VERSION 5.8 ;
BUSBITCHARS "[]" ;
DIVIDERCHAR "/" ;
UNITS
    DATABASE MICRONS 1000 ;
END UNITS

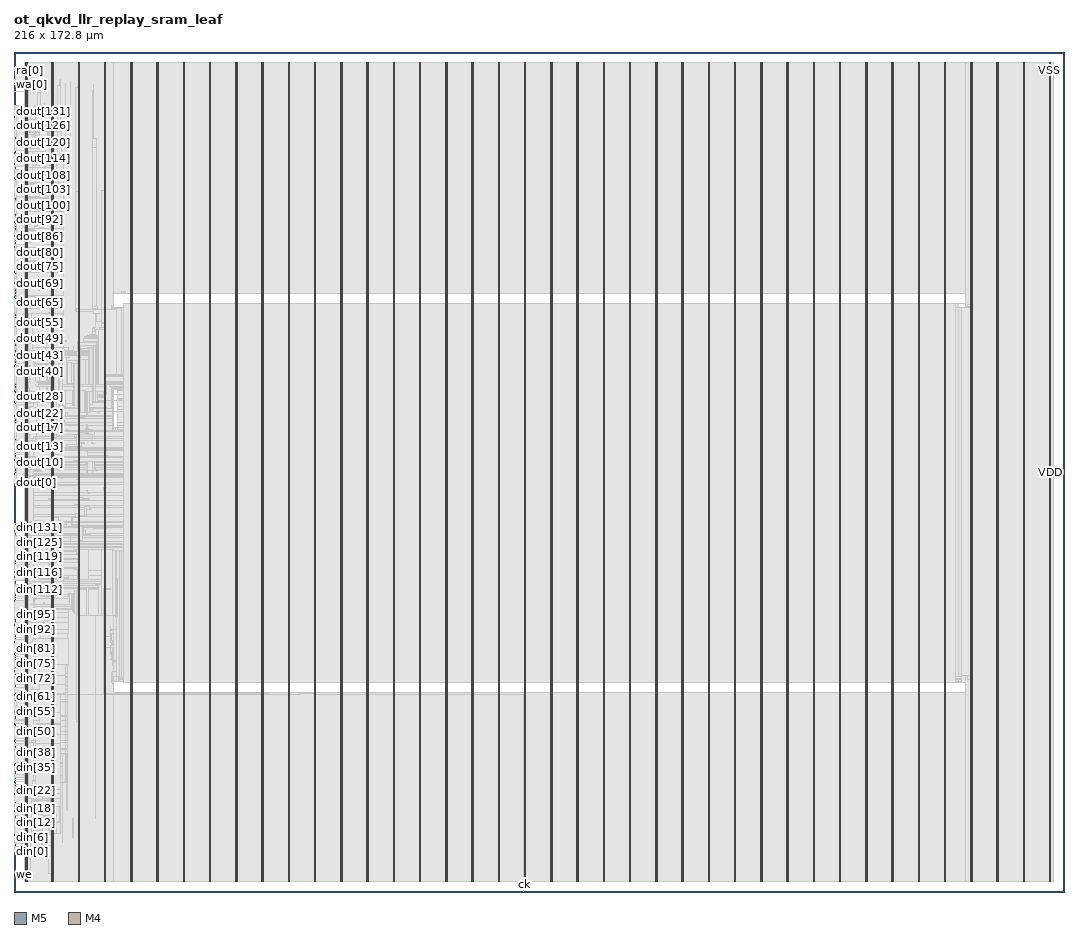
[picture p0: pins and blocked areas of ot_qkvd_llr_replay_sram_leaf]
MACRO ot_qkvd_llr_replay_sram_leaf
  FOREIGN ot_qkvd_llr_replay_sram_leaf 0 0 ;
  CLASS BLOCK ;
  SIZE 216 BY 172.8 ;
  PIN ck
    DIRECTION INPUT ;
    USE SIGNAL ;
    PORT
      LAYER M5 ;
        RECT  104.976 0 105 0.084 ;
    END
    PORT
      LAYER M5 ;
        RECT  104.976 0.016 105 0.085 ;
    END
  END ck
  PIN din[0]
    DIRECTION INPUT ;
    USE SIGNAL ;
    PORT
      LAYER M4 ;
        RECT  0 8.256 0.084 8.28 ;
    END
  END din[0]
  PIN din[100]
    DIRECTION INPUT ;
    USE SIGNAL ;
    PORT
      LAYER M4 ;
        RECT  0 57.888 0.084 57.912 ;
    END
  END din[100]
  PIN din[101]
    DIRECTION INPUT ;
    USE SIGNAL ;
    PORT
      LAYER M4 ;
        RECT  0 58.368 0.084 58.392 ;
    END
  END din[101]
  PIN din[102]
    DIRECTION INPUT ;
    USE SIGNAL ;
    PORT
      LAYER M4 ;
        RECT  0 58.848 0.084 58.872 ;
    END
  END din[102]
  PIN din[103]
    DIRECTION INPUT ;
    USE SIGNAL ;
    PORT
      LAYER M4 ;
        RECT  0 59.376 0.084 59.4 ;
    END
  END din[103]
  PIN din[104]
    DIRECTION INPUT ;
    USE SIGNAL ;
    PORT
      LAYER M4 ;
        RECT  0 59.856 0.084 59.88 ;
    END
  END din[104]
  PIN din[105]
    DIRECTION INPUT ;
    USE SIGNAL ;
    PORT
      LAYER M4 ;
        RECT  0 60.336 0.084 60.36 ;
    END
  END din[105]
  PIN din[106]
    DIRECTION INPUT ;
    USE SIGNAL ;
    PORT
      LAYER M4 ;
        RECT  0 60.864 0.084 60.888 ;
    END
  END din[106]
  PIN din[107]
    DIRECTION INPUT ;
    USE SIGNAL ;
    PORT
      LAYER M4 ;
        RECT  0 61.344 0.084 61.368 ;
    END
  END din[107]
  PIN din[108]
    DIRECTION INPUT ;
    USE SIGNAL ;
    PORT
      LAYER M4 ;
        RECT  0 61.824 0.084 61.848 ;
    END
  END din[108]
  PIN din[109]
    DIRECTION INPUT ;
    USE SIGNAL ;
    PORT
      LAYER M4 ;
        RECT  0 62.352 0.084 62.376 ;
    END
  END din[109]
  PIN din[10]
    DIRECTION INPUT ;
    USE SIGNAL ;
    PORT
      LAYER M4 ;
        RECT  0 13.2 0.084 13.224 ;
    END
  END din[10]
  PIN din[110]
    DIRECTION INPUT ;
    USE SIGNAL ;
    PORT
      LAYER M4 ;
        RECT  0 62.832 0.084 62.856 ;
    END
  END din[110]
  PIN din[111]
    DIRECTION INPUT ;
    USE SIGNAL ;
    PORT
      LAYER M4 ;
        RECT  0 63.312 0.084 63.336 ;
    END
  END din[111]
  PIN din[112]
    DIRECTION INPUT ;
    USE SIGNAL ;
    PORT
      LAYER M4 ;
        RECT  0 63.84 0.084 63.864 ;
    END
  END din[112]
  PIN din[113]
    DIRECTION INPUT ;
    USE SIGNAL ;
    PORT
      LAYER M4 ;
        RECT  0 64.32 0.084 64.344 ;
    END
  END din[113]
  PIN din[114]
    DIRECTION INPUT ;
    USE SIGNAL ;
    PORT
      LAYER M4 ;
        RECT  0 64.8 0.084 64.824 ;
    END
  END din[114]
  PIN din[115]
    DIRECTION INPUT ;
    USE SIGNAL ;
    PORT
      LAYER M4 ;
        RECT  0 65.328 0.084 65.352 ;
    END
  END din[115]
  PIN din[116]
    DIRECTION INPUT ;
    USE SIGNAL ;
    PORT
      LAYER M4 ;
        RECT  0 65.808 0.084 65.832 ;
    END
  END din[116]
  PIN din[117]
    DIRECTION INPUT ;
    USE SIGNAL ;
    PORT
      LAYER M4 ;
        RECT  0 66.288 0.084 66.312 ;
    END
  END din[117]
  PIN din[118]
    DIRECTION INPUT ;
    USE SIGNAL ;
    PORT
      LAYER M4 ;
        RECT  0 66.816 0.084 66.84 ;
    END
  END din[118]
  PIN din[119]
    DIRECTION INPUT ;
    USE SIGNAL ;
    PORT
      LAYER M4 ;
        RECT  0 67.296 0.084 67.32 ;
    END
  END din[119]
  PIN din[11]
    DIRECTION INPUT ;
    USE SIGNAL ;
    PORT
      LAYER M4 ;
        RECT  0 13.68 0.084 13.704 ;
    END
  END din[11]
  PIN din[120]
    DIRECTION INPUT ;
    USE SIGNAL ;
    PORT
      LAYER M4 ;
        RECT  0 67.776 0.084 67.8 ;
    END
  END din[120]
  PIN din[121]
    DIRECTION INPUT ;
    USE SIGNAL ;
    PORT
      LAYER M4 ;
        RECT  0 68.304 0.084 68.328 ;
    END
  END din[121]
  PIN din[122]
    DIRECTION INPUT ;
    USE SIGNAL ;
    PORT
      LAYER M4 ;
        RECT  0 68.784 0.084 68.808 ;
    END
  END din[122]
  PIN din[123]
    DIRECTION INPUT ;
    USE SIGNAL ;
    PORT
      LAYER M4 ;
        RECT  0 69.264 0.084 69.288 ;
    END
  END din[123]
  PIN din[124]
    DIRECTION INPUT ;
    USE SIGNAL ;
    PORT
      LAYER M4 ;
        RECT  0 69.792 0.084 69.816 ;
    END
  END din[124]
  PIN din[125]
    DIRECTION INPUT ;
    USE SIGNAL ;
    PORT
      LAYER M4 ;
        RECT  0 70.272 0.084 70.296 ;
    END
  END din[125]
  PIN din[126]
    DIRECTION INPUT ;
    USE SIGNAL ;
    PORT
      LAYER M4 ;
        RECT  0 70.8 0.084 70.824 ;
    END
  END din[126]
  PIN din[127]
    DIRECTION INPUT ;
    USE SIGNAL ;
    PORT
      LAYER M4 ;
        RECT  0 71.28 0.084 71.304 ;
    END
  END din[127]
  PIN din[128]
    DIRECTION INPUT ;
    USE SIGNAL ;
    PORT
      LAYER M4 ;
        RECT  0 71.76 0.084 71.784 ;
    END
  END din[128]
  PIN din[129]
    DIRECTION INPUT ;
    USE SIGNAL ;
    PORT
      LAYER M4 ;
        RECT  0 72.288 0.084 72.312 ;
    END
  END din[129]
  PIN din[12]
    DIRECTION INPUT ;
    USE SIGNAL ;
    PORT
      LAYER M4 ;
        RECT  0 14.208 0.084 14.232 ;
    END
  END din[12]
  PIN din[130]
    DIRECTION INPUT ;
    USE SIGNAL ;
    PORT
      LAYER M4 ;
        RECT  0 72.768 0.084 72.792 ;
    END
  END din[130]
  PIN din[131]
    DIRECTION INPUT ;
    USE SIGNAL ;
    PORT
      LAYER M4 ;
        RECT  0 73.248 0.084 73.272 ;
    END
  END din[131]
  PIN din[132]
    DIRECTION INPUT ;
    USE SIGNAL ;
    PORT
      LAYER M4 ;
        RECT  0 73.776 0.084 73.8 ;
    END
  END din[132]
  PIN din[133]
    DIRECTION INPUT ;
    USE SIGNAL ;
    PORT
      LAYER M4 ;
        RECT  0 74.256 0.084 74.28 ;
    END
  END din[133]
  PIN din[134]
    DIRECTION INPUT ;
    USE SIGNAL ;
    PORT
      LAYER M4 ;
        RECT  0 74.736 0.084 74.76 ;
    END
  END din[134]
  PIN din[135]
    DIRECTION INPUT ;
    USE SIGNAL ;
    PORT
      LAYER M4 ;
        RECT  0 75.264 0.084 75.288 ;
    END
  END din[135]
  PIN din[136]
    DIRECTION INPUT ;
    USE SIGNAL ;
    PORT
      LAYER M4 ;
        RECT  0 75.744 0.084 75.768 ;
    END
  END din[136]
  PIN din[13]
    DIRECTION INPUT ;
    USE SIGNAL ;
    PORT
      LAYER M4 ;
        RECT  0 14.688 0.084 14.712 ;
    END
  END din[13]
  PIN din[14]
    DIRECTION INPUT ;
    USE SIGNAL ;
    PORT
      LAYER M4 ;
        RECT  0 15.168 0.084 15.192 ;
    END
  END din[14]
  PIN din[15]
    DIRECTION INPUT ;
    USE SIGNAL ;
    PORT
      LAYER M4 ;
        RECT  0 15.696 0.084 15.72 ;
    END
  END din[15]
  PIN din[16]
    DIRECTION INPUT ;
    USE SIGNAL ;
    PORT
      LAYER M4 ;
        RECT  0 16.176 0.084 16.2 ;
    END
  END din[16]
  PIN din[17]
    DIRECTION INPUT ;
    USE SIGNAL ;
    PORT
      LAYER M4 ;
        RECT  0 16.656 0.084 16.68 ;
    END
  END din[17]
  PIN din[18]
    DIRECTION INPUT ;
    USE SIGNAL ;
    PORT
      LAYER M4 ;
        RECT  0 17.184 0.084 17.208 ;
    END
  END din[18]
  PIN din[19]
    DIRECTION INPUT ;
    USE SIGNAL ;
    PORT
      LAYER M4 ;
        RECT  0 17.664 0.084 17.688 ;
    END
  END din[19]
  PIN din[1]
    DIRECTION INPUT ;
    USE SIGNAL ;
    PORT
      LAYER M4 ;
        RECT  0 8.736 0.084 8.76 ;
    END
  END din[1]
  PIN din[20]
    DIRECTION INPUT ;
    USE SIGNAL ;
    PORT
      LAYER M4 ;
        RECT  0 18.144 0.084 18.168 ;
    END
  END din[20]
  PIN din[21]
    DIRECTION INPUT ;
    USE SIGNAL ;
    PORT
      LAYER M4 ;
        RECT  0 18.672 0.084 18.696 ;
    END
  END din[21]
  PIN din[22]
    DIRECTION INPUT ;
    USE SIGNAL ;
    PORT
      LAYER M4 ;
        RECT  0 19.152 0.084 19.176 ;
    END
  END din[22]
  PIN din[23]
    DIRECTION INPUT ;
    USE SIGNAL ;
    PORT
      LAYER M4 ;
        RECT  0 19.632 0.084 19.656 ;
    END
  END din[23]
  PIN din[24]
    DIRECTION INPUT ;
    USE SIGNAL ;
    PORT
      LAYER M4 ;
        RECT  0 20.16 0.084 20.184 ;
    END
  END din[24]
  PIN din[25]
    DIRECTION INPUT ;
    USE SIGNAL ;
    PORT
      LAYER M4 ;
        RECT  0 20.64 0.084 20.664 ;
    END
  END din[25]
  PIN din[26]
    DIRECTION INPUT ;
    USE SIGNAL ;
    PORT
      LAYER M4 ;
        RECT  0 21.12 0.084 21.144 ;
    END
  END din[26]
  PIN din[27]
    DIRECTION INPUT ;
    USE SIGNAL ;
    PORT
      LAYER M4 ;
        RECT  0 21.648 0.084 21.672 ;
    END
  END din[27]
  PIN din[28]
    DIRECTION INPUT ;
    USE SIGNAL ;
    PORT
      LAYER M4 ;
        RECT  0 22.128 0.084 22.152 ;
    END
  END din[28]
  PIN din[29]
    DIRECTION INPUT ;
    USE SIGNAL ;
    PORT
      LAYER M4 ;
        RECT  0 22.608 0.084 22.632 ;
    END
  END din[29]
  PIN din[2]
    DIRECTION INPUT ;
    USE SIGNAL ;
    PORT
      LAYER M4 ;
        RECT  0 9.216 0.084 9.24 ;
    END
  END din[2]
  PIN din[30]
    DIRECTION INPUT ;
    USE SIGNAL ;
    PORT
      LAYER M4 ;
        RECT  0 23.136 0.084 23.16 ;
    END
  END din[30]
  PIN din[31]
    DIRECTION INPUT ;
    USE SIGNAL ;
    PORT
      LAYER M4 ;
        RECT  0 23.616 0.084 23.64 ;
    END
  END din[31]
  PIN din[32]
    DIRECTION INPUT ;
    USE SIGNAL ;
    PORT
      LAYER M4 ;
        RECT  0 24.096 0.084 24.12 ;
    END
  END din[32]
  PIN din[33]
    DIRECTION INPUT ;
    USE SIGNAL ;
    PORT
      LAYER M4 ;
        RECT  0 24.624 0.084 24.648 ;
    END
  END din[33]
  PIN din[34]
    DIRECTION INPUT ;
    USE SIGNAL ;
    PORT
      LAYER M4 ;
        RECT  0 25.104 0.084 25.128 ;
    END
  END din[34]
  PIN din[35]
    DIRECTION INPUT ;
    USE SIGNAL ;
    PORT
      LAYER M4 ;
        RECT  0 25.632 0.084 25.656 ;
    END
  END din[35]
  PIN din[36]
    DIRECTION INPUT ;
    USE SIGNAL ;
    PORT
      LAYER M4 ;
        RECT  0 26.112 0.084 26.136 ;
    END
  END din[36]
  PIN din[37]
    DIRECTION INPUT ;
    USE SIGNAL ;
    PORT
      LAYER M4 ;
        RECT  0 26.592 0.084 26.616 ;
    END
  END din[37]
  PIN din[38]
    DIRECTION INPUT ;
    USE SIGNAL ;
    PORT
      LAYER M4 ;
        RECT  0 27.12 0.084 27.144 ;
    END
  END din[38]
  PIN din[39]
    DIRECTION INPUT ;
    USE SIGNAL ;
    PORT
      LAYER M4 ;
        RECT  0 27.6 0.084 27.624 ;
    END
  END din[39]
  PIN din[3]
    DIRECTION INPUT ;
    USE SIGNAL ;
    PORT
      LAYER M4 ;
        RECT  0 9.744 0.084 9.768 ;
    END
  END din[3]
  PIN din[40]
    DIRECTION INPUT ;
    USE SIGNAL ;
    PORT
      LAYER M4 ;
        RECT  0 28.08 0.084 28.104 ;
    END
  END din[40]
  PIN din[41]
    DIRECTION INPUT ;
    USE SIGNAL ;
    PORT
      LAYER M4 ;
        RECT  0 28.608 0.084 28.632 ;
    END
  END din[41]
  PIN din[42]
    DIRECTION INPUT ;
    USE SIGNAL ;
    PORT
      LAYER M4 ;
        RECT  0 29.088 0.084 29.112 ;
    END
  END din[42]
  PIN din[43]
    DIRECTION INPUT ;
    USE SIGNAL ;
    PORT
      LAYER M4 ;
        RECT  0 29.568 0.084 29.592 ;
    END
  END din[43]
  PIN din[44]
    DIRECTION INPUT ;
    USE SIGNAL ;
    PORT
      LAYER M4 ;
        RECT  0 30.096 0.084 30.12 ;
    END
  END din[44]
  PIN din[45]
    DIRECTION INPUT ;
    USE SIGNAL ;
    PORT
      LAYER M4 ;
        RECT  0 30.576 0.084 30.6 ;
    END
  END din[45]
  PIN din[46]
    DIRECTION INPUT ;
    USE SIGNAL ;
    PORT
      LAYER M4 ;
        RECT  0 31.056 0.084 31.08 ;
    END
  END din[46]
  PIN din[47]
    DIRECTION INPUT ;
    USE SIGNAL ;
    PORT
      LAYER M4 ;
        RECT  0 31.584 0.084 31.608 ;
    END
  END din[47]
  PIN din[48]
    DIRECTION INPUT ;
    USE SIGNAL ;
    PORT
      LAYER M4 ;
        RECT  0 32.064 0.084 32.088 ;
    END
  END din[48]
  PIN din[49]
    DIRECTION INPUT ;
    USE SIGNAL ;
    PORT
      LAYER M4 ;
        RECT  0 32.544 0.084 32.568 ;
    END
  END din[49]
  PIN din[4]
    DIRECTION INPUT ;
    USE SIGNAL ;
    PORT
      LAYER M4 ;
        RECT  0 10.224 0.084 10.248 ;
    END
  END din[4]
  PIN din[50]
    DIRECTION INPUT ;
    USE SIGNAL ;
    PORT
      LAYER M4 ;
        RECT  0 33.072 0.084 33.096 ;
    END
  END din[50]
  PIN din[51]
    DIRECTION INPUT ;
    USE SIGNAL ;
    PORT
      LAYER M4 ;
        RECT  0 33.552 0.084 33.576 ;
    END
  END din[51]
  PIN din[52]
    DIRECTION INPUT ;
    USE SIGNAL ;
    PORT
      LAYER M4 ;
        RECT  0 34.032 0.084 34.056 ;
    END
  END din[52]
  PIN din[53]
    DIRECTION INPUT ;
    USE SIGNAL ;
    PORT
      LAYER M4 ;
        RECT  0 34.56 0.084 34.584 ;
    END
  END din[53]
  PIN din[54]
    DIRECTION INPUT ;
    USE SIGNAL ;
    PORT
      LAYER M4 ;
        RECT  0 35.04 0.084 35.064 ;
    END
  END din[54]
  PIN din[55]
    DIRECTION INPUT ;
    USE SIGNAL ;
    PORT
      LAYER M4 ;
        RECT  0 35.52 0.084 35.544 ;
    END
  END din[55]
  PIN din[56]
    DIRECTION INPUT ;
    USE SIGNAL ;
    PORT
      LAYER M4 ;
        RECT  0 36.048 0.084 36.072 ;
    END
  END din[56]
  PIN din[57]
    DIRECTION INPUT ;
    USE SIGNAL ;
    PORT
      LAYER M4 ;
        RECT  0 36.528 0.084 36.552 ;
    END
  END din[57]
  PIN din[58]
    DIRECTION INPUT ;
    USE SIGNAL ;
    PORT
      LAYER M4 ;
        RECT  0 37.008 0.084 37.032 ;
    END
  END din[58]
  PIN din[59]
    DIRECTION INPUT ;
    USE SIGNAL ;
    PORT
      LAYER M4 ;
        RECT  0 37.536 0.084 37.56 ;
    END
  END din[59]
  PIN din[5]
    DIRECTION INPUT ;
    USE SIGNAL ;
    PORT
      LAYER M4 ;
        RECT  0 10.704 0.084 10.728 ;
    END
  END din[5]
  PIN din[60]
    DIRECTION INPUT ;
    USE SIGNAL ;
    PORT
      LAYER M4 ;
        RECT  0 38.016 0.084 38.04 ;
    END
  END din[60]
  PIN din[61]
    DIRECTION INPUT ;
    USE SIGNAL ;
    PORT
      LAYER M4 ;
        RECT  0 38.496 0.084 38.52 ;
    END
  END din[61]
  PIN din[62]
    DIRECTION INPUT ;
    USE SIGNAL ;
    PORT
      LAYER M4 ;
        RECT  0 39.024 0.084 39.048 ;
    END
  END din[62]
  PIN din[63]
    DIRECTION INPUT ;
    USE SIGNAL ;
    PORT
      LAYER M4 ;
        RECT  0 39.504 0.084 39.528 ;
    END
  END din[63]
  PIN din[64]
    DIRECTION INPUT ;
    USE SIGNAL ;
    PORT
      LAYER M4 ;
        RECT  0 39.984 0.084 40.008 ;
    END
  END din[64]
  PIN din[65]
    DIRECTION INPUT ;
    USE SIGNAL ;
    PORT
      LAYER M4 ;
        RECT  0 40.512 0.084 40.536 ;
    END
  END din[65]
  PIN din[66]
    DIRECTION INPUT ;
    USE SIGNAL ;
    PORT
      LAYER M4 ;
        RECT  0 40.992 0.084 41.016 ;
    END
  END din[66]
  PIN din[67]
    DIRECTION INPUT ;
    USE SIGNAL ;
    PORT
      LAYER M4 ;
        RECT  0 41.472 0.084 41.496 ;
    END
  END din[67]
  PIN din[68]
    DIRECTION INPUT ;
    USE SIGNAL ;
    PORT
      LAYER M4 ;
        RECT  0 42 0.084 42.024 ;
    END
  END din[68]
  PIN din[69]
    DIRECTION INPUT ;
    USE SIGNAL ;
    PORT
      LAYER M4 ;
        RECT  0 42.48 0.084 42.504 ;
    END
  END din[69]
  PIN din[6]
    DIRECTION INPUT ;
    USE SIGNAL ;
    PORT
      LAYER M4 ;
        RECT  0 11.232 0.084 11.256 ;
    END
  END din[6]
  PIN din[70]
    DIRECTION INPUT ;
    USE SIGNAL ;
    PORT
      LAYER M4 ;
        RECT  0 42.96 0.084 42.984 ;
    END
  END din[70]
  PIN din[71]
    DIRECTION INPUT ;
    USE SIGNAL ;
    PORT
      LAYER M4 ;
        RECT  0 43.488 0.084 43.512 ;
    END
  END din[71]
  PIN din[72]
    DIRECTION INPUT ;
    USE SIGNAL ;
    PORT
      LAYER M4 ;
        RECT  0 43.968 0.084 43.992 ;
    END
  END din[72]
  PIN din[73]
    DIRECTION INPUT ;
    USE SIGNAL ;
    PORT
      LAYER M4 ;
        RECT  0 44.448 0.084 44.472 ;
    END
  END din[73]
  PIN din[74]
    DIRECTION INPUT ;
    USE SIGNAL ;
    PORT
      LAYER M4 ;
        RECT  0 44.976 0.084 45 ;
    END
  END din[74]
  PIN din[75]
    DIRECTION INPUT ;
    USE SIGNAL ;
    PORT
      LAYER M4 ;
        RECT  0 45.456 0.084 45.48 ;
    END
  END din[75]
  PIN din[76]
    DIRECTION INPUT ;
    USE SIGNAL ;
    PORT
      LAYER M4 ;
        RECT  0 45.936 0.084 45.96 ;
    END
  END din[76]
  PIN din[77]
    DIRECTION INPUT ;
    USE SIGNAL ;
    PORT
      LAYER M4 ;
        RECT  0 46.464 0.084 46.488 ;
    END
  END din[77]
  PIN din[78]
    DIRECTION INPUT ;
    USE SIGNAL ;
    PORT
      LAYER M4 ;
        RECT  0 46.944 0.084 46.968 ;
    END
  END din[78]
  PIN din[79]
    DIRECTION INPUT ;
    USE SIGNAL ;
    PORT
      LAYER M4 ;
        RECT  0 47.472 0.084 47.496 ;
    END
  END din[79]
  PIN din[7]
    DIRECTION INPUT ;
    USE SIGNAL ;
    PORT
      LAYER M4 ;
        RECT  0 11.712 0.084 11.736 ;
    END
  END din[7]
  PIN din[80]
    DIRECTION INPUT ;
    USE SIGNAL ;
    PORT
      LAYER M4 ;
        RECT  0 47.952 0.084 47.976 ;
    END
  END din[80]
  PIN din[81]
    DIRECTION INPUT ;
    USE SIGNAL ;
    PORT
      LAYER M4 ;
        RECT  0 48.432 0.084 48.456 ;
    END
  END din[81]
  PIN din[82]
    DIRECTION INPUT ;
    USE SIGNAL ;
    PORT
      LAYER M4 ;
        RECT  0 48.96 0.084 48.984 ;
    END
  END din[82]
  PIN din[83]
    DIRECTION INPUT ;
    USE SIGNAL ;
    PORT
      LAYER M4 ;
        RECT  0 49.44 0.084 49.464 ;
    END
  END din[83]
  PIN din[84]
    DIRECTION INPUT ;
    USE SIGNAL ;
    PORT
      LAYER M4 ;
        RECT  0 49.92 0.084 49.944 ;
    END
  END din[84]
  PIN din[85]
    DIRECTION INPUT ;
    USE SIGNAL ;
    PORT
      LAYER M4 ;
        RECT  0 50.448 0.084 50.472 ;
    END
  END din[85]
  PIN din[86]
    DIRECTION INPUT ;
    USE SIGNAL ;
    PORT
      LAYER M4 ;
        RECT  0 50.928 0.084 50.952 ;
    END
  END din[86]
  PIN din[87]
    DIRECTION INPUT ;
    USE SIGNAL ;
    PORT
      LAYER M4 ;
        RECT  0 51.408 0.084 51.432 ;
    END
  END din[87]
  PIN din[88]
    DIRECTION INPUT ;
    USE SIGNAL ;
    PORT
      LAYER M4 ;
        RECT  0 51.936 0.084 51.96 ;
    END
  END din[88]
  PIN din[89]
    DIRECTION INPUT ;
    USE SIGNAL ;
    PORT
      LAYER M4 ;
        RECT  0 52.416 0.084 52.44 ;
    END
  END din[89]
  PIN din[8]
    DIRECTION INPUT ;
    USE SIGNAL ;
    PORT
      LAYER M4 ;
        RECT  0 12.192 0.084 12.216 ;
    END
  END din[8]
  PIN din[90]
    DIRECTION INPUT ;
    USE SIGNAL ;
    PORT
      LAYER M4 ;
        RECT  0 52.896 0.084 52.92 ;
    END
  END din[90]
  PIN din[91]
    DIRECTION INPUT ;
    USE SIGNAL ;
    PORT
      LAYER M4 ;
        RECT  0 53.424 0.084 53.448 ;
    END
  END din[91]
  PIN din[92]
    DIRECTION INPUT ;
    USE SIGNAL ;
    PORT
      LAYER M4 ;
        RECT  0 53.904 0.084 53.928 ;
    END
  END din[92]
  PIN din[93]
    DIRECTION INPUT ;
    USE SIGNAL ;
    PORT
      LAYER M4 ;
        RECT  0 54.384 0.084 54.408 ;
    END
  END din[93]
  PIN din[94]
    DIRECTION INPUT ;
    USE SIGNAL ;
    PORT
      LAYER M4 ;
        RECT  0 54.912 0.084 54.936 ;
    END
  END din[94]
  PIN din[95]
    DIRECTION INPUT ;
    USE SIGNAL ;
    PORT
      LAYER M4 ;
        RECT  0 55.392 0.084 55.416 ;
    END
  END din[95]
  PIN din[96]
    DIRECTION INPUT ;
    USE SIGNAL ;
    PORT
      LAYER M4 ;
        RECT  0 55.872 0.084 55.896 ;
    END
  END din[96]
  PIN din[97]
    DIRECTION INPUT ;
    USE SIGNAL ;
    PORT
      LAYER M4 ;
        RECT  0 56.4 0.084 56.424 ;
    END
  END din[97]
  PIN din[98]
    DIRECTION INPUT ;
    USE SIGNAL ;
    PORT
      LAYER M4 ;
        RECT  0 56.88 0.084 56.904 ;
    END
  END din[98]
  PIN din[99]
    DIRECTION INPUT ;
    USE SIGNAL ;
    PORT
      LAYER M4 ;
        RECT  0 57.36 0.084 57.384 ;
    END
  END din[99]
  PIN din[9]
    DIRECTION INPUT ;
    USE SIGNAL ;
    PORT
      LAYER M4 ;
        RECT  0 12.72 0.084 12.744 ;
    END
  END din[9]
  PIN dout[0]
    DIRECTION OUTPUT ;
    USE SIGNAL ;
    PORT
      LAYER M4 ;
        RECT  0 84.288 0.084 84.312 ;
    END
  END dout[0]
  PIN dout[100]
    DIRECTION OUTPUT ;
    USE SIGNAL ;
    PORT
      LAYER M4 ;
        RECT  0 141.216 0.084 141.24 ;
    END
  END dout[100]
  PIN dout[101]
    DIRECTION OUTPUT ;
    USE SIGNAL ;
    PORT
      LAYER M4 ;
        RECT  0 141.792 0.084 141.816 ;
    END
  END dout[101]
  PIN dout[102]
    DIRECTION OUTPUT ;
    USE SIGNAL ;
    PORT
      LAYER M4 ;
        RECT  0 142.368 0.084 142.392 ;
    END
  END dout[102]
  PIN dout[103]
    DIRECTION OUTPUT ;
    USE SIGNAL ;
    PORT
      LAYER M4 ;
        RECT  0 142.896 0.084 142.92 ;
    END
  END dout[103]
  PIN dout[104]
    DIRECTION OUTPUT ;
    USE SIGNAL ;
    PORT
      LAYER M4 ;
        RECT  0 143.472 0.084 143.496 ;
    END
  END dout[104]
  PIN dout[105]
    DIRECTION OUTPUT ;
    USE SIGNAL ;
    PORT
      LAYER M4 ;
        RECT  0 144.048 0.084 144.072 ;
    END
  END dout[105]
  PIN dout[106]
    DIRECTION OUTPUT ;
    USE SIGNAL ;
    PORT
      LAYER M4 ;
        RECT  0 144.624 0.084 144.648 ;
    END
  END dout[106]
  PIN dout[107]
    DIRECTION OUTPUT ;
    USE SIGNAL ;
    PORT
      LAYER M4 ;
        RECT  0 145.2 0.084 145.224 ;
    END
  END dout[107]
  PIN dout[108]
    DIRECTION OUTPUT ;
    USE SIGNAL ;
    PORT
      LAYER M4 ;
        RECT  0 145.776 0.084 145.8 ;
    END
  END dout[108]
  PIN dout[109]
    DIRECTION OUTPUT ;
    USE SIGNAL ;
    PORT
      LAYER M4 ;
        RECT  0 146.352 0.084 146.376 ;
    END
  END dout[109]
  PIN dout[10]
    DIRECTION OUTPUT ;
    USE SIGNAL ;
    PORT
      LAYER M4 ;
        RECT  0 89.952 0.084 89.976 ;
    END
  END dout[10]
  PIN dout[110]
    DIRECTION OUTPUT ;
    USE SIGNAL ;
    PORT
      LAYER M4 ;
        RECT  0 146.88 0.084 146.904 ;
    END
  END dout[110]
  PIN dout[111]
    DIRECTION OUTPUT ;
    USE SIGNAL ;
    PORT
      LAYER M4 ;
        RECT  0 147.456 0.084 147.48 ;
    END
  END dout[111]
  PIN dout[112]
    DIRECTION OUTPUT ;
    USE SIGNAL ;
    PORT
      LAYER M4 ;
        RECT  0 148.032 0.084 148.056 ;
    END
  END dout[112]
  PIN dout[113]
    DIRECTION OUTPUT ;
    USE SIGNAL ;
    PORT
      LAYER M4 ;
        RECT  0 148.608 0.084 148.632 ;
    END
  END dout[113]
  PIN dout[114]
    DIRECTION OUTPUT ;
    USE SIGNAL ;
    PORT
      LAYER M4 ;
        RECT  0 149.184 0.084 149.208 ;
    END
  END dout[114]
  PIN dout[115]
    DIRECTION OUTPUT ;
    USE SIGNAL ;
    PORT
      LAYER M4 ;
        RECT  0 149.76 0.084 149.784 ;
    END
  END dout[115]
  PIN dout[116]
    DIRECTION OUTPUT ;
    USE SIGNAL ;
    PORT
      LAYER M4 ;
        RECT  0 150.336 0.084 150.36 ;
    END
  END dout[116]
  PIN dout[117]
    DIRECTION OUTPUT ;
    USE SIGNAL ;
    PORT
      LAYER M4 ;
        RECT  0 150.864 0.084 150.888 ;
    END
  END dout[117]
  PIN dout[118]
    DIRECTION OUTPUT ;
    USE SIGNAL ;
    PORT
      LAYER M4 ;
        RECT  0 151.44 0.084 151.464 ;
    END
  END dout[118]
  PIN dout[119]
    DIRECTION OUTPUT ;
    USE SIGNAL ;
    PORT
      LAYER M4 ;
        RECT  0 152.016 0.084 152.04 ;
    END
  END dout[119]
  PIN dout[11]
    DIRECTION OUTPUT ;
    USE SIGNAL ;
    PORT
      LAYER M4 ;
        RECT  0 90.528 0.084 90.552 ;
    END
  END dout[11]
  PIN dout[120]
    DIRECTION OUTPUT ;
    USE SIGNAL ;
    PORT
      LAYER M4 ;
        RECT  0 152.592 0.084 152.616 ;
    END
  END dout[120]
  PIN dout[121]
    DIRECTION OUTPUT ;
    USE SIGNAL ;
    PORT
      LAYER M4 ;
        RECT  0 153.168 0.084 153.192 ;
    END
  END dout[121]
  PIN dout[122]
    DIRECTION OUTPUT ;
    USE SIGNAL ;
    PORT
      LAYER M4 ;
        RECT  0 153.744 0.084 153.768 ;
    END
  END dout[122]
  PIN dout[123]
    DIRECTION OUTPUT ;
    USE SIGNAL ;
    PORT
      LAYER M4 ;
        RECT  0 154.32 0.084 154.344 ;
    END
  END dout[123]
  PIN dout[124]
    DIRECTION OUTPUT ;
    USE SIGNAL ;
    PORT
      LAYER M4 ;
        RECT  0 154.848 0.084 154.872 ;
    END
  END dout[124]
  PIN dout[125]
    DIRECTION OUTPUT ;
    USE SIGNAL ;
    PORT
      LAYER M4 ;
        RECT  0 155.424 0.084 155.448 ;
    END
  END dout[125]
  PIN dout[126]
    DIRECTION OUTPUT ;
    USE SIGNAL ;
    PORT
      LAYER M4 ;
        RECT  0 156 0.084 156.024 ;
    END
  END dout[126]
  PIN dout[127]
    DIRECTION OUTPUT ;
    USE SIGNAL ;
    PORT
      LAYER M4 ;
        RECT  0 156.576 0.084 156.6 ;
    END
  END dout[127]
  PIN dout[128]
    DIRECTION OUTPUT ;
    USE SIGNAL ;
    PORT
      LAYER M4 ;
        RECT  0 157.152 0.084 157.176 ;
    END
  END dout[128]
  PIN dout[129]
    DIRECTION OUTPUT ;
    USE SIGNAL ;
    PORT
      LAYER M4 ;
        RECT  0 157.728 0.084 157.752 ;
    END
  END dout[129]
  PIN dout[12]
    DIRECTION OUTPUT ;
    USE SIGNAL ;
    PORT
      LAYER M4 ;
        RECT  0 91.104 0.084 91.128 ;
    END
  END dout[12]
  PIN dout[130]
    DIRECTION OUTPUT ;
    USE SIGNAL ;
    PORT
      LAYER M4 ;
        RECT  0 158.304 0.084 158.328 ;
    END
  END dout[130]
  PIN dout[131]
    DIRECTION OUTPUT ;
    USE SIGNAL ;
    PORT
      LAYER M4 ;
        RECT  0 158.88 0.084 158.904 ;
    END
  END dout[131]
  PIN dout[132]
    DIRECTION OUTPUT ;
    USE SIGNAL ;
    PORT
      LAYER M4 ;
        RECT  0 159.408 0.084 159.432 ;
    END
  END dout[132]
  PIN dout[133]
    DIRECTION OUTPUT ;
    USE SIGNAL ;
    PORT
      LAYER M4 ;
        RECT  0 159.984 0.084 160.008 ;
    END
  END dout[133]
  PIN dout[134]
    DIRECTION OUTPUT ;
    USE SIGNAL ;
    PORT
      LAYER M4 ;
        RECT  0 160.56 0.084 160.584 ;
    END
  END dout[134]
  PIN dout[135]
    DIRECTION OUTPUT ;
    USE SIGNAL ;
    PORT
      LAYER M4 ;
        RECT  0 161.136 0.084 161.16 ;
    END
  END dout[135]
  PIN dout[136]
    DIRECTION OUTPUT ;
    USE SIGNAL ;
    PORT
      LAYER M4 ;
        RECT  0 161.712 0.084 161.736 ;
    END
  END dout[136]
  PIN dout[13]
    DIRECTION OUTPUT ;
    USE SIGNAL ;
    PORT
      LAYER M4 ;
        RECT  0 91.68 0.084 91.704 ;
    END
  END dout[13]
  PIN dout[14]
    DIRECTION OUTPUT ;
    USE SIGNAL ;
    PORT
      LAYER M4 ;
        RECT  0 92.256 0.084 92.28 ;
    END
  END dout[14]
  PIN dout[15]
    DIRECTION OUTPUT ;
    USE SIGNAL ;
    PORT
      LAYER M4 ;
        RECT  0 92.832 0.084 92.856 ;
    END
  END dout[15]
  PIN dout[16]
    DIRECTION OUTPUT ;
    USE SIGNAL ;
    PORT
      LAYER M4 ;
        RECT  0 93.36 0.084 93.384 ;
    END
  END dout[16]
  PIN dout[17]
    DIRECTION OUTPUT ;
    USE SIGNAL ;
    PORT
      LAYER M4 ;
        RECT  0 93.936 0.084 93.96 ;
    END
  END dout[17]
  PIN dout[18]
    DIRECTION OUTPUT ;
    USE SIGNAL ;
    PORT
      LAYER M4 ;
        RECT  0 94.512 0.084 94.536 ;
    END
  END dout[18]
  PIN dout[19]
    DIRECTION OUTPUT ;
    USE SIGNAL ;
    PORT
      LAYER M4 ;
        RECT  0 95.088 0.084 95.112 ;
    END
  END dout[19]
  PIN dout[1]
    DIRECTION OUTPUT ;
    USE SIGNAL ;
    PORT
      LAYER M4 ;
        RECT  0 84.864 0.084 84.888 ;
    END
  END dout[1]
  PIN dout[20]
    DIRECTION OUTPUT ;
    USE SIGNAL ;
    PORT
      LAYER M4 ;
        RECT  0 95.664 0.084 95.688 ;
    END
  END dout[20]
  PIN dout[21]
    DIRECTION OUTPUT ;
    USE SIGNAL ;
    PORT
      LAYER M4 ;
        RECT  0 96.24 0.084 96.264 ;
    END
  END dout[21]
  PIN dout[22]
    DIRECTION OUTPUT ;
    USE SIGNAL ;
    PORT
      LAYER M4 ;
        RECT  0 96.816 0.084 96.84 ;
    END
  END dout[22]
  PIN dout[23]
    DIRECTION OUTPUT ;
    USE SIGNAL ;
    PORT
      LAYER M4 ;
        RECT  0 97.392 0.084 97.416 ;
    END
  END dout[23]
  PIN dout[24]
    DIRECTION OUTPUT ;
    USE SIGNAL ;
    PORT
      LAYER M4 ;
        RECT  0 97.92 0.084 97.944 ;
    END
  END dout[24]
  PIN dout[25]
    DIRECTION OUTPUT ;
    USE SIGNAL ;
    PORT
      LAYER M4 ;
        RECT  0 98.496 0.084 98.52 ;
    END
  END dout[25]
  PIN dout[26]
    DIRECTION OUTPUT ;
    USE SIGNAL ;
    PORT
      LAYER M4 ;
        RECT  0 99.072 0.084 99.096 ;
    END
  END dout[26]
  PIN dout[27]
    DIRECTION OUTPUT ;
    USE SIGNAL ;
    PORT
      LAYER M4 ;
        RECT  0 99.648 0.084 99.672 ;
    END
  END dout[27]
  PIN dout[28]
    DIRECTION OUTPUT ;
    USE SIGNAL ;
    PORT
      LAYER M4 ;
        RECT  0 100.224 0.084 100.248 ;
    END
  END dout[28]
  PIN dout[29]
    DIRECTION OUTPUT ;
    USE SIGNAL ;
    PORT
      LAYER M4 ;
        RECT  0 100.8 0.084 100.824 ;
    END
  END dout[29]
  PIN dout[2]
    DIRECTION OUTPUT ;
    USE SIGNAL ;
    PORT
      LAYER M4 ;
        RECT  0 85.392 0.084 85.416 ;
    END
  END dout[2]
  PIN dout[30]
    DIRECTION OUTPUT ;
    USE SIGNAL ;
    PORT
      LAYER M4 ;
        RECT  0 101.376 0.084 101.4 ;
    END
  END dout[30]
  PIN dout[31]
    DIRECTION OUTPUT ;
    USE SIGNAL ;
    PORT
      LAYER M4 ;
        RECT  0 101.904 0.084 101.928 ;
    END
  END dout[31]
  PIN dout[32]
    DIRECTION OUTPUT ;
    USE SIGNAL ;
    PORT
      LAYER M4 ;
        RECT  0 102.48 0.084 102.504 ;
    END
  END dout[32]
  PIN dout[33]
    DIRECTION OUTPUT ;
    USE SIGNAL ;
    PORT
      LAYER M4 ;
        RECT  0 103.056 0.084 103.08 ;
    END
  END dout[33]
  PIN dout[34]
    DIRECTION OUTPUT ;
    USE SIGNAL ;
    PORT
      LAYER M4 ;
        RECT  0 103.632 0.084 103.656 ;
    END
  END dout[34]
  PIN dout[35]
    DIRECTION OUTPUT ;
    USE SIGNAL ;
    PORT
      LAYER M4 ;
        RECT  0 104.208 0.084 104.232 ;
    END
  END dout[35]
  PIN dout[36]
    DIRECTION OUTPUT ;
    USE SIGNAL ;
    PORT
      LAYER M4 ;
        RECT  0 104.784 0.084 104.808 ;
    END
  END dout[36]
  PIN dout[37]
    DIRECTION OUTPUT ;
    USE SIGNAL ;
    PORT
      LAYER M4 ;
        RECT  0 105.36 0.084 105.384 ;
    END
  END dout[37]
  PIN dout[38]
    DIRECTION OUTPUT ;
    USE SIGNAL ;
    PORT
      LAYER M4 ;
        RECT  0 105.888 0.084 105.912 ;
    END
  END dout[38]
  PIN dout[39]
    DIRECTION OUTPUT ;
    USE SIGNAL ;
    PORT
      LAYER M4 ;
        RECT  0 106.464 0.084 106.488 ;
    END
  END dout[39]
  PIN dout[3]
    DIRECTION OUTPUT ;
    USE SIGNAL ;
    PORT
      LAYER M4 ;
        RECT  0 85.968 0.084 85.992 ;
    END
  END dout[3]
  PIN dout[40]
    DIRECTION OUTPUT ;
    USE SIGNAL ;
    PORT
      LAYER M4 ;
        RECT  0 107.04 0.084 107.064 ;
    END
  END dout[40]
  PIN dout[41]
    DIRECTION OUTPUT ;
    USE SIGNAL ;
    PORT
      LAYER M4 ;
        RECT  0 107.616 0.084 107.64 ;
    END
  END dout[41]
  PIN dout[42]
    DIRECTION OUTPUT ;
    USE SIGNAL ;
    PORT
      LAYER M4 ;
        RECT  0 108.192 0.084 108.216 ;
    END
  END dout[42]
  PIN dout[43]
    DIRECTION OUTPUT ;
    USE SIGNAL ;
    PORT
      LAYER M4 ;
        RECT  0 108.768 0.084 108.792 ;
    END
  END dout[43]
  PIN dout[44]
    DIRECTION OUTPUT ;
    USE SIGNAL ;
    PORT
      LAYER M4 ;
        RECT  0 109.344 0.084 109.368 ;
    END
  END dout[44]
  PIN dout[45]
    DIRECTION OUTPUT ;
    USE SIGNAL ;
    PORT
      LAYER M4 ;
        RECT  0 109.872 0.084 109.896 ;
    END
  END dout[45]
  PIN dout[46]
    DIRECTION OUTPUT ;
    USE SIGNAL ;
    PORT
      LAYER M4 ;
        RECT  0 110.448 0.084 110.472 ;
    END
  END dout[46]
  PIN dout[47]
    DIRECTION OUTPUT ;
    USE SIGNAL ;
    PORT
      LAYER M4 ;
        RECT  0 111.024 0.084 111.048 ;
    END
  END dout[47]
  PIN dout[48]
    DIRECTION OUTPUT ;
    USE SIGNAL ;
    PORT
      LAYER M4 ;
        RECT  0 111.6 0.084 111.624 ;
    END
  END dout[48]
  PIN dout[49]
    DIRECTION OUTPUT ;
    USE SIGNAL ;
    PORT
      LAYER M4 ;
        RECT  0 112.176 0.084 112.2 ;
    END
  END dout[49]
  PIN dout[4]
    DIRECTION OUTPUT ;
    USE SIGNAL ;
    PORT
      LAYER M4 ;
        RECT  0 86.544 0.084 86.568 ;
    END
  END dout[4]
  PIN dout[50]
    DIRECTION OUTPUT ;
    USE SIGNAL ;
    PORT
      LAYER M4 ;
        RECT  0 112.752 0.084 112.776 ;
    END
  END dout[50]
  PIN dout[51]
    DIRECTION OUTPUT ;
    USE SIGNAL ;
    PORT
      LAYER M4 ;
        RECT  0 113.328 0.084 113.352 ;
    END
  END dout[51]
  PIN dout[52]
    DIRECTION OUTPUT ;
    USE SIGNAL ;
    PORT
      LAYER M4 ;
        RECT  0 113.856 0.084 113.88 ;
    END
  END dout[52]
  PIN dout[53]
    DIRECTION OUTPUT ;
    USE SIGNAL ;
    PORT
      LAYER M4 ;
        RECT  0 114.432 0.084 114.456 ;
    END
  END dout[53]
  PIN dout[54]
    DIRECTION OUTPUT ;
    USE SIGNAL ;
    PORT
      LAYER M4 ;
        RECT  0 115.008 0.084 115.032 ;
    END
  END dout[54]
  PIN dout[55]
    DIRECTION OUTPUT ;
    USE SIGNAL ;
    PORT
      LAYER M4 ;
        RECT  0 115.584 0.084 115.608 ;
    END
  END dout[55]
  PIN dout[56]
    DIRECTION OUTPUT ;
    USE SIGNAL ;
    PORT
      LAYER M4 ;
        RECT  0 116.16 0.084 116.184 ;
    END
  END dout[56]
  PIN dout[57]
    DIRECTION OUTPUT ;
    USE SIGNAL ;
    PORT
      LAYER M4 ;
        RECT  0 116.736 0.084 116.76 ;
    END
  END dout[57]
  PIN dout[58]
    DIRECTION OUTPUT ;
    USE SIGNAL ;
    PORT
      LAYER M4 ;
        RECT  0 117.312 0.084 117.336 ;
    END
  END dout[58]
  PIN dout[59]
    DIRECTION OUTPUT ;
    USE SIGNAL ;
    PORT
      LAYER M4 ;
        RECT  0 117.888 0.084 117.912 ;
    END
  END dout[59]
  PIN dout[5]
    DIRECTION OUTPUT ;
    USE SIGNAL ;
    PORT
      LAYER M4 ;
        RECT  0 87.12 0.084 87.144 ;
    END
  END dout[5]
  PIN dout[60]
    DIRECTION OUTPUT ;
    USE SIGNAL ;
    PORT
      LAYER M4 ;
        RECT  0 118.416 0.084 118.44 ;
    END
  END dout[60]
  PIN dout[61]
    DIRECTION OUTPUT ;
    USE SIGNAL ;
    PORT
      LAYER M4 ;
        RECT  0 118.992 0.084 119.016 ;
    END
  END dout[61]
  PIN dout[62]
    DIRECTION OUTPUT ;
    USE SIGNAL ;
    PORT
      LAYER M4 ;
        RECT  0 119.568 0.084 119.592 ;
    END
  END dout[62]
  PIN dout[63]
    DIRECTION OUTPUT ;
    USE SIGNAL ;
    PORT
      LAYER M4 ;
        RECT  0 120.144 0.084 120.168 ;
    END
  END dout[63]
  PIN dout[64]
    DIRECTION OUTPUT ;
    USE SIGNAL ;
    PORT
      LAYER M4 ;
        RECT  0 120.72 0.084 120.744 ;
    END
  END dout[64]
  PIN dout[65]
    DIRECTION OUTPUT ;
    USE SIGNAL ;
    PORT
      LAYER M4 ;
        RECT  0 121.296 0.084 121.32 ;
    END
  END dout[65]
  PIN dout[66]
    DIRECTION OUTPUT ;
    USE SIGNAL ;
    PORT
      LAYER M4 ;
        RECT  0 121.872 0.084 121.896 ;
    END
  END dout[66]
  PIN dout[67]
    DIRECTION OUTPUT ;
    USE SIGNAL ;
    PORT
      LAYER M4 ;
        RECT  0 122.4 0.084 122.424 ;
    END
  END dout[67]
  PIN dout[68]
    DIRECTION OUTPUT ;
    USE SIGNAL ;
    PORT
      LAYER M4 ;
        RECT  0 122.976 0.084 123 ;
    END
  END dout[68]
  PIN dout[69]
    DIRECTION OUTPUT ;
    USE SIGNAL ;
    PORT
      LAYER M4 ;
        RECT  0 123.552 0.084 123.576 ;
    END
  END dout[69]
  PIN dout[6]
    DIRECTION OUTPUT ;
    USE SIGNAL ;
    PORT
      LAYER M4 ;
        RECT  0 87.696 0.084 87.72 ;
    END
  END dout[6]
  PIN dout[70]
    DIRECTION OUTPUT ;
    USE SIGNAL ;
    PORT
      LAYER M4 ;
        RECT  0 124.128 0.084 124.152 ;
    END
  END dout[70]
  PIN dout[71]
    DIRECTION OUTPUT ;
    USE SIGNAL ;
    PORT
      LAYER M4 ;
        RECT  0 124.704 0.084 124.728 ;
    END
  END dout[71]
  PIN dout[72]
    DIRECTION OUTPUT ;
    USE SIGNAL ;
    PORT
      LAYER M4 ;
        RECT  0 125.28 0.084 125.304 ;
    END
  END dout[72]
  PIN dout[73]
    DIRECTION OUTPUT ;
    USE SIGNAL ;
    PORT
      LAYER M4 ;
        RECT  0 125.856 0.084 125.88 ;
    END
  END dout[73]
  PIN dout[74]
    DIRECTION OUTPUT ;
    USE SIGNAL ;
    PORT
      LAYER M4 ;
        RECT  0 126.384 0.084 126.408 ;
    END
  END dout[74]
  PIN dout[75]
    DIRECTION OUTPUT ;
    USE SIGNAL ;
    PORT
      LAYER M4 ;
        RECT  0 126.96 0.084 126.984 ;
    END
  END dout[75]
  PIN dout[76]
    DIRECTION OUTPUT ;
    USE SIGNAL ;
    PORT
      LAYER M4 ;
        RECT  0 127.536 0.084 127.56 ;
    END
  END dout[76]
  PIN dout[77]
    DIRECTION OUTPUT ;
    USE SIGNAL ;
    PORT
      LAYER M4 ;
        RECT  0 128.112 0.084 128.136 ;
    END
  END dout[77]
  PIN dout[78]
    DIRECTION OUTPUT ;
    USE SIGNAL ;
    PORT
      LAYER M4 ;
        RECT  0 128.688 0.084 128.712 ;
    END
  END dout[78]
  PIN dout[79]
    DIRECTION OUTPUT ;
    USE SIGNAL ;
    PORT
      LAYER M4 ;
        RECT  0 129.264 0.084 129.288 ;
    END
  END dout[79]
  PIN dout[7]
    DIRECTION OUTPUT ;
    USE SIGNAL ;
    PORT
      LAYER M4 ;
        RECT  0 88.272 0.084 88.296 ;
    END
  END dout[7]
  PIN dout[80]
    DIRECTION OUTPUT ;
    USE SIGNAL ;
    PORT
      LAYER M4 ;
        RECT  0 129.84 0.084 129.864 ;
    END
  END dout[80]
  PIN dout[81]
    DIRECTION OUTPUT ;
    USE SIGNAL ;
    PORT
      LAYER M4 ;
        RECT  0 130.368 0.084 130.392 ;
    END
  END dout[81]
  PIN dout[82]
    DIRECTION OUTPUT ;
    USE SIGNAL ;
    PORT
      LAYER M4 ;
        RECT  0 130.944 0.084 130.968 ;
    END
  END dout[82]
  PIN dout[83]
    DIRECTION OUTPUT ;
    USE SIGNAL ;
    PORT
      LAYER M4 ;
        RECT  0 131.52 0.084 131.544 ;
    END
  END dout[83]
  PIN dout[84]
    DIRECTION OUTPUT ;
    USE SIGNAL ;
    PORT
      LAYER M4 ;
        RECT  0 132.096 0.084 132.12 ;
    END
  END dout[84]
  PIN dout[85]
    DIRECTION OUTPUT ;
    USE SIGNAL ;
    PORT
      LAYER M4 ;
        RECT  0 132.672 0.084 132.696 ;
    END
  END dout[85]
  PIN dout[86]
    DIRECTION OUTPUT ;
    USE SIGNAL ;
    PORT
      LAYER M4 ;
        RECT  0 133.248 0.084 133.272 ;
    END
  END dout[86]
  PIN dout[87]
    DIRECTION OUTPUT ;
    USE SIGNAL ;
    PORT
      LAYER M4 ;
        RECT  0 133.824 0.084 133.848 ;
    END
  END dout[87]
  PIN dout[88]
    DIRECTION OUTPUT ;
    USE SIGNAL ;
    PORT
      LAYER M4 ;
        RECT  0 134.352 0.084 134.376 ;
    END
  END dout[88]
  PIN dout[89]
    DIRECTION OUTPUT ;
    USE SIGNAL ;
    PORT
      LAYER M4 ;
        RECT  0 134.928 0.084 134.952 ;
    END
  END dout[89]
  PIN dout[8]
    DIRECTION OUTPUT ;
    USE SIGNAL ;
    PORT
      LAYER M4 ;
        RECT  0 88.848 0.084 88.872 ;
    END
  END dout[8]
  PIN dout[90]
    DIRECTION OUTPUT ;
    USE SIGNAL ;
    PORT
      LAYER M4 ;
        RECT  0 135.504 0.084 135.528 ;
    END
  END dout[90]
  PIN dout[91]
    DIRECTION OUTPUT ;
    USE SIGNAL ;
    PORT
      LAYER M4 ;
        RECT  0 136.08 0.084 136.104 ;
    END
  END dout[91]
  PIN dout[92]
    DIRECTION OUTPUT ;
    USE SIGNAL ;
    PORT
      LAYER M4 ;
        RECT  0 136.656 0.084 136.68 ;
    END
  END dout[92]
  PIN dout[93]
    DIRECTION OUTPUT ;
    USE SIGNAL ;
    PORT
      LAYER M4 ;
        RECT  0 137.232 0.084 137.256 ;
    END
  END dout[93]
  PIN dout[94]
    DIRECTION OUTPUT ;
    USE SIGNAL ;
    PORT
      LAYER M4 ;
        RECT  0 137.808 0.084 137.832 ;
    END
  END dout[94]
  PIN dout[95]
    DIRECTION OUTPUT ;
    USE SIGNAL ;
    PORT
      LAYER M4 ;
        RECT  0 138.384 0.084 138.408 ;
    END
  END dout[95]
  PIN dout[96]
    DIRECTION OUTPUT ;
    USE SIGNAL ;
    PORT
      LAYER M4 ;
        RECT  0 138.912 0.084 138.936 ;
    END
  END dout[96]
  PIN dout[97]
    DIRECTION OUTPUT ;
    USE SIGNAL ;
    PORT
      LAYER M4 ;
        RECT  0 139.488 0.084 139.512 ;
    END
  END dout[97]
  PIN dout[98]
    DIRECTION OUTPUT ;
    USE SIGNAL ;
    PORT
      LAYER M4 ;
        RECT  0 140.064 0.084 140.088 ;
    END
  END dout[98]
  PIN dout[99]
    DIRECTION OUTPUT ;
    USE SIGNAL ;
    PORT
      LAYER M4 ;
        RECT  0 140.64 0.084 140.664 ;
    END
  END dout[99]
  PIN dout[9]
    DIRECTION OUTPUT ;
    USE SIGNAL ;
    PORT
      LAYER M4 ;
        RECT  0 89.376 0.084 89.4 ;
    END
  END dout[9]
  PIN ra[0]
    DIRECTION INPUT ;
    USE SIGNAL ;
    PORT
      LAYER M4 ;
        RECT  0 169.056 0.084 169.08 ;
    END
  END ra[0]
  PIN ra[1]
    DIRECTION INPUT ;
    USE SIGNAL ;
    PORT
      LAYER M4 ;
        RECT  0 169.248 0.084 169.272 ;
    END
  END ra[1]
  PIN ra[2]
    DIRECTION INPUT ;
    USE SIGNAL ;
    PORT
      LAYER M4 ;
        RECT  0 169.392 0.084 169.416 ;
    END
  END ra[2]
  PIN ra[3]
    DIRECTION INPUT ;
    USE SIGNAL ;
    PORT
      LAYER M4 ;
        RECT  0 169.584 0.084 169.608 ;
    END
  END ra[3]
  PIN ra[4]
    DIRECTION INPUT ;
    USE SIGNAL ;
    PORT
      LAYER M4 ;
        RECT  0 169.728 0.084 169.752 ;
    END
  END ra[4]
  PIN ra[5]
    DIRECTION INPUT ;
    USE SIGNAL ;
    PORT
      LAYER M4 ;
        RECT  0 169.92 0.084 169.944 ;
    END
  END ra[5]
  PIN wa[0]
    DIRECTION INPUT ;
    USE SIGNAL ;
    PORT
      LAYER M4 ;
        RECT  0 166.08 0.084 166.104 ;
    END
  END wa[0]
  PIN wa[1]
    DIRECTION INPUT ;
    USE SIGNAL ;
    PORT
      LAYER M4 ;
        RECT  0 166.224 0.084 166.248 ;
    END
  END wa[1]
  PIN wa[2]
    DIRECTION INPUT ;
    USE SIGNAL ;
    PORT
      LAYER M4 ;
        RECT  0 166.416 0.084 166.44 ;
    END
  END wa[2]
  PIN wa[3]
    DIRECTION INPUT ;
    USE SIGNAL ;
    PORT
      LAYER M4 ;
        RECT  0 166.56 0.084 166.584 ;
    END
  END wa[3]
  PIN wa[4]
    DIRECTION INPUT ;
    USE SIGNAL ;
    PORT
      LAYER M4 ;
        RECT  0 166.752 0.084 166.776 ;
    END
  END wa[4]
  PIN wa[5]
    DIRECTION INPUT ;
    USE SIGNAL ;
    PORT
      LAYER M4 ;
        RECT  0 166.896 0.084 166.92 ;
    END
  END wa[5]
  PIN we
    DIRECTION INPUT ;
    USE SIGNAL ;
    PORT
      LAYER M4 ;
        RECT  0 3.504 0.084 3.528 ;
    END
    PORT
      LAYER M4 ;
        RECT  0.06 3.504 2.408 3.528 ;
    END
  END we
  PIN VDD
    DIRECTION INOUT ;
    USE POWER ;
    PORT
      LAYER M5 ;
        RECT  213.192 2.151 213.312 170.649 ;
        RECT  207.792 2.151 207.912 170.649 ;
        RECT  202.392 2.151 202.512 170.649 ;
        RECT  196.992 2.151 197.112 170.649 ;
        RECT  191.592 2.151 191.712 170.649 ;
        RECT  186.192 2.151 186.312 170.649 ;
        RECT  180.792 2.151 180.912 170.649 ;
        RECT  175.392 2.151 175.512 170.649 ;
        RECT  169.992 2.151 170.112 170.649 ;
        RECT  164.592 2.151 164.712 170.649 ;
        RECT  159.192 2.151 159.312 170.649 ;
        RECT  153.792 2.151 153.912 170.649 ;
        RECT  148.392 2.151 148.512 170.649 ;
        RECT  142.992 2.151 143.112 170.649 ;
        RECT  137.592 2.151 137.712 170.649 ;
        RECT  132.192 2.151 132.312 170.649 ;
        RECT  126.792 2.151 126.912 170.649 ;
        RECT  121.392 2.151 121.512 170.649 ;
        RECT  115.992 2.151 116.112 170.649 ;
        RECT  110.592 2.151 110.712 170.649 ;
        RECT  105.192 2.151 105.312 170.649 ;
        RECT  99.792 2.151 99.912 170.649 ;
        RECT  94.392 2.151 94.512 170.649 ;
        RECT  88.992 2.151 89.112 170.649 ;
        RECT  83.592 2.151 83.712 170.649 ;
        RECT  78.192 2.151 78.312 170.649 ;
        RECT  72.792 2.151 72.912 170.649 ;
        RECT  67.392 2.151 67.512 170.649 ;
        RECT  61.992 2.151 62.112 170.649 ;
        RECT  56.592 2.151 56.712 170.649 ;
        RECT  51.192 2.151 51.312 170.649 ;
        RECT  45.792 2.151 45.912 170.649 ;
        RECT  40.392 2.151 40.512 170.649 ;
        RECT  34.992 2.151 35.112 170.649 ;
        RECT  29.592 2.151 29.712 170.649 ;
        RECT  24.192 2.151 24.312 170.649 ;
        RECT  18.792 2.151 18.912 170.649 ;
        RECT  13.392 2.151 13.512 170.649 ;
        RECT  7.992 2.151 8.112 170.649 ;
        RECT  2.592 2.151 2.712 170.649 ;
    END
  END VDD
  PIN VSS
    DIRECTION INOUT ;
    USE GROUND ;
    PORT
      LAYER M5 ;
        RECT  213 2.137 213.12 170.663 ;
        RECT  207.6 2.137 207.72 170.663 ;
        RECT  202.2 2.137 202.32 170.663 ;
        RECT  196.8 2.137 196.92 170.663 ;
        RECT  191.4 2.137 191.52 170.663 ;
        RECT  186 2.137 186.12 170.663 ;
        RECT  180.6 2.137 180.72 170.663 ;
        RECT  175.2 2.137 175.32 170.663 ;
        RECT  169.8 2.137 169.92 170.663 ;
        RECT  164.4 2.137 164.52 170.663 ;
        RECT  159 2.137 159.12 170.663 ;
        RECT  153.6 2.137 153.72 170.663 ;
        RECT  148.2 2.137 148.32 170.663 ;
        RECT  142.8 2.137 142.92 170.663 ;
        RECT  137.4 2.137 137.52 170.663 ;
        RECT  132 2.137 132.12 170.663 ;
        RECT  126.6 2.137 126.72 170.663 ;
        RECT  121.2 2.137 121.32 170.663 ;
        RECT  115.8 2.137 115.92 170.663 ;
        RECT  110.4 2.137 110.52 170.663 ;
        RECT  105 2.137 105.12 170.663 ;
        RECT  99.6 2.137 99.72 170.663 ;
        RECT  94.2 2.137 94.32 170.663 ;
        RECT  88.8 2.137 88.92 170.663 ;
        RECT  83.4 2.137 83.52 170.663 ;
        RECT  78 2.137 78.12 170.663 ;
        RECT  72.6 2.137 72.72 170.663 ;
        RECT  67.2 2.137 67.32 170.663 ;
        RECT  61.8 2.137 61.92 170.663 ;
        RECT  56.4 2.137 56.52 170.663 ;
        RECT  51 2.137 51.12 170.663 ;
        RECT  45.6 2.137 45.72 170.663 ;
        RECT  40.2 2.137 40.32 170.663 ;
        RECT  34.8 2.137 34.92 170.663 ;
        RECT  29.4 2.137 29.52 170.663 ;
        RECT  24 2.137 24.12 170.663 ;
        RECT  18.6 2.137 18.72 170.663 ;
        RECT  13.2 2.137 13.32 170.663 ;
        RECT  7.8 2.137 7.92 170.663 ;
        RECT  2.4 2.137 2.52 170.663 ;
    END
  END VSS
  # OT_OBS_CLOSED layer=M5 d_um=1.536 added=64
  OBS
    LAYER RVTN ;
     RECT  2.16 2.16 213.84 2.295 ;
     RECT  2.16 2.565 213.84 2.835 ;
     RECT  2.16 3.105 213.84 3.375 ;
     RECT  2.16 3.645 213.84 3.915 ;
     RECT  2.16 4.185 213.84 4.455 ;
     RECT  2.16 4.725 213.84 4.995 ;
     RECT  2.16 5.265 213.84 5.535 ;
     RECT  2.16 5.805 213.84 6.075 ;
     RECT  2.16 6.345 213.84 6.615 ;
     RECT  2.16 6.885 213.84 7.155 ;
     RECT  2.16 7.425 213.84 7.695 ;
     RECT  2.16 7.965 213.84 8.235 ;
     RECT  2.16 8.505 213.84 8.775 ;
     RECT  2.16 9.045 213.84 9.315 ;
     RECT  2.16 9.585 213.84 9.855 ;
     RECT  2.16 10.125 213.84 10.395 ;
     RECT  2.16 10.665 213.84 10.935 ;
     RECT  2.16 11.205 213.84 11.475 ;
     RECT  2.16 11.745 213.84 12.015 ;
     RECT  2.16 12.285 213.84 12.555 ;
     RECT  2.16 12.825 213.84 13.095 ;
     RECT  2.16 13.365 213.84 13.635 ;
     RECT  2.16 13.905 213.84 14.175 ;
     RECT  2.16 14.445 213.84 14.715 ;
     RECT  2.16 14.985 213.84 15.255 ;
     RECT  2.16 15.525 213.84 15.795 ;
     RECT  2.16 16.065 213.84 16.335 ;
     RECT  2.16 16.605 213.84 16.875 ;
     RECT  2.16 17.145 213.84 17.415 ;
     RECT  2.16 17.685 213.84 17.955 ;
     RECT  2.16 18.225 213.84 18.495 ;
     RECT  2.16 18.765 213.84 19.035 ;
     RECT  2.16 19.305 213.84 19.575 ;
     RECT  2.16 19.845 213.84 20.115 ;
     RECT  2.16 20.385 213.84 20.655 ;
     RECT  2.16 20.925 213.84 21.195 ;
     RECT  2.16 21.465 213.84 21.735 ;
     RECT  2.16 22.005 213.84 22.275 ;
     RECT  2.16 22.545 213.84 22.815 ;
     RECT  2.16 23.085 213.84 23.355 ;
     RECT  2.16 23.625 213.84 23.895 ;
     RECT  2.16 24.165 213.84 24.435 ;
     RECT  2.16 24.705 213.84 24.975 ;
     RECT  2.16 25.245 213.84 25.515 ;
     RECT  2.16 25.785 213.84 26.055 ;
     RECT  2.16 26.325 213.84 26.595 ;
     RECT  2.16 26.865 213.84 27.135 ;
     RECT  2.16 27.405 213.84 27.675 ;
     RECT  2.16 27.945 213.84 28.215 ;
     RECT  2.16 28.485 213.84 28.755 ;
     RECT  2.16 29.025 213.84 29.295 ;
     RECT  2.16 29.565 213.84 29.835 ;
     RECT  2.16 30.105 213.84 30.375 ;
     RECT  2.16 30.645 213.84 30.915 ;
     RECT  2.16 31.185 213.84 31.455 ;
     RECT  2.16 31.725 213.84 31.995 ;
     RECT  2.16 32.265 213.84 32.535 ;
     RECT  2.16 32.805 213.84 33.075 ;
     RECT  2.16 33.345 213.84 33.615 ;
     RECT  2.16 33.885 213.84 34.155 ;
     RECT  2.16 34.425 213.84 34.695 ;
     RECT  2.16 34.965 213.84 35.235 ;
     RECT  2.16 35.505 213.84 35.775 ;
     RECT  2.16 36.045 213.84 36.315 ;
     RECT  2.16 36.585 213.84 36.855 ;
     RECT  2.16 37.125 213.84 37.395 ;
     RECT  2.16 37.665 213.84 37.935 ;
     RECT  2.16 38.205 213.84 38.475 ;
     RECT  2.16 38.745 213.84 39.015 ;
     RECT  2.16 39.285 213.84 39.555 ;
     RECT  2.16 39.825 213.84 40.095 ;
     RECT  2.16 40.365 213.84 40.635 ;
     RECT  2.16 40.905 213.84 41.04 ;
     RECT  2.16 41.04 20.412 41.175 ;
     RECT  195.804 41.04 213.84 41.175 ;
     RECT  2.16 41.445 20.412 41.715 ;
     RECT  195.804 41.445 213.84 41.715 ;
     RECT  2.16 41.985 20.412 42.255 ;
     RECT  195.804 41.985 213.84 42.255 ;
     RECT  2.16 42.525 20.412 42.795 ;
     RECT  195.804 42.525 213.84 42.795 ;
     RECT  2.16 43.065 20.412 43.335 ;
     RECT  195.804 43.065 213.84 43.335 ;
     RECT  2.16 43.605 20.412 43.875 ;
     RECT  195.804 43.605 213.84 43.875 ;
     RECT  2.16 44.145 20.412 44.415 ;
     RECT  195.804 44.145 213.84 44.415 ;
     RECT  2.16 44.685 20.412 44.955 ;
     RECT  195.804 44.685 213.84 44.955 ;
     RECT  2.16 45.225 20.412 45.495 ;
     RECT  195.804 45.225 213.84 45.495 ;
     RECT  2.16 45.765 20.412 46.035 ;
     RECT  195.804 45.765 213.84 46.035 ;
     RECT  2.16 46.305 20.412 46.575 ;
     RECT  195.804 46.305 213.84 46.575 ;
     RECT  2.16 46.845 20.412 47.115 ;
     RECT  195.804 46.845 213.84 47.115 ;
     RECT  2.16 47.385 20.412 47.655 ;
     RECT  195.804 47.385 213.84 47.655 ;
     RECT  2.16 47.925 20.412 48.195 ;
     RECT  195.804 47.925 213.84 48.195 ;
     RECT  2.16 48.465 20.412 48.735 ;
     RECT  195.804 48.465 213.84 48.735 ;
     RECT  2.16 49.005 20.412 49.275 ;
     RECT  195.804 49.005 213.84 49.275 ;
     RECT  2.16 49.545 20.412 49.815 ;
     RECT  195.804 49.545 213.84 49.815 ;
     RECT  2.16 50.085 20.412 50.355 ;
     RECT  195.804 50.085 213.84 50.355 ;
     RECT  2.16 50.625 20.412 50.895 ;
     RECT  195.804 50.625 213.84 50.895 ;
     RECT  2.16 51.165 20.412 51.435 ;
     RECT  195.804 51.165 213.84 51.435 ;
     RECT  2.16 51.705 20.412 51.975 ;
     RECT  195.804 51.705 213.84 51.975 ;
     RECT  2.16 52.245 20.412 52.515 ;
     RECT  195.804 52.245 213.84 52.515 ;
     RECT  2.16 52.785 20.412 53.055 ;
     RECT  195.804 52.785 213.84 53.055 ;
     RECT  2.16 53.325 20.412 53.595 ;
     RECT  195.804 53.325 213.84 53.595 ;
     RECT  2.16 53.865 20.412 54.135 ;
     RECT  195.804 53.865 213.84 54.135 ;
     RECT  2.16 54.405 20.412 54.675 ;
     RECT  195.804 54.405 213.84 54.675 ;
     RECT  2.16 54.945 20.412 55.215 ;
     RECT  195.804 54.945 213.84 55.215 ;
     RECT  2.16 55.485 20.412 55.755 ;
     RECT  195.804 55.485 213.84 55.755 ;
     RECT  2.16 56.025 20.412 56.295 ;
     RECT  195.804 56.025 213.84 56.295 ;
     RECT  2.16 56.565 20.412 56.835 ;
     RECT  195.804 56.565 213.84 56.835 ;
     RECT  2.16 57.105 20.412 57.375 ;
     RECT  195.804 57.105 213.84 57.375 ;
     RECT  2.16 57.645 20.412 57.915 ;
     RECT  195.804 57.645 213.84 57.915 ;
     RECT  2.16 58.185 20.412 58.455 ;
     RECT  195.804 58.185 213.84 58.455 ;
     RECT  2.16 58.725 20.412 58.995 ;
     RECT  195.804 58.725 213.84 58.995 ;
     RECT  2.16 59.265 20.412 59.535 ;
     RECT  195.804 59.265 213.84 59.535 ;
     RECT  2.16 59.805 20.412 60.075 ;
     RECT  195.804 59.805 213.84 60.075 ;
     RECT  2.16 60.345 20.412 60.615 ;
     RECT  195.804 60.345 213.84 60.615 ;
     RECT  2.16 60.885 20.412 61.155 ;
     RECT  195.804 60.885 213.84 61.155 ;
     RECT  2.16 61.425 20.412 61.695 ;
     RECT  195.804 61.425 213.84 61.695 ;
     RECT  2.16 61.965 20.412 62.235 ;
     RECT  195.804 61.965 213.84 62.235 ;
     RECT  2.16 62.505 20.412 62.775 ;
     RECT  195.804 62.505 213.84 62.775 ;
     RECT  2.16 63.045 20.412 63.315 ;
     RECT  195.804 63.045 213.84 63.315 ;
     RECT  2.16 63.585 20.412 63.855 ;
     RECT  195.804 63.585 213.84 63.855 ;
     RECT  2.16 64.125 20.412 64.395 ;
     RECT  195.804 64.125 213.84 64.395 ;
     RECT  2.16 64.665 20.412 64.935 ;
     RECT  195.804 64.665 213.84 64.935 ;
     RECT  2.16 65.205 20.412 65.475 ;
     RECT  195.804 65.205 213.84 65.475 ;
     RECT  2.16 65.745 20.412 66.015 ;
     RECT  195.804 65.745 213.84 66.015 ;
     RECT  2.16 66.285 20.412 66.555 ;
     RECT  195.804 66.285 213.84 66.555 ;
     RECT  2.16 66.825 20.412 67.095 ;
     RECT  195.804 66.825 213.84 67.095 ;
     RECT  2.16 67.365 20.412 67.635 ;
     RECT  195.804 67.365 213.84 67.635 ;
     RECT  2.16 67.905 20.412 68.175 ;
     RECT  195.804 67.905 213.84 68.175 ;
     RECT  2.16 68.445 20.412 68.715 ;
     RECT  195.804 68.445 213.84 68.715 ;
     RECT  2.16 68.985 20.412 69.255 ;
     RECT  195.804 68.985 213.84 69.255 ;
     RECT  2.16 69.525 20.412 69.795 ;
     RECT  195.804 69.525 213.84 69.795 ;
     RECT  2.16 70.065 20.412 70.335 ;
     RECT  195.804 70.065 213.84 70.335 ;
     RECT  2.16 70.605 20.412 70.875 ;
     RECT  195.804 70.605 213.84 70.875 ;
     RECT  2.16 71.145 20.412 71.415 ;
     RECT  195.804 71.145 213.84 71.415 ;
     RECT  2.16 71.685 20.412 71.955 ;
     RECT  195.804 71.685 213.84 71.955 ;
     RECT  2.16 72.225 20.412 72.495 ;
     RECT  195.804 72.225 213.84 72.495 ;
     RECT  2.16 72.765 20.412 73.035 ;
     RECT  195.804 72.765 213.84 73.035 ;
     RECT  2.16 73.305 20.412 73.575 ;
     RECT  195.804 73.305 213.84 73.575 ;
     RECT  2.16 73.845 20.412 74.115 ;
     RECT  195.804 73.845 213.84 74.115 ;
     RECT  2.16 74.385 20.412 74.655 ;
     RECT  195.804 74.385 213.84 74.655 ;
     RECT  2.16 74.925 20.412 75.195 ;
     RECT  195.804 74.925 213.84 75.195 ;
     RECT  2.16 75.465 20.412 75.735 ;
     RECT  195.804 75.465 213.84 75.735 ;
     RECT  2.16 76.005 20.412 76.275 ;
     RECT  195.804 76.005 213.84 76.275 ;
     RECT  2.16 76.545 20.412 76.815 ;
     RECT  195.804 76.545 213.84 76.815 ;
     RECT  2.16 77.085 20.412 77.355 ;
     RECT  195.804 77.085 213.84 77.355 ;
     RECT  2.16 77.625 20.412 77.895 ;
     RECT  195.804 77.625 213.84 77.895 ;
     RECT  2.16 78.165 20.412 78.435 ;
     RECT  195.804 78.165 213.84 78.435 ;
     RECT  2.16 78.705 20.412 78.975 ;
     RECT  195.804 78.705 213.84 78.975 ;
     RECT  2.16 79.245 20.412 79.515 ;
     RECT  195.804 79.245 213.84 79.515 ;
     RECT  2.16 79.785 20.412 80.055 ;
     RECT  195.804 79.785 213.84 80.055 ;
     RECT  2.16 80.325 20.412 80.595 ;
     RECT  195.804 80.325 213.84 80.595 ;
     RECT  2.16 80.865 20.412 81.135 ;
     RECT  195.804 80.865 213.84 81.135 ;
     RECT  2.16 81.405 20.412 81.675 ;
     RECT  195.804 81.405 213.84 81.675 ;
     RECT  2.16 81.945 20.412 82.215 ;
     RECT  195.804 81.945 213.84 82.215 ;
     RECT  2.16 82.485 20.412 82.755 ;
     RECT  195.804 82.485 213.84 82.755 ;
     RECT  2.16 83.025 20.412 83.295 ;
     RECT  195.804 83.025 213.84 83.295 ;
     RECT  2.16 83.565 20.412 83.835 ;
     RECT  195.804 83.565 213.84 83.835 ;
     RECT  2.16 84.105 20.412 84.375 ;
     RECT  195.804 84.105 213.84 84.375 ;
     RECT  2.16 84.645 20.412 84.915 ;
     RECT  195.804 84.645 213.84 84.915 ;
     RECT  2.16 85.185 20.412 85.455 ;
     RECT  195.804 85.185 213.84 85.455 ;
     RECT  2.16 85.725 20.412 85.995 ;
     RECT  195.804 85.725 213.84 85.995 ;
     RECT  2.16 86.265 20.412 86.535 ;
     RECT  195.804 86.265 213.84 86.535 ;
     RECT  2.16 86.805 20.412 87.075 ;
     RECT  195.804 86.805 213.84 87.075 ;
     RECT  2.16 87.345 20.412 87.615 ;
     RECT  195.804 87.345 213.84 87.615 ;
     RECT  2.16 87.885 20.412 88.155 ;
     RECT  195.804 87.885 213.84 88.155 ;
     RECT  2.16 88.425 20.412 88.695 ;
     RECT  195.804 88.425 213.84 88.695 ;
     RECT  2.16 88.965 20.412 89.235 ;
     RECT  195.804 88.965 213.84 89.235 ;
     RECT  2.16 89.505 20.412 89.775 ;
     RECT  195.804 89.505 213.84 89.775 ;
     RECT  2.16 90.045 20.412 90.315 ;
     RECT  195.804 90.045 213.84 90.315 ;
     RECT  2.16 90.585 20.412 90.855 ;
     RECT  195.804 90.585 213.84 90.855 ;
     RECT  2.16 91.125 20.412 91.395 ;
     RECT  195.804 91.125 213.84 91.395 ;
     RECT  2.16 91.665 20.412 91.935 ;
     RECT  195.804 91.665 213.84 91.935 ;
     RECT  2.16 92.205 20.412 92.475 ;
     RECT  195.804 92.205 213.84 92.475 ;
     RECT  2.16 92.745 20.412 93.015 ;
     RECT  195.804 92.745 213.84 93.015 ;
     RECT  2.16 93.285 20.412 93.555 ;
     RECT  195.804 93.285 213.84 93.555 ;
     RECT  2.16 93.825 20.412 94.095 ;
     RECT  195.804 93.825 213.84 94.095 ;
     RECT  2.16 94.365 20.412 94.635 ;
     RECT  195.804 94.365 213.84 94.635 ;
     RECT  2.16 94.905 20.412 95.175 ;
     RECT  195.804 94.905 213.84 95.175 ;
     RECT  2.16 95.445 20.412 95.715 ;
     RECT  195.804 95.445 213.84 95.715 ;
     RECT  2.16 95.985 20.412 96.255 ;
     RECT  195.804 95.985 213.84 96.255 ;
     RECT  2.16 96.525 20.412 96.795 ;
     RECT  195.804 96.525 213.84 96.795 ;
     RECT  2.16 97.065 20.412 97.335 ;
     RECT  195.804 97.065 213.84 97.335 ;
     RECT  2.16 97.605 20.412 97.875 ;
     RECT  195.804 97.605 213.84 97.875 ;
     RECT  2.16 98.145 20.412 98.415 ;
     RECT  195.804 98.145 213.84 98.415 ;
     RECT  2.16 98.685 20.412 98.955 ;
     RECT  195.804 98.685 213.84 98.955 ;
     RECT  2.16 99.225 20.412 99.495 ;
     RECT  195.804 99.225 213.84 99.495 ;
     RECT  2.16 99.765 20.412 100.035 ;
     RECT  195.804 99.765 213.84 100.035 ;
     RECT  2.16 100.305 20.412 100.575 ;
     RECT  195.804 100.305 213.84 100.575 ;
     RECT  2.16 100.845 20.412 101.115 ;
     RECT  195.804 100.845 213.84 101.115 ;
     RECT  2.16 101.385 20.412 101.655 ;
     RECT  195.804 101.385 213.84 101.655 ;
     RECT  2.16 101.925 20.412 102.195 ;
     RECT  195.804 101.925 213.84 102.195 ;
     RECT  2.16 102.465 20.412 102.735 ;
     RECT  195.804 102.465 213.84 102.735 ;
     RECT  2.16 103.005 20.412 103.275 ;
     RECT  195.804 103.005 213.84 103.275 ;
     RECT  2.16 103.545 20.412 103.815 ;
     RECT  195.804 103.545 213.84 103.815 ;
     RECT  2.16 104.085 20.412 104.355 ;
     RECT  195.804 104.085 213.84 104.355 ;
     RECT  2.16 104.625 20.412 104.895 ;
     RECT  195.804 104.625 213.84 104.895 ;
     RECT  2.16 105.165 20.412 105.435 ;
     RECT  195.804 105.165 213.84 105.435 ;
     RECT  2.16 105.705 20.412 105.975 ;
     RECT  195.804 105.705 213.84 105.975 ;
     RECT  2.16 106.245 20.412 106.515 ;
     RECT  195.804 106.245 213.84 106.515 ;
     RECT  2.16 106.785 20.412 107.055 ;
     RECT  195.804 106.785 213.84 107.055 ;
     RECT  2.16 107.325 20.412 107.595 ;
     RECT  195.804 107.325 213.84 107.595 ;
     RECT  2.16 107.865 20.412 108.135 ;
     RECT  195.804 107.865 213.84 108.135 ;
     RECT  2.16 108.405 20.412 108.675 ;
     RECT  195.804 108.405 213.84 108.675 ;
     RECT  2.16 108.945 20.412 109.215 ;
     RECT  195.804 108.945 213.84 109.215 ;
     RECT  2.16 109.485 20.412 109.755 ;
     RECT  195.804 109.485 213.84 109.755 ;
     RECT  2.16 110.025 20.412 110.295 ;
     RECT  195.804 110.025 213.84 110.295 ;
     RECT  2.16 110.565 20.412 110.835 ;
     RECT  195.804 110.565 213.84 110.835 ;
     RECT  2.16 111.105 20.412 111.375 ;
     RECT  195.804 111.105 213.84 111.375 ;
     RECT  2.16 111.645 20.412 111.915 ;
     RECT  195.804 111.645 213.84 111.915 ;
     RECT  2.16 112.185 20.412 112.455 ;
     RECT  195.804 112.185 213.84 112.455 ;
     RECT  2.16 112.725 20.412 112.995 ;
     RECT  195.804 112.725 213.84 112.995 ;
     RECT  2.16 113.265 20.412 113.535 ;
     RECT  195.804 113.265 213.84 113.535 ;
     RECT  2.16 113.805 20.412 114.075 ;
     RECT  195.804 113.805 213.84 114.075 ;
     RECT  2.16 114.345 20.412 114.615 ;
     RECT  195.804 114.345 213.84 114.615 ;
     RECT  2.16 114.885 20.412 115.155 ;
     RECT  195.804 114.885 213.84 115.155 ;
     RECT  2.16 115.425 20.412 115.695 ;
     RECT  195.804 115.425 213.84 115.695 ;
     RECT  2.16 115.965 20.412 116.235 ;
     RECT  195.804 115.965 213.84 116.235 ;
     RECT  2.16 116.505 20.412 116.775 ;
     RECT  195.804 116.505 213.84 116.775 ;
     RECT  2.16 117.045 20.412 117.315 ;
     RECT  195.804 117.045 213.84 117.315 ;
     RECT  2.16 117.585 20.412 117.855 ;
     RECT  195.804 117.585 213.84 117.855 ;
     RECT  2.16 118.125 20.412 118.395 ;
     RECT  195.804 118.125 213.84 118.395 ;
     RECT  2.16 118.665 20.412 118.935 ;
     RECT  195.804 118.665 213.84 118.935 ;
     RECT  2.16 119.205 20.412 119.475 ;
     RECT  195.804 119.205 213.84 119.475 ;
     RECT  2.16 119.745 20.412 120.015 ;
     RECT  195.804 119.745 213.84 120.015 ;
     RECT  2.16 120.285 20.412 120.555 ;
     RECT  195.804 120.285 213.84 120.555 ;
     RECT  2.16 120.825 20.412 121.095 ;
     RECT  195.804 120.825 213.84 121.095 ;
     RECT  2.16 121.365 20.412 121.635 ;
     RECT  195.804 121.365 213.84 121.635 ;
     RECT  2.16 121.905 20.412 122.175 ;
     RECT  195.804 121.905 213.84 122.175 ;
     RECT  2.16 122.445 20.412 122.715 ;
     RECT  195.804 122.445 213.84 122.715 ;
     RECT  2.16 122.985 20.412 123.12 ;
     RECT  195.804 122.985 213.84 123.12 ;
     RECT  2.16 123.12 213.84 123.255 ;
     RECT  2.16 123.525 213.84 123.795 ;
     RECT  2.16 124.065 213.84 124.335 ;
     RECT  2.16 124.605 213.84 124.875 ;
     RECT  2.16 125.145 213.84 125.415 ;
     RECT  2.16 125.685 213.84 125.955 ;
     RECT  2.16 126.225 213.84 126.495 ;
     RECT  2.16 126.765 213.84 127.035 ;
     RECT  2.16 127.305 213.84 127.575 ;
     RECT  2.16 127.845 213.84 128.115 ;
     RECT  2.16 128.385 213.84 128.655 ;
     RECT  2.16 128.925 213.84 129.195 ;
     RECT  2.16 129.465 213.84 129.735 ;
     RECT  2.16 130.005 213.84 130.275 ;
     RECT  2.16 130.545 213.84 130.815 ;
     RECT  2.16 131.085 213.84 131.355 ;
     RECT  2.16 131.625 213.84 131.895 ;
     RECT  2.16 132.165 213.84 132.435 ;
     RECT  2.16 132.705 213.84 132.975 ;
     RECT  2.16 133.245 213.84 133.515 ;
     RECT  2.16 133.785 213.84 134.055 ;
     RECT  2.16 134.325 213.84 134.595 ;
     RECT  2.16 134.865 213.84 135.135 ;
     RECT  2.16 135.405 213.84 135.675 ;
     RECT  2.16 135.945 213.84 136.215 ;
     RECT  2.16 136.485 213.84 136.755 ;
     RECT  2.16 137.025 213.84 137.295 ;
     RECT  2.16 137.565 213.84 137.835 ;
     RECT  2.16 138.105 213.84 138.375 ;
     RECT  2.16 138.645 213.84 138.915 ;
     RECT  2.16 139.185 213.84 139.455 ;
     RECT  2.16 139.725 213.84 139.995 ;
     RECT  2.16 140.265 213.84 140.535 ;
     RECT  2.16 140.805 213.84 141.075 ;
     RECT  2.16 141.345 213.84 141.615 ;
     RECT  2.16 141.885 213.84 142.155 ;
     RECT  2.16 142.425 213.84 142.695 ;
     RECT  2.16 142.965 213.84 143.235 ;
     RECT  2.16 143.505 213.84 143.775 ;
     RECT  2.16 144.045 213.84 144.315 ;
     RECT  2.16 144.585 213.84 144.855 ;
     RECT  2.16 145.125 213.84 145.395 ;
     RECT  2.16 145.665 213.84 145.935 ;
     RECT  2.16 146.205 213.84 146.475 ;
     RECT  2.16 146.745 213.84 147.015 ;
     RECT  2.16 147.285 213.84 147.555 ;
     RECT  2.16 147.825 213.84 148.095 ;
     RECT  2.16 148.365 213.84 148.635 ;
     RECT  2.16 148.905 213.84 149.175 ;
     RECT  2.16 149.445 213.84 149.715 ;
     RECT  2.16 149.985 213.84 150.255 ;
     RECT  2.16 150.525 213.84 150.795 ;
     RECT  2.16 151.065 213.84 151.335 ;
     RECT  2.16 151.605 213.84 151.875 ;
     RECT  2.16 152.145 213.84 152.415 ;
     RECT  2.16 152.685 213.84 152.955 ;
     RECT  2.16 153.225 213.84 153.495 ;
     RECT  2.16 153.765 213.84 154.035 ;
     RECT  2.16 154.305 213.84 154.575 ;
     RECT  2.16 154.845 213.84 155.115 ;
     RECT  2.16 155.385 213.84 155.655 ;
     RECT  2.16 155.925 213.84 156.195 ;
     RECT  2.16 156.465 213.84 156.735 ;
     RECT  2.16 157.005 213.84 157.275 ;
     RECT  2.16 157.545 213.84 157.815 ;
     RECT  2.16 158.085 213.84 158.355 ;
     RECT  2.16 158.625 213.84 158.895 ;
     RECT  2.16 159.165 213.84 159.435 ;
     RECT  2.16 159.705 213.84 159.975 ;
     RECT  2.16 160.245 213.84 160.515 ;
     RECT  2.16 160.785 213.84 161.055 ;
     RECT  2.16 161.325 213.84 161.595 ;
     RECT  2.16 161.865 213.84 162.135 ;
     RECT  2.16 162.405 213.84 162.675 ;
     RECT  2.16 162.945 213.84 163.215 ;
     RECT  2.16 163.485 213.84 163.755 ;
     RECT  2.16 164.025 213.84 164.295 ;
     RECT  2.16 164.565 213.84 164.835 ;
     RECT  2.16 165.105 213.84 165.375 ;
     RECT  2.16 165.645 213.84 165.915 ;
     RECT  2.16 166.185 213.84 166.455 ;
     RECT  2.16 166.725 213.84 166.995 ;
     RECT  2.16 167.265 213.84 167.535 ;
     RECT  2.16 167.805 213.84 168.075 ;
     RECT  2.16 168.345 213.84 168.615 ;
     RECT  2.16 168.885 213.84 169.155 ;
     RECT  2.16 169.425 213.84 169.695 ;
     RECT  2.16 169.965 213.84 170.235 ;
     RECT  2.16 170.505 213.84 170.64 ;
    LAYER RVTP ;
     RECT  2.16 2.295 213.84 2.565 ;
     RECT  2.16 2.835 213.84 3.105 ;
     RECT  2.16 3.375 213.84 3.645 ;
     RECT  2.16 3.915 213.84 4.185 ;
     RECT  2.16 4.455 213.84 4.725 ;
     RECT  2.16 4.995 213.84 5.265 ;
     RECT  2.16 5.535 213.84 5.805 ;
     RECT  2.16 6.075 213.84 6.345 ;
     RECT  2.16 6.615 213.84 6.885 ;
     RECT  2.16 7.155 213.84 7.425 ;
     RECT  2.16 7.695 213.84 7.965 ;
     RECT  2.16 8.235 213.84 8.505 ;
     RECT  2.16 8.775 213.84 9.045 ;
     RECT  2.16 9.315 213.84 9.585 ;
     RECT  2.16 9.855 213.84 10.125 ;
     RECT  2.16 10.395 213.84 10.665 ;
     RECT  2.16 10.935 213.84 11.205 ;
     RECT  2.16 11.475 213.84 11.745 ;
     RECT  2.16 12.015 213.84 12.285 ;
     RECT  2.16 12.555 213.84 12.825 ;
     RECT  2.16 13.095 213.84 13.365 ;
     RECT  2.16 13.635 213.84 13.905 ;
     RECT  2.16 14.175 213.84 14.445 ;
     RECT  2.16 14.715 213.84 14.985 ;
     RECT  2.16 15.255 213.84 15.525 ;
     RECT  2.16 15.795 213.84 16.065 ;
     RECT  2.16 16.335 213.84 16.605 ;
     RECT  2.16 16.875 213.84 17.145 ;
     RECT  2.16 17.415 213.84 17.685 ;
     RECT  2.16 17.955 213.84 18.225 ;
     RECT  2.16 18.495 213.84 18.765 ;
     RECT  2.16 19.035 213.84 19.305 ;
     RECT  2.16 19.575 213.84 19.845 ;
     RECT  2.16 20.115 213.84 20.385 ;
     RECT  2.16 20.655 213.84 20.925 ;
     RECT  2.16 21.195 213.84 21.465 ;
     RECT  2.16 21.735 213.84 22.005 ;
     RECT  2.16 22.275 213.84 22.545 ;
     RECT  2.16 22.815 213.84 23.085 ;
     RECT  2.16 23.355 213.84 23.625 ;
     RECT  2.16 23.895 213.84 24.165 ;
     RECT  2.16 24.435 213.84 24.705 ;
     RECT  2.16 24.975 213.84 25.245 ;
     RECT  2.16 25.515 213.84 25.785 ;
     RECT  2.16 26.055 213.84 26.325 ;
     RECT  2.16 26.595 213.84 26.865 ;
     RECT  2.16 27.135 213.84 27.405 ;
     RECT  2.16 27.675 213.84 27.945 ;
     RECT  2.16 28.215 213.84 28.485 ;
     RECT  2.16 28.755 213.84 29.025 ;
     RECT  2.16 29.295 213.84 29.565 ;
     RECT  2.16 29.835 213.84 30.105 ;
     RECT  2.16 30.375 213.84 30.645 ;
     RECT  2.16 30.915 213.84 31.185 ;
     RECT  2.16 31.455 213.84 31.725 ;
     RECT  2.16 31.995 213.84 32.265 ;
     RECT  2.16 32.535 213.84 32.805 ;
     RECT  2.16 33.075 213.84 33.345 ;
     RECT  2.16 33.615 213.84 33.885 ;
     RECT  2.16 34.155 213.84 34.425 ;
     RECT  2.16 34.695 213.84 34.965 ;
     RECT  2.16 35.235 213.84 35.505 ;
     RECT  2.16 35.775 213.84 36.045 ;
     RECT  2.16 36.315 213.84 36.585 ;
     RECT  2.16 36.855 213.84 37.125 ;
     RECT  2.16 37.395 213.84 37.665 ;
     RECT  2.16 37.935 213.84 38.205 ;
     RECT  2.16 38.475 213.84 38.745 ;
     RECT  2.16 39.015 213.84 39.285 ;
     RECT  2.16 39.555 213.84 39.825 ;
     RECT  2.16 40.095 213.84 40.365 ;
     RECT  2.16 40.635 213.84 40.905 ;
     RECT  2.16 41.175 20.412 41.445 ;
     RECT  195.804 41.175 213.84 41.445 ;
     RECT  2.16 41.715 20.412 41.985 ;
     RECT  195.804 41.715 213.84 41.985 ;
     RECT  2.16 42.255 20.412 42.525 ;
     RECT  195.804 42.255 213.84 42.525 ;
     RECT  2.16 42.795 20.412 43.065 ;
     RECT  195.804 42.795 213.84 43.065 ;
     RECT  2.16 43.335 20.412 43.605 ;
     RECT  195.804 43.335 213.84 43.605 ;
     RECT  2.16 43.875 20.412 44.145 ;
     RECT  195.804 43.875 213.84 44.145 ;
     RECT  2.16 44.415 20.412 44.685 ;
     RECT  195.804 44.415 213.84 44.685 ;
     RECT  2.16 44.955 20.412 45.225 ;
     RECT  195.804 44.955 213.84 45.225 ;
     RECT  2.16 45.495 20.412 45.765 ;
     RECT  195.804 45.495 213.84 45.765 ;
     RECT  2.16 46.035 20.412 46.305 ;
     RECT  195.804 46.035 213.84 46.305 ;
     RECT  2.16 46.575 20.412 46.845 ;
     RECT  195.804 46.575 213.84 46.845 ;
     RECT  2.16 47.115 20.412 47.385 ;
     RECT  195.804 47.115 213.84 47.385 ;
     RECT  2.16 47.655 20.412 47.925 ;
     RECT  195.804 47.655 213.84 47.925 ;
     RECT  2.16 48.195 20.412 48.465 ;
     RECT  195.804 48.195 213.84 48.465 ;
     RECT  2.16 48.735 20.412 49.005 ;
     RECT  195.804 48.735 213.84 49.005 ;
     RECT  2.16 49.275 20.412 49.545 ;
     RECT  195.804 49.275 213.84 49.545 ;
     RECT  2.16 49.815 20.412 50.085 ;
     RECT  195.804 49.815 213.84 50.085 ;
     RECT  2.16 50.355 20.412 50.625 ;
     RECT  195.804 50.355 213.84 50.625 ;
     RECT  2.16 50.895 20.412 51.165 ;
     RECT  195.804 50.895 213.84 51.165 ;
     RECT  2.16 51.435 20.412 51.705 ;
     RECT  195.804 51.435 213.84 51.705 ;
     RECT  2.16 51.975 20.412 52.245 ;
     RECT  195.804 51.975 213.84 52.245 ;
     RECT  2.16 52.515 20.412 52.785 ;
     RECT  195.804 52.515 213.84 52.785 ;
     RECT  2.16 53.055 20.412 53.325 ;
     RECT  195.804 53.055 213.84 53.325 ;
     RECT  2.16 53.595 20.412 53.865 ;
     RECT  195.804 53.595 213.84 53.865 ;
     RECT  2.16 54.135 20.412 54.405 ;
     RECT  195.804 54.135 213.84 54.405 ;
     RECT  2.16 54.675 20.412 54.945 ;
     RECT  195.804 54.675 213.84 54.945 ;
     RECT  2.16 55.215 20.412 55.485 ;
     RECT  195.804 55.215 213.84 55.485 ;
     RECT  2.16 55.755 20.412 56.025 ;
     RECT  195.804 55.755 213.84 56.025 ;
     RECT  2.16 56.295 20.412 56.565 ;
     RECT  195.804 56.295 213.84 56.565 ;
     RECT  2.16 56.835 20.412 57.105 ;
     RECT  195.804 56.835 213.84 57.105 ;
     RECT  2.16 57.375 20.412 57.645 ;
     RECT  195.804 57.375 213.84 57.645 ;
     RECT  2.16 57.915 20.412 58.185 ;
     RECT  195.804 57.915 213.84 58.185 ;
     RECT  2.16 58.455 20.412 58.725 ;
     RECT  195.804 58.455 213.84 58.725 ;
     RECT  2.16 58.995 20.412 59.265 ;
     RECT  195.804 58.995 213.84 59.265 ;
     RECT  2.16 59.535 20.412 59.805 ;
     RECT  195.804 59.535 213.84 59.805 ;
     RECT  2.16 60.075 20.412 60.345 ;
     RECT  195.804 60.075 213.84 60.345 ;
     RECT  2.16 60.615 20.412 60.885 ;
     RECT  195.804 60.615 213.84 60.885 ;
     RECT  2.16 61.155 20.412 61.425 ;
     RECT  195.804 61.155 213.84 61.425 ;
     RECT  2.16 61.695 20.412 61.965 ;
     RECT  195.804 61.695 213.84 61.965 ;
     RECT  2.16 62.235 20.412 62.505 ;
     RECT  195.804 62.235 213.84 62.505 ;
     RECT  2.16 62.775 20.412 63.045 ;
     RECT  195.804 62.775 213.84 63.045 ;
     RECT  2.16 63.315 20.412 63.585 ;
     RECT  195.804 63.315 213.84 63.585 ;
     RECT  2.16 63.855 20.412 64.125 ;
     RECT  195.804 63.855 213.84 64.125 ;
     RECT  2.16 64.395 20.412 64.665 ;
     RECT  195.804 64.395 213.84 64.665 ;
     RECT  2.16 64.935 20.412 65.205 ;
     RECT  195.804 64.935 213.84 65.205 ;
     RECT  2.16 65.475 20.412 65.745 ;
     RECT  195.804 65.475 213.84 65.745 ;
     RECT  2.16 66.015 20.412 66.285 ;
     RECT  195.804 66.015 213.84 66.285 ;
     RECT  2.16 66.555 20.412 66.825 ;
     RECT  195.804 66.555 213.84 66.825 ;
     RECT  2.16 67.095 20.412 67.365 ;
     RECT  195.804 67.095 213.84 67.365 ;
     RECT  2.16 67.635 20.412 67.905 ;
     RECT  195.804 67.635 213.84 67.905 ;
     RECT  2.16 68.175 20.412 68.445 ;
     RECT  195.804 68.175 213.84 68.445 ;
     RECT  2.16 68.715 20.412 68.985 ;
     RECT  195.804 68.715 213.84 68.985 ;
     RECT  2.16 69.255 20.412 69.525 ;
     RECT  195.804 69.255 213.84 69.525 ;
     RECT  2.16 69.795 20.412 70.065 ;
     RECT  195.804 69.795 213.84 70.065 ;
     RECT  2.16 70.335 20.412 70.605 ;
     RECT  195.804 70.335 213.84 70.605 ;
     RECT  2.16 70.875 20.412 71.145 ;
     RECT  195.804 70.875 213.84 71.145 ;
     RECT  2.16 71.415 20.412 71.685 ;
     RECT  195.804 71.415 213.84 71.685 ;
     RECT  2.16 71.955 20.412 72.225 ;
     RECT  195.804 71.955 213.84 72.225 ;
     RECT  2.16 72.495 20.412 72.765 ;
     RECT  195.804 72.495 213.84 72.765 ;
     RECT  2.16 73.035 20.412 73.305 ;
     RECT  195.804 73.035 213.84 73.305 ;
     RECT  2.16 73.575 20.412 73.845 ;
     RECT  195.804 73.575 213.84 73.845 ;
     RECT  2.16 74.115 20.412 74.385 ;
     RECT  195.804 74.115 213.84 74.385 ;
     RECT  2.16 74.655 20.412 74.925 ;
     RECT  195.804 74.655 213.84 74.925 ;
     RECT  2.16 75.195 20.412 75.465 ;
     RECT  195.804 75.195 213.84 75.465 ;
     RECT  2.16 75.735 20.412 76.005 ;
     RECT  195.804 75.735 213.84 76.005 ;
     RECT  2.16 76.275 20.412 76.545 ;
     RECT  195.804 76.275 213.84 76.545 ;
     RECT  2.16 76.815 20.412 77.085 ;
     RECT  195.804 76.815 213.84 77.085 ;
     RECT  2.16 77.355 20.412 77.625 ;
     RECT  195.804 77.355 213.84 77.625 ;
     RECT  2.16 77.895 20.412 78.165 ;
     RECT  195.804 77.895 213.84 78.165 ;
     RECT  2.16 78.435 20.412 78.705 ;
     RECT  195.804 78.435 213.84 78.705 ;
     RECT  2.16 78.975 20.412 79.245 ;
     RECT  195.804 78.975 213.84 79.245 ;
     RECT  2.16 79.515 20.412 79.785 ;
     RECT  195.804 79.515 213.84 79.785 ;
     RECT  2.16 80.055 20.412 80.325 ;
     RECT  195.804 80.055 213.84 80.325 ;
     RECT  2.16 80.595 20.412 80.865 ;
     RECT  195.804 80.595 213.84 80.865 ;
     RECT  2.16 81.135 20.412 81.405 ;
     RECT  195.804 81.135 213.84 81.405 ;
     RECT  2.16 81.675 20.412 81.945 ;
     RECT  195.804 81.675 213.84 81.945 ;
     RECT  2.16 82.215 20.412 82.485 ;
     RECT  195.804 82.215 213.84 82.485 ;
     RECT  2.16 82.755 20.412 83.025 ;
     RECT  195.804 82.755 213.84 83.025 ;
     RECT  2.16 83.295 20.412 83.565 ;
     RECT  195.804 83.295 213.84 83.565 ;
     RECT  2.16 83.835 20.412 84.105 ;
     RECT  195.804 83.835 213.84 84.105 ;
     RECT  2.16 84.375 20.412 84.645 ;
     RECT  195.804 84.375 213.84 84.645 ;
     RECT  2.16 84.915 20.412 85.185 ;
     RECT  195.804 84.915 213.84 85.185 ;
     RECT  2.16 85.455 20.412 85.725 ;
     RECT  195.804 85.455 213.84 85.725 ;
     RECT  2.16 85.995 20.412 86.265 ;
     RECT  195.804 85.995 213.84 86.265 ;
     RECT  2.16 86.535 20.412 86.805 ;
     RECT  195.804 86.535 213.84 86.805 ;
     RECT  2.16 87.075 20.412 87.345 ;
     RECT  195.804 87.075 213.84 87.345 ;
     RECT  2.16 87.615 20.412 87.885 ;
     RECT  195.804 87.615 213.84 87.885 ;
     RECT  2.16 88.155 20.412 88.425 ;
     RECT  195.804 88.155 213.84 88.425 ;
     RECT  2.16 88.695 20.412 88.965 ;
     RECT  195.804 88.695 213.84 88.965 ;
     RECT  2.16 89.235 20.412 89.505 ;
     RECT  195.804 89.235 213.84 89.505 ;
     RECT  2.16 89.775 20.412 90.045 ;
     RECT  195.804 89.775 213.84 90.045 ;
     RECT  2.16 90.315 20.412 90.585 ;
     RECT  195.804 90.315 213.84 90.585 ;
     RECT  2.16 90.855 20.412 91.125 ;
     RECT  195.804 90.855 213.84 91.125 ;
     RECT  2.16 91.395 20.412 91.665 ;
     RECT  195.804 91.395 213.84 91.665 ;
     RECT  2.16 91.935 20.412 92.205 ;
     RECT  195.804 91.935 213.84 92.205 ;
     RECT  2.16 92.475 20.412 92.745 ;
     RECT  195.804 92.475 213.84 92.745 ;
     RECT  2.16 93.015 20.412 93.285 ;
     RECT  195.804 93.015 213.84 93.285 ;
     RECT  2.16 93.555 20.412 93.825 ;
     RECT  195.804 93.555 213.84 93.825 ;
     RECT  2.16 94.095 20.412 94.365 ;
     RECT  195.804 94.095 213.84 94.365 ;
     RECT  2.16 94.635 20.412 94.905 ;
     RECT  195.804 94.635 213.84 94.905 ;
     RECT  2.16 95.175 20.412 95.445 ;
     RECT  195.804 95.175 213.84 95.445 ;
     RECT  2.16 95.715 20.412 95.985 ;
     RECT  195.804 95.715 213.84 95.985 ;
     RECT  2.16 96.255 20.412 96.525 ;
     RECT  195.804 96.255 213.84 96.525 ;
     RECT  2.16 96.795 20.412 97.065 ;
     RECT  195.804 96.795 213.84 97.065 ;
     RECT  2.16 97.335 20.412 97.605 ;
     RECT  195.804 97.335 213.84 97.605 ;
     RECT  2.16 97.875 20.412 98.145 ;
     RECT  195.804 97.875 213.84 98.145 ;
     RECT  2.16 98.415 20.412 98.685 ;
     RECT  195.804 98.415 213.84 98.685 ;
     RECT  2.16 98.955 20.412 99.225 ;
     RECT  195.804 98.955 213.84 99.225 ;
     RECT  2.16 99.495 20.412 99.765 ;
     RECT  195.804 99.495 213.84 99.765 ;
     RECT  2.16 100.035 20.412 100.305 ;
     RECT  195.804 100.035 213.84 100.305 ;
     RECT  2.16 100.575 20.412 100.845 ;
     RECT  195.804 100.575 213.84 100.845 ;
     RECT  2.16 101.115 20.412 101.385 ;
     RECT  195.804 101.115 213.84 101.385 ;
     RECT  2.16 101.655 20.412 101.925 ;
     RECT  195.804 101.655 213.84 101.925 ;
     RECT  2.16 102.195 20.412 102.465 ;
     RECT  195.804 102.195 213.84 102.465 ;
     RECT  2.16 102.735 20.412 103.005 ;
     RECT  195.804 102.735 213.84 103.005 ;
     RECT  2.16 103.275 20.412 103.545 ;
     RECT  195.804 103.275 213.84 103.545 ;
     RECT  2.16 103.815 20.412 104.085 ;
     RECT  195.804 103.815 213.84 104.085 ;
     RECT  2.16 104.355 20.412 104.625 ;
     RECT  195.804 104.355 213.84 104.625 ;
     RECT  2.16 104.895 20.412 105.165 ;
     RECT  195.804 104.895 213.84 105.165 ;
     RECT  2.16 105.435 20.412 105.705 ;
     RECT  195.804 105.435 213.84 105.705 ;
     RECT  2.16 105.975 20.412 106.245 ;
     RECT  195.804 105.975 213.84 106.245 ;
     RECT  2.16 106.515 20.412 106.785 ;
     RECT  195.804 106.515 213.84 106.785 ;
     RECT  2.16 107.055 20.412 107.325 ;
     RECT  195.804 107.055 213.84 107.325 ;
     RECT  2.16 107.595 20.412 107.865 ;
     RECT  195.804 107.595 213.84 107.865 ;
     RECT  2.16 108.135 20.412 108.405 ;
     RECT  195.804 108.135 213.84 108.405 ;
     RECT  2.16 108.675 20.412 108.945 ;
     RECT  195.804 108.675 213.84 108.945 ;
     RECT  2.16 109.215 20.412 109.485 ;
     RECT  195.804 109.215 213.84 109.485 ;
     RECT  2.16 109.755 20.412 110.025 ;
     RECT  195.804 109.755 213.84 110.025 ;
     RECT  2.16 110.295 20.412 110.565 ;
     RECT  195.804 110.295 213.84 110.565 ;
     RECT  2.16 110.835 20.412 111.105 ;
     RECT  195.804 110.835 213.84 111.105 ;
     RECT  2.16 111.375 20.412 111.645 ;
     RECT  195.804 111.375 213.84 111.645 ;
     RECT  2.16 111.915 20.412 112.185 ;
     RECT  195.804 111.915 213.84 112.185 ;
     RECT  2.16 112.455 20.412 112.725 ;
     RECT  195.804 112.455 213.84 112.725 ;
     RECT  2.16 112.995 20.412 113.265 ;
     RECT  195.804 112.995 213.84 113.265 ;
     RECT  2.16 113.535 20.412 113.805 ;
     RECT  195.804 113.535 213.84 113.805 ;
     RECT  2.16 114.075 20.412 114.345 ;
     RECT  195.804 114.075 213.84 114.345 ;
     RECT  2.16 114.615 20.412 114.885 ;
     RECT  195.804 114.615 213.84 114.885 ;
     RECT  2.16 115.155 20.412 115.425 ;
     RECT  195.804 115.155 213.84 115.425 ;
     RECT  2.16 115.695 20.412 115.965 ;
     RECT  195.804 115.695 213.84 115.965 ;
     RECT  2.16 116.235 20.412 116.505 ;
     RECT  195.804 116.235 213.84 116.505 ;
     RECT  2.16 116.775 20.412 117.045 ;
     RECT  195.804 116.775 213.84 117.045 ;
     RECT  2.16 117.315 20.412 117.585 ;
     RECT  195.804 117.315 213.84 117.585 ;
     RECT  2.16 117.855 20.412 118.125 ;
     RECT  195.804 117.855 213.84 118.125 ;
     RECT  2.16 118.395 20.412 118.665 ;
     RECT  195.804 118.395 213.84 118.665 ;
     RECT  2.16 118.935 20.412 119.205 ;
     RECT  195.804 118.935 213.84 119.205 ;
     RECT  2.16 119.475 20.412 119.745 ;
     RECT  195.804 119.475 213.84 119.745 ;
     RECT  2.16 120.015 20.412 120.285 ;
     RECT  195.804 120.015 213.84 120.285 ;
     RECT  2.16 120.555 20.412 120.825 ;
     RECT  195.804 120.555 213.84 120.825 ;
     RECT  2.16 121.095 20.412 121.365 ;
     RECT  195.804 121.095 213.84 121.365 ;
     RECT  2.16 121.635 20.412 121.905 ;
     RECT  195.804 121.635 213.84 121.905 ;
     RECT  2.16 122.175 20.412 122.445 ;
     RECT  195.804 122.175 213.84 122.445 ;
     RECT  2.16 122.715 20.412 122.985 ;
     RECT  195.804 122.715 213.84 122.985 ;
     RECT  2.16 123.255 213.84 123.525 ;
     RECT  2.16 123.795 213.84 124.065 ;
     RECT  2.16 124.335 213.84 124.605 ;
     RECT  2.16 124.875 213.84 125.145 ;
     RECT  2.16 125.415 213.84 125.685 ;
     RECT  2.16 125.955 213.84 126.225 ;
     RECT  2.16 126.495 213.84 126.765 ;
     RECT  2.16 127.035 213.84 127.305 ;
     RECT  2.16 127.575 213.84 127.845 ;
     RECT  2.16 128.115 213.84 128.385 ;
     RECT  2.16 128.655 213.84 128.925 ;
     RECT  2.16 129.195 213.84 129.465 ;
     RECT  2.16 129.735 213.84 130.005 ;
     RECT  2.16 130.275 213.84 130.545 ;
     RECT  2.16 130.815 213.84 131.085 ;
     RECT  2.16 131.355 213.84 131.625 ;
     RECT  2.16 131.895 213.84 132.165 ;
     RECT  2.16 132.435 213.84 132.705 ;
     RECT  2.16 132.975 213.84 133.245 ;
     RECT  2.16 133.515 213.84 133.785 ;
     RECT  2.16 134.055 213.84 134.325 ;
     RECT  2.16 134.595 213.84 134.865 ;
     RECT  2.16 135.135 213.84 135.405 ;
     RECT  2.16 135.675 213.84 135.945 ;
     RECT  2.16 136.215 213.84 136.485 ;
     RECT  2.16 136.755 213.84 137.025 ;
     RECT  2.16 137.295 213.84 137.565 ;
     RECT  2.16 137.835 213.84 138.105 ;
     RECT  2.16 138.375 213.84 138.645 ;
     RECT  2.16 138.915 213.84 139.185 ;
     RECT  2.16 139.455 213.84 139.725 ;
     RECT  2.16 139.995 213.84 140.265 ;
     RECT  2.16 140.535 213.84 140.805 ;
     RECT  2.16 141.075 213.84 141.345 ;
     RECT  2.16 141.615 213.84 141.885 ;
     RECT  2.16 142.155 213.84 142.425 ;
     RECT  2.16 142.695 213.84 142.965 ;
     RECT  2.16 143.235 213.84 143.505 ;
     RECT  2.16 143.775 213.84 144.045 ;
     RECT  2.16 144.315 213.84 144.585 ;
     RECT  2.16 144.855 213.84 145.125 ;
     RECT  2.16 145.395 213.84 145.665 ;
     RECT  2.16 145.935 213.84 146.205 ;
     RECT  2.16 146.475 213.84 146.745 ;
     RECT  2.16 147.015 213.84 147.285 ;
     RECT  2.16 147.555 213.84 147.825 ;
     RECT  2.16 148.095 213.84 148.365 ;
     RECT  2.16 148.635 213.84 148.905 ;
     RECT  2.16 149.175 213.84 149.445 ;
     RECT  2.16 149.715 213.84 149.985 ;
     RECT  2.16 150.255 213.84 150.525 ;
     RECT  2.16 150.795 213.84 151.065 ;
     RECT  2.16 151.335 213.84 151.605 ;
     RECT  2.16 151.875 213.84 152.145 ;
     RECT  2.16 152.415 213.84 152.685 ;
     RECT  2.16 152.955 213.84 153.225 ;
     RECT  2.16 153.495 213.84 153.765 ;
     RECT  2.16 154.035 213.84 154.305 ;
     RECT  2.16 154.575 213.84 154.845 ;
     RECT  2.16 155.115 213.84 155.385 ;
     RECT  2.16 155.655 213.84 155.925 ;
     RECT  2.16 156.195 213.84 156.465 ;
     RECT  2.16 156.735 213.84 157.005 ;
     RECT  2.16 157.275 213.84 157.545 ;
     RECT  2.16 157.815 213.84 158.085 ;
     RECT  2.16 158.355 213.84 158.625 ;
     RECT  2.16 158.895 213.84 159.165 ;
     RECT  2.16 159.435 213.84 159.705 ;
     RECT  2.16 159.975 213.84 160.245 ;
     RECT  2.16 160.515 213.84 160.785 ;
     RECT  2.16 161.055 213.84 161.325 ;
     RECT  2.16 161.595 213.84 161.865 ;
     RECT  2.16 162.135 213.84 162.405 ;
     RECT  2.16 162.675 213.84 162.945 ;
     RECT  2.16 163.215 213.84 163.485 ;
     RECT  2.16 163.755 213.84 164.025 ;
     RECT  2.16 164.295 213.84 164.565 ;
     RECT  2.16 164.835 213.84 165.105 ;
     RECT  2.16 165.375 213.84 165.645 ;
     RECT  2.16 165.915 213.84 166.185 ;
     RECT  2.16 166.455 213.84 166.725 ;
     RECT  2.16 166.995 213.84 167.265 ;
     RECT  2.16 167.535 213.84 167.805 ;
     RECT  2.16 168.075 213.84 168.345 ;
     RECT  2.16 168.615 213.84 168.885 ;
     RECT  2.16 169.155 213.84 169.425 ;
     RECT  2.16 169.695 213.84 169.965 ;
     RECT  2.16 170.235 213.84 170.505 ;
    LAYER M1 ;
     RECT  2.16 2.151 213.84 41.049 ;
     RECT  22.464 43.2 193.752 120.984 ;
     RECT  2.16 41.049 20.412 123.111 ;
     RECT  195.804 41.049 213.84 123.111 ;
     RECT  2.16 123.111 213.84 170.649 ;
    LAYER M2 ;
     RECT  0.103 90.486 0.139 90.504 ;
     RECT  0.103 112.806 0.139 113.364 ;
     RECT  0.103 114.426 0.139 116.154 ;
     RECT  0.103 119.016 0.139 121.284 ;
     RECT  0.103 129.276 0.139 131.544 ;
     RECT  0.103 140.076 0.139 142.344 ;
     RECT  0.103 145.206 0.139 145.224 ;
     RECT  0.103 146.376 0.139 146.394 ;
     RECT  0.103 156.006 0.139 157.104 ;
     RECT  0.103 37.602 0.535 39.24 ;
     RECT  0.103 40.032 0.535 40.59 ;
     RECT  0.103 84.186 0.535 86.022 ;
     RECT  0.103 87.156 0.535 87.714 ;
     RECT  0.103 88.776 0.535 89.424 ;
     RECT  0.103 93.366 0.535 96.282 ;
     RECT  0.103 97.416 0.535 100.224 ;
     RECT  0.103 103.086 0.535 103.644 ;
     RECT  0.103 104.706 0.535 106.434 ;
     RECT  0.103 108.756 0.535 108.774 ;
     RECT  0.103 109.836 0.535 111.024 ;
     RECT  0.139 112.806 0.535 116.154 ;
     RECT  0.103 117.396 0.535 117.954 ;
     RECT  0.139 119.016 0.535 121.932 ;
     RECT  0.103 122.994 0.535 123.012 ;
     RECT  0.103 124.146 0.535 126.954 ;
     RECT  0.139 133.866 0.535 133.884 ;
     RECT  0.103 134.946 0.535 136.044 ;
     RECT  0.103 137.196 0.535 137.214 ;
     RECT  0.103 138.456 0.535 138.474 ;
     RECT  0.139 139.536 0.535 142.344 ;
     RECT  0.139 144.666 0.535 146.394 ;
     RECT  0.103 147.456 0.535 147.474 ;
     RECT  0.139 155.466 0.535 157.104 ;
     RECT  0.103 160.596 0.535 160.614 ;
     RECT  0.103 15.732 1.723 17.37 ;
     RECT  0.103 61.902 1.723 63 ;
     RECT  0.103 8.28 2.16 9.27 ;
     RECT  0.103 10.062 2.16 10.08 ;
     RECT  0.103 11.718 2.16 13.86 ;
     RECT  0.103 14.652 2.16 14.67 ;
     RECT  1.723 15.732 2.16 17.676 ;
     RECT  0.103 18.702 2.16 20.61 ;
     RECT  0.103 21.402 2.16 21.69 ;
     RECT  0.103 22.752 2.16 22.77 ;
     RECT  0.103 23.634 2.16 24.12 ;
     RECT  0.103 24.912 2.16 25.2 ;
     RECT  0.103 26.604 2.16 28.17 ;
     RECT  0.103 28.962 2.16 29.25 ;
     RECT  0.103 30.15 2.16 30.6 ;
     RECT  0.103 31.662 2.16 32.76 ;
     RECT  0.103 34.632 2.16 35.19 ;
     RECT  0.103 36.252 2.16 36.54 ;
     RECT  0.535 37.602 2.16 40.59 ;
     RECT  0.103 42.732 2.16 44.64 ;
     RECT  0.103 45.468 2.16 45.486 ;
     RECT  0.103 46.512 2.16 46.53 ;
     RECT  0.103 47.592 2.16 47.61 ;
     RECT  0.103 48.438 2.16 48.456 ;
     RECT  0.103 49.482 2.16 51.93 ;
     RECT  0.103 52.992 2.16 55.44 ;
     RECT  0.103 56.232 2.16 56.25 ;
     RECT  0.103 57.348 2.16 60.03 ;
     RECT  0.103 60.858 2.16 60.876 ;
     RECT  1.723 61.902 2.16 63.27 ;
     RECT  0.103 64.062 2.16 67.32 ;
     RECT  0.103 68.382 2.16 71.37 ;
     RECT  0.535 73.242 2.16 73.26 ;
     RECT  0.103 74.052 2.16 75.42 ;
     RECT  0.535 84.186 2.16 89.424 ;
     RECT  0.139 90.486 2.16 91.152 ;
     RECT  0.535 92.826 2.16 100.224 ;
     RECT  0.535 102.006 2.16 107.694 ;
     RECT  0.535 108.756 2.16 116.154 ;
     RECT  0.535 117.396 2.16 127.674 ;
     RECT  0.139 128.736 2.16 131.544 ;
     RECT  0.535 132.786 2.16 132.804 ;
     RECT  0.535 133.866 2.16 143.064 ;
     RECT  0.535 144.126 2.16 148.122 ;
     RECT  0.103 149.256 2.16 151.974 ;
     RECT  0.535 153.234 2.16 161.694 ;
     RECT  0.103 169.2 2.16 169.218 ;
     RECT  2.16 2.151 20.412 170.649 ;
     RECT  20.412 84.114 20.435 84.438 ;
     RECT  20.412 102.276 20.435 102.42 ;
     RECT  20.412 62.316 20.471 62.334 ;
     RECT  20.412 65.826 20.471 66.384 ;
     RECT  20.412 63.558 20.507 63.576 ;
     RECT  20.471 65.826 20.507 65.844 ;
     RECT  20.412 94.878 20.795 95.472 ;
     RECT  20.412 103.284 20.795 103.536 ;
     RECT  20.412 90.9 20.831 92.034 ;
     RECT  20.412 79.488 20.867 79.506 ;
     RECT  20.795 103.518 20.867 103.536 ;
     RECT  20.412 72.396 20.903 73.224 ;
     RECT  20.412 104.364 20.939 111.906 ;
     RECT  20.939 105.642 20.975 111.906 ;
     RECT  20.412 113.202 21.011 114.066 ;
     RECT  20.412 43.236 21.083 57.06 ;
     RECT  20.975 105.642 21.083 105.732 ;
     RECT  20.975 106.488 21.083 111.906 ;
     RECT  20.412 119.016 21.119 119.034 ;
     RECT  20.412 114.894 21.155 116.064 ;
     RECT  21.155 115.362 21.227 116.064 ;
     RECT  20.435 102.276 21.371 102.294 ;
     RECT  20.939 104.364 21.371 104.724 ;
     RECT  20.412 81.756 21.407 81.774 ;
     RECT  20.412 86.778 21.407 86.904 ;
     RECT  21.083 43.236 21.443 56.934 ;
     RECT  20.795 95.454 21.443 95.472 ;
     RECT  21.371 104.598 21.443 104.724 ;
     RECT  20.412 85.194 21.479 85.212 ;
     RECT  21.083 106.488 21.479 106.506 ;
     RECT  20.831 90.936 21.515 92.034 ;
     RECT  21.011 113.778 21.515 114.066 ;
     RECT  20.435 84.42 21.551 84.438 ;
     RECT  21.515 90.936 21.587 91.494 ;
     RECT  21.443 43.236 21.623 56.754 ;
     RECT  20.903 72.504 21.623 73.224 ;
     RECT  21.623 43.236 21.659 56.52 ;
     RECT  20.412 67.536 21.659 68.706 ;
     RECT  21.623 72.576 21.659 73.224 ;
     RECT  21.083 107.298 21.659 111.906 ;
     RECT  21.659 47.664 21.695 50.418 ;
     RECT  21.659 108.108 21.695 111.906 ;
     RECT  21.227 116.046 21.695 116.064 ;
     RECT  21.659 43.236 21.731 46.098 ;
     RECT  21.659 52.326 21.731 54.702 ;
     RECT  21.659 56.106 21.731 56.124 ;
     RECT  21.695 108.108 21.731 111.672 ;
     RECT  21.659 107.298 21.991 107.316 ;
     RECT  21.731 43.236 22.464 44.784 ;
     RECT  21.731 45.54 22.464 45.792 ;
     RECT  21.695 47.664 22.464 50.148 ;
     RECT  21.731 52.326 22.464 52.344 ;
     RECT  21.731 53.496 22.464 54.702 ;
     RECT  20.412 64.674 22.464 64.692 ;
     RECT  21.659 67.536 22.464 67.554 ;
     RECT  21.659 68.688 22.464 68.706 ;
     RECT  21.659 72.576 22.464 72.594 ;
     RECT  21.407 86.778 22.464 86.796 ;
     RECT  21.587 90.936 22.464 90.954 ;
     RECT  21.443 104.706 22.464 104.724 ;
     RECT  21.083 105.714 22.464 105.732 ;
     RECT  21.991 106.596 22.464 107.316 ;
     RECT  21.731 108.108 22.464 110.664 ;
     RECT  21.731 111.654 22.464 111.672 ;
     RECT  21.515 113.778 22.464 113.796 ;
     RECT  20.412 120.024 22.464 120.276 ;
     RECT  22.464 43.2 193.752 120.984 ;
     RECT  193.752 43.2 194.359 43.254 ;
     RECT  193.752 53.496 194.755 53.964 ;
     RECT  193.752 55.152 194.755 55.242 ;
     RECT  194.719 57.42 194.755 57.438 ;
     RECT  194.755 57.42 194.791 57.906 ;
     RECT  193.752 87.696 194.791 87.714 ;
     RECT  194.791 44.766 194.827 44.784 ;
     RECT  193.752 47.862 194.827 50.04 ;
     RECT  193.752 51.102 194.827 51.264 ;
     RECT  194.791 57.42 194.827 58.014 ;
     RECT  193.752 59.238 194.827 60.372 ;
     RECT  193.752 64.296 194.827 64.314 ;
     RECT  193.752 72.936 194.827 73.53 ;
     RECT  193.752 75.006 194.827 75.024 ;
     RECT  194.791 87.696 194.827 88.11 ;
     RECT  193.752 89.316 194.827 89.334 ;
     RECT  193.752 103.086 194.827 103.104 ;
     RECT  193.752 104.166 194.827 104.886 ;
     RECT  193.752 109.296 194.827 110.016 ;
     RECT  193.752 111.042 194.827 112.14 ;
     RECT  194.791 115.056 194.827 115.074 ;
     RECT  194.359 43.146 194.863 43.254 ;
     RECT  194.827 44.766 194.863 45.018 ;
     RECT  194.827 47.862 194.863 51.264 ;
     RECT  193.752 52.182 194.863 52.344 ;
     RECT  194.755 53.496 194.863 55.242 ;
     RECT  193.752 56.646 194.863 56.664 ;
     RECT  194.827 57.42 194.863 60.372 ;
     RECT  194.827 63.666 194.863 64.314 ;
     RECT  193.752 71.154 194.863 71.784 ;
     RECT  194.827 72.738 194.863 75.024 ;
     RECT  193.752 77.166 194.863 77.184 ;
     RECT  193.752 79.182 194.863 81.972 ;
     RECT  193.752 83.772 194.863 85.95 ;
     RECT  194.827 87.696 194.863 89.874 ;
     RECT  193.752 90.936 194.863 90.954 ;
     RECT  194.827 93.834 194.863 94.194 ;
     RECT  193.752 95.112 194.863 96.21 ;
     RECT  193.752 99.162 194.863 101.412 ;
     RECT  194.827 103.086 194.863 104.886 ;
     RECT  194.827 106.416 194.863 106.434 ;
     RECT  193.752 108.486 194.863 108.504 ;
     RECT  194.827 109.296 194.863 112.14 ;
     RECT  193.752 113.202 194.863 113.904 ;
     RECT  194.827 115.056 194.863 115.524 ;
     RECT  194.863 43.146 194.899 43.794 ;
     RECT  194.863 44.766 194.899 46.026 ;
     RECT  194.863 47.664 194.899 60.372 ;
     RECT  194.863 62.586 194.899 62.604 ;
     RECT  194.863 63.666 194.899 64.854 ;
     RECT  193.752 68.346 194.899 70.092 ;
     RECT  194.863 71.154 194.899 77.184 ;
     RECT  194.863 78.516 194.899 81.972 ;
     RECT  194.863 83.034 194.899 85.95 ;
     RECT  194.863 87.696 194.899 92.664 ;
     RECT  194.863 93.834 194.899 96.714 ;
     RECT  194.863 98.964 194.899 101.412 ;
     RECT  194.863 103.086 194.899 106.434 ;
     RECT  194.863 108.486 194.899 116.154 ;
     RECT  194.899 43.146 194.935 60.372 ;
     RECT  194.899 62.586 194.935 97.938 ;
     RECT  194.899 98.964 194.935 116.226 ;
     RECT  20.412 2.151 195.804 41.049 ;
     RECT  194.935 43.146 195.804 116.46 ;
     RECT  194.899 117.36 195.804 117.378 ;
     RECT  194.935 118.836 195.804 119.394 ;
     RECT  194.359 120.996 195.804 121.014 ;
     RECT  20.412 123.111 195.804 170.649 ;
     RECT  195.804 2.151 213.84 170.649 ;
    LAYER M3 ;
     RECT  2.415 2.143 2.505 2.413 ;
     RECT  7.815 2.143 7.905 2.413 ;
     RECT  13.215 2.143 13.305 2.413 ;
     RECT  18.615 2.143 18.705 2.413 ;
     RECT  24.015 2.143 24.105 2.413 ;
     RECT  29.415 2.143 29.505 2.413 ;
     RECT  34.815 2.143 34.905 2.413 ;
     RECT  40.215 2.143 40.305 2.413 ;
     RECT  45.615 2.143 45.705 2.413 ;
     RECT  51.015 2.143 51.105 2.413 ;
     RECT  56.415 2.143 56.505 2.413 ;
     RECT  61.815 2.143 61.905 2.413 ;
     RECT  67.215 2.143 67.305 2.413 ;
     RECT  72.615 2.143 72.705 2.413 ;
     RECT  78.015 2.143 78.105 2.413 ;
     RECT  83.415 2.143 83.505 2.413 ;
     RECT  88.815 2.143 88.905 2.413 ;
     RECT  94.215 2.143 94.305 2.413 ;
     RECT  99.615 2.143 99.705 2.413 ;
     RECT  105.015 2.143 105.105 2.413 ;
     RECT  110.415 2.143 110.505 2.413 ;
     RECT  115.815 2.143 115.905 2.413 ;
     RECT  121.215 2.143 121.305 2.413 ;
     RECT  126.615 2.143 126.705 2.413 ;
     RECT  132.015 2.143 132.105 2.413 ;
     RECT  137.415 2.143 137.505 2.413 ;
     RECT  142.815 2.143 142.905 2.413 ;
     RECT  148.215 2.143 148.305 2.413 ;
     RECT  153.615 2.143 153.705 2.413 ;
     RECT  159.015 2.143 159.105 2.413 ;
     RECT  164.415 2.143 164.505 2.413 ;
     RECT  169.815 2.143 169.905 2.413 ;
     RECT  175.215 2.143 175.305 2.413 ;
     RECT  180.615 2.143 180.705 2.413 ;
     RECT  186.015 2.143 186.105 2.413 ;
     RECT  191.415 2.143 191.505 2.413 ;
     RECT  196.815 2.143 196.905 2.413 ;
     RECT  202.215 2.143 202.305 2.413 ;
     RECT  207.615 2.143 207.705 2.413 ;
     RECT  213.015 2.143 213.105 2.413 ;
     RECT  2.415 2.413 2.697 3.499 ;
     RECT  7.815 2.413 8.097 3.721 ;
     RECT  3.456 3.721 3.618 3.839 ;
     RECT  2.304 3.499 2.697 3.875 ;
     RECT  2.415 3.875 2.697 4.225 ;
     RECT  3.456 3.839 3.474 4.225 ;
     RECT  2.415 4.225 3.474 4.379 ;
     RECT  2.415 4.379 3.294 4.415 ;
     RECT  3.996 8.395 4.014 8.435 ;
     RECT  2.415 4.415 2.898 8.581 ;
     RECT  4.14 8.581 4.158 8.815 ;
     RECT  5.076 8.509 5.094 8.815 ;
     RECT  4.14 8.815 5.094 8.851 ;
     RECT  4.14 8.851 5.778 8.969 ;
     RECT  2.415 8.581 2.934 9.005 ;
     RECT  4.284 8.969 5.778 9.005 ;
     RECT  4.788 9.005 5.778 9.067 ;
     RECT  4.788 9.067 5.886 9.101 ;
     RECT  7.164 3.721 8.097 9.661 ;
     RECT  0.108 8.251 0.126 10.085 ;
     RECT  4.824 9.101 5.886 10.165 ;
     RECT  6.804 9.661 8.097 10.165 ;
     RECT  4.824 10.165 8.097 10.201 ;
     RECT  2.415 9.005 2.898 10.219 ;
     RECT  2.304 10.219 2.898 10.315 ;
     RECT  4.536 10.201 8.097 10.319 ;
     RECT  4.536 10.319 5.778 10.355 ;
     RECT  2.304 10.315 3.294 10.471 ;
     RECT  9.972 10.201 9.99 10.561 ;
     RECT  2.304 10.471 4.194 10.589 ;
     RECT  6.804 10.319 8.097 10.589 ;
     RECT  2.304 10.589 3.15 10.625 ;
     RECT  2.304 10.625 2.898 10.895 ;
     RECT  7.164 10.589 8.097 11.129 ;
     RECT  4.104 10.589 4.194 11.165 ;
     RECT  5.076 10.355 5.778 11.281 ;
     RECT  4.968 11.281 5.922 11.357 ;
     RECT  4.104 11.165 4.122 11.821 ;
     RECT  6.948 11.749 7.038 11.849 ;
     RECT  3.78 11.821 4.122 11.975 ;
     RECT  7.02 11.849 7.038 11.975 ;
     RECT  7.815 11.129 8.097 12.091 ;
     RECT  2.415 10.895 2.898 12.361 ;
     RECT  4.104 11.975 4.122 12.487 ;
     RECT  5.076 11.357 5.778 12.487 ;
     RECT  2.415 12.361 3.366 12.515 ;
     RECT  4.104 12.487 5.778 12.523 ;
     RECT  4.104 12.523 5.886 12.557 ;
     RECT  7.815 12.091 8.766 12.901 ;
     RECT  4.896 12.557 5.886 13.595 ;
     RECT  5.076 13.595 5.886 13.613 ;
     RECT  7.092 12.901 8.766 13.711 ;
     RECT  0.108 11.704 0.126 13.865 ;
     RECT  4.104 12.557 4.122 13.981 ;
     RECT  3.672 13.981 4.122 14.135 ;
     RECT  2.415 12.515 2.898 14.203 ;
     RECT  2.304 14.203 2.898 14.405 ;
     RECT  3.744 14.135 4.122 14.521 ;
     RECT  5.076 13.613 5.778 14.521 ;
     RECT  3.744 14.521 4.266 14.675 ;
     RECT  0.108 14.647 0.126 14.717 ;
     RECT  3.816 14.675 4.266 14.791 ;
     RECT  5.004 14.521 5.778 14.791 ;
     RECT  6.768 13.711 8.766 14.791 ;
     RECT  3.816 14.791 5.778 14.945 ;
     RECT  2.415 14.405 2.898 15.163 ;
     RECT  12.132 11.137 12.15 15.215 ;
     RECT  2.304 15.163 2.898 15.485 ;
     RECT  4.104 14.945 5.778 15.601 ;
     RECT  6.516 14.791 8.766 15.601 ;
     RECT  2.415 15.485 2.898 15.871 ;
     RECT  4.104 15.601 8.766 15.871 ;
     RECT  2.415 15.871 8.766 15.989 ;
     RECT  3.816 15.989 8.766 16.565 ;
     RECT  11.088 16.807 11.106 17.041 ;
     RECT  0.108 15.691 0.126 17.375 ;
     RECT  2.415 15.989 2.898 17.491 ;
     RECT  3.996 16.565 8.766 17.491 ;
     RECT  2.415 17.491 8.766 17.609 ;
     RECT  2.415 17.609 2.898 17.653 ;
     RECT  1.728 17.653 2.898 17.693 ;
     RECT  2.304 17.693 2.898 18.455 ;
     RECT  3.996 17.609 8.766 18.661 ;
     RECT  3.888 18.661 8.766 18.797 ;
     RECT  3.996 18.797 8.766 18.995 ;
     RECT  4.104 18.995 8.766 19.741 ;
     RECT  3.888 19.741 8.766 19.841 ;
     RECT  9.936 10.561 9.99 19.921 ;
     RECT  2.415 18.455 2.898 20.731 ;
     RECT  2.415 20.731 3.114 20.965 ;
     RECT  4.032 19.841 8.766 20.965 ;
     RECT  0.108 18.667 0.126 21.695 ;
     RECT  2.415 20.965 8.766 21.929 ;
     RECT  2.415 21.929 2.898 22.123 ;
     RECT  0.108 22.603 0.126 22.775 ;
     RECT  3.78 21.929 8.766 22.919 ;
     RECT  2.304 22.123 2.898 23.585 ;
     RECT  2.415 23.585 2.898 23.665 ;
     RECT  2.415 23.665 3.006 23.819 ;
     RECT  3.996 22.919 8.766 23.863 ;
     RECT  9.936 19.921 10.026 23.863 ;
     RECT  2.415 23.819 2.934 24.359 ;
     RECT  0.108 23.611 0.126 25.205 ;
     RECT  3.996 23.863 10.026 25.861 ;
     RECT  2.415 24.359 2.898 26.107 ;
     RECT  2.304 26.107 2.898 26.285 ;
     RECT  3.96 25.861 10.026 26.401 ;
     RECT  3.816 26.401 10.026 26.555 ;
     RECT  3.996 26.555 10.026 28.489 ;
     RECT  10.764 17.041 11.106 28.489 ;
     RECT  0.108 26.587 0.126 29.255 ;
     RECT  2.415 26.285 2.898 29.371 ;
     RECT  3.996 28.489 11.106 29.371 ;
     RECT  2.415 29.371 11.106 29.489 ;
     RECT  2.415 29.489 3.042 29.563 ;
     RECT  2.304 29.563 3.042 30.065 ;
     RECT  0.108 30.091 0.126 30.605 ;
     RECT  2.415 30.065 3.042 30.721 ;
     RECT  3.996 29.489 11.106 30.721 ;
     RECT  2.415 30.721 11.106 30.839 ;
     RECT  2.415 30.839 2.898 31.051 ;
     RECT  3.672 30.839 11.106 31.145 ;
     RECT  2.304 31.051 2.898 31.415 ;
     RECT  2.415 31.415 2.898 32.341 ;
     RECT  3.996 31.145 11.106 32.341 ;
     RECT  2.415 32.341 11.106 32.495 ;
     RECT  0.108 31.579 0.126 32.765 ;
     RECT  3.888 32.495 11.106 33.035 ;
     RECT  2.415 32.495 2.898 33.043 ;
     RECT  2.268 33.043 2.898 33.101 ;
     RECT  3.996 33.035 11.106 33.961 ;
     RECT  3.96 33.961 11.106 34.115 ;
     RECT  2.304 33.101 2.898 34.385 ;
     RECT  13.215 2.413 13.497 35.041 ;
     RECT  0.108 34.555 0.126 35.195 ;
     RECT  3.996 34.115 11.106 35.311 ;
     RECT  2.415 34.385 2.898 36.121 ;
     RECT  3.96 35.311 11.106 36.121 ;
     RECT  2.415 36.121 11.106 36.275 ;
     RECT  0.108 36.043 0.126 36.557 ;
     RECT  2.415 36.275 2.898 37.003 ;
     RECT  2.304 37.003 2.898 37.085 ;
     RECT  0.108 37.531 0.126 39.245 ;
     RECT  3.996 36.275 11.106 39.289 ;
     RECT  0.54 39.487 0.558 39.533 ;
     RECT  3.96 39.289 11.106 39.631 ;
     RECT  0.108 39.979 0.126 40.595 ;
     RECT  51.015 2.413 51.297 40.597 ;
     RECT  51.015 40.597 51.93 40.637 ;
     RECT  61.815 2.413 62.097 40.651 ;
     RECT  2.415 37.085 2.898 40.711 ;
     RECT  3.78 39.631 11.106 40.711 ;
     RECT  24.015 2.413 24.297 40.787 ;
     RECT  29.415 2.413 29.697 40.787 ;
     RECT  34.815 2.413 35.097 40.787 ;
     RECT  40.215 2.413 40.497 40.787 ;
     RECT  45.615 2.413 45.897 40.787 ;
     RECT  51.015 40.637 51.297 40.787 ;
     RECT  56.415 2.413 56.697 40.787 ;
     RECT  61.704 40.651 62.097 40.787 ;
     RECT  67.215 2.413 67.497 40.787 ;
     RECT  72.615 2.413 72.897 40.787 ;
     RECT  78.015 2.413 78.297 40.787 ;
     RECT  83.415 2.413 83.697 40.787 ;
     RECT  88.815 2.413 89.097 40.787 ;
     RECT  94.215 2.413 94.497 40.787 ;
     RECT  99.615 2.413 99.897 40.787 ;
     RECT  105.015 2.413 105.297 40.787 ;
     RECT  110.415 2.413 110.697 40.787 ;
     RECT  115.815 2.413 116.097 40.787 ;
     RECT  121.215 2.413 121.497 40.787 ;
     RECT  126.615 2.413 126.897 40.787 ;
     RECT  132.015 2.413 132.297 40.787 ;
     RECT  137.415 2.413 137.697 40.787 ;
     RECT  142.815 2.413 143.097 40.787 ;
     RECT  148.215 2.413 148.497 40.787 ;
     RECT  153.615 2.413 153.897 40.787 ;
     RECT  159.015 2.413 159.297 40.787 ;
     RECT  164.415 2.413 164.697 40.787 ;
     RECT  169.815 2.413 170.097 40.787 ;
     RECT  175.215 2.413 175.497 40.787 ;
     RECT  180.615 2.413 180.897 40.787 ;
     RECT  186.015 2.413 186.297 40.787 ;
     RECT  191.415 2.413 191.697 40.787 ;
     RECT  58.716 40.603 58.734 40.829 ;
     RECT  61.704 40.787 61.938 40.829 ;
     RECT  52.236 40.711 52.254 40.925 ;
     RECT  2.415 40.711 11.106 40.987 ;
     RECT  24.015 40.787 24.105 41.057 ;
     RECT  29.415 40.787 29.505 41.057 ;
     RECT  34.815 40.787 34.905 41.057 ;
     RECT  40.215 40.787 40.305 41.057 ;
     RECT  45.615 40.787 45.705 41.057 ;
     RECT  51.015 40.787 51.105 41.057 ;
     RECT  56.415 40.787 56.505 41.057 ;
     RECT  61.815 40.829 61.905 41.057 ;
     RECT  67.215 40.787 67.305 41.057 ;
     RECT  72.615 40.787 72.705 41.057 ;
     RECT  78.015 40.787 78.105 41.057 ;
     RECT  83.415 40.787 83.505 41.057 ;
     RECT  88.815 40.787 88.905 41.057 ;
     RECT  94.215 40.787 94.305 41.057 ;
     RECT  99.615 40.787 99.705 41.057 ;
     RECT  105.015 40.787 105.105 41.057 ;
     RECT  110.415 40.787 110.505 41.057 ;
     RECT  115.815 40.787 115.905 41.057 ;
     RECT  121.215 40.787 121.305 41.057 ;
     RECT  126.615 40.787 126.705 41.057 ;
     RECT  132.015 40.787 132.105 41.057 ;
     RECT  137.415 40.787 137.505 41.057 ;
     RECT  142.815 40.787 142.905 41.057 ;
     RECT  148.215 40.787 148.305 41.057 ;
     RECT  153.615 40.787 153.705 41.057 ;
     RECT  159.015 40.787 159.105 41.057 ;
     RECT  164.415 40.787 164.505 41.057 ;
     RECT  169.815 40.787 169.905 41.057 ;
     RECT  175.215 40.787 175.305 41.057 ;
     RECT  180.615 40.787 180.705 41.057 ;
     RECT  186.015 40.787 186.105 41.057 ;
     RECT  191.415 40.787 191.505 41.057 ;
     RECT  2.304 40.987 11.106 41.675 ;
     RECT  2.304 41.675 2.898 42.215 ;
     RECT  3.708 41.675 11.106 42.485 ;
     RECT  3.78 42.485 11.106 42.521 ;
     RECT  3.852 42.521 11.106 43.025 ;
     RECT  20.304 42.727 20.322 43.141 ;
     RECT  194.364 43.141 194.382 43.2 ;
     RECT  22.464 43.2 194.382 43.231 ;
     RECT  21.744 43.231 194.382 43.303 ;
     RECT  2.415 42.215 2.898 43.681 ;
     RECT  196.815 2.413 197.097 43.681 ;
     RECT  21.708 43.303 194.382 43.771 ;
     RECT  21.672 43.771 194.886 43.843 ;
     RECT  2.415 43.681 3.114 44.221 ;
     RECT  3.996 43.025 11.106 44.221 ;
     RECT  20.16 43.141 20.322 44.311 ;
     RECT  2.415 44.221 11.106 44.375 ;
     RECT  20.088 44.311 20.322 44.477 ;
     RECT  21.672 43.843 194.922 44.477 ;
     RECT  0.108 42.475 0.126 44.645 ;
     RECT  196.092 43.681 197.097 44.765 ;
     RECT  3.78 44.375 11.106 44.915 ;
     RECT  20.088 44.477 20.286 44.957 ;
     RECT  2.415 44.375 2.898 44.971 ;
     RECT  20.088 44.957 20.214 45.053 ;
     RECT  194.796 44.477 194.922 45.053 ;
     RECT  194.832 45.053 194.922 45.157 ;
     RECT  2.304 44.971 2.898 45.185 ;
     RECT  21.672 44.477 193.752 45.229 ;
     RECT  21.636 45.229 193.752 45.391 ;
     RECT  20.196 45.053 20.214 45.437 ;
     RECT  0.108 45.451 0.126 45.491 ;
     RECT  194.832 45.157 194.958 45.533 ;
     RECT  2.415 45.185 2.898 45.931 ;
     RECT  196.2 44.765 197.097 46.003 ;
     RECT  196.128 46.003 197.097 46.103 ;
     RECT  194.868 45.533 194.958 46.205 ;
     RECT  21.096 45.391 193.752 46.301 ;
     RECT  194.904 46.205 194.958 46.471 ;
     RECT  21.096 46.301 21.69 46.493 ;
     RECT  0.108 46.459 0.126 46.535 ;
     RECT  3.996 44.915 11.106 46.651 ;
     RECT  194.904 46.471 195.498 46.685 ;
     RECT  3.924 46.651 11.106 46.805 ;
     RECT  196.236 46.103 197.097 46.84 ;
     RECT  21.096 46.493 21.654 46.939 ;
     RECT  20.304 46.615 20.322 47.155 ;
     RECT  20.268 47.155 20.322 47.323 ;
     RECT  21.06 46.939 21.654 47.323 ;
     RECT  194.904 46.685 194.958 47.419 ;
     RECT  194.904 47.419 194.994 47.551 ;
     RECT  196.092 46.84 197.097 47.551 ;
     RECT  0.108 47.467 0.126 47.615 ;
     RECT  20.268 47.323 21.654 47.659 ;
     RECT  22.464 46.301 193.752 47.659 ;
     RECT  194.904 47.551 197.097 47.659 ;
     RECT  20.268 47.659 193.752 47.731 ;
     RECT  194.868 47.659 197.097 47.837 ;
     RECT  2.304 45.931 2.898 47.857 ;
     RECT  19.872 47.731 193.752 47.857 ;
     RECT  194.868 47.837 194.958 47.857 ;
     RECT  19.872 47.857 194.958 47.885 ;
     RECT  196.2 47.837 197.097 47.885 ;
     RECT  2.268 47.857 2.898 47.981 ;
     RECT  3.996 46.805 11.106 48.001 ;
     RECT  3.924 48.001 11.106 48.155 ;
     RECT  20.052 47.885 194.958 48.221 ;
     RECT  20.052 48.221 194.922 48.413 ;
     RECT  0.108 48.424 0.126 48.461 ;
     RECT  196.344 47.885 197.097 48.775 ;
     RECT  20.052 48.413 20.286 48.811 ;
     RECT  196.164 48.775 197.097 48.901 ;
     RECT  19.872 48.811 20.286 49.171 ;
     RECT  21.06 48.413 194.922 49.171 ;
     RECT  195.984 48.901 197.097 49.171 ;
     RECT  19.872 49.171 197.097 49.565 ;
     RECT  21.6 49.565 195.498 49.757 ;
     RECT  21.636 49.757 195.498 50.045 ;
     RECT  3.996 48.155 11.106 50.161 ;
     RECT  21.636 50.045 194.958 50.237 ;
     RECT  3.96 50.161 11.106 50.315 ;
     RECT  196.38 49.565 197.097 50.389 ;
     RECT  21.636 50.237 193.752 50.525 ;
     RECT  19.872 49.565 20.538 50.657 ;
     RECT  20.052 50.657 20.538 50.863 ;
     RECT  21.636 50.525 21.69 50.863 ;
     RECT  20.052 50.863 21.69 50.909 ;
     RECT  194.832 50.237 194.958 50.935 ;
     RECT  196.164 50.389 197.097 50.935 ;
     RECT  22.464 50.525 193.752 51.097 ;
     RECT  194.832 50.935 197.097 51.097 ;
     RECT  20.052 50.909 21.654 51.101 ;
     RECT  22.464 51.097 197.097 51.197 ;
     RECT  2.415 47.981 2.898 51.241 ;
     RECT  3.996 50.315 11.106 51.241 ;
     RECT  2.415 51.241 11.106 51.359 ;
     RECT  20.052 51.101 20.286 51.403 ;
     RECT  3.78 51.359 11.106 51.917 ;
     RECT  22.464 51.197 194.958 51.931 ;
     RECT  19.872 51.403 20.286 51.943 ;
     RECT  21.06 51.101 21.654 51.943 ;
     RECT  0.108 49.435 0.126 51.965 ;
     RECT  22.464 51.931 195.21 52.043 ;
     RECT  19.872 51.943 21.654 52.157 ;
     RECT  21.096 52.157 21.654 52.321 ;
     RECT  22.464 52.043 194.922 52.321 ;
     RECT  196.164 51.197 197.097 52.321 ;
     RECT  21.096 52.321 194.922 52.349 ;
     RECT  2.415 51.359 2.898 52.411 ;
     RECT  2.304 52.411 2.898 52.475 ;
     RECT  195.984 52.321 197.097 52.583 ;
     RECT  196.092 52.583 197.097 52.829 ;
     RECT  196.164 52.829 197.097 53.021 ;
     RECT  3.996 51.917 11.106 53.095 ;
     RECT  19.872 52.157 20.07 53.117 ;
     RECT  21.636 52.349 194.922 53.257 ;
     RECT  21.168 53.257 194.958 53.329 ;
     RECT  21.132 53.329 194.958 53.365 ;
     RECT  19.872 53.117 19.89 53.869 ;
     RECT  21.06 53.365 194.958 53.869 ;
     RECT  2.415 52.475 2.898 53.941 ;
     RECT  3.996 53.095 11.178 53.941 ;
     RECT  19.872 53.869 194.958 54.077 ;
     RECT  21.096 54.077 194.922 54.269 ;
     RECT  19.872 54.077 19.89 54.671 ;
     RECT  196.2 53.021 197.097 54.679 ;
     RECT  195.984 54.679 197.097 54.743 ;
     RECT  21.096 54.269 193.752 54.749 ;
     RECT  194.76 54.269 194.922 54.877 ;
     RECT  22.464 54.749 193.752 55.147 ;
     RECT  194.76 54.877 194.958 55.147 ;
     RECT  2.415 53.941 11.178 55.445 ;
     RECT  21.096 54.749 21.654 55.483 ;
     RECT  196.416 54.743 197.097 55.561 ;
     RECT  2.415 55.445 3.15 55.715 ;
     RECT  21.06 55.483 21.654 55.771 ;
     RECT  196.236 55.561 197.097 55.795 ;
     RECT  21.06 55.771 21.726 56.129 ;
     RECT  22.464 55.147 194.958 56.189 ;
     RECT  0.108 52.891 0.126 56.255 ;
     RECT  3.996 55.445 11.178 56.371 ;
     RECT  2.415 55.715 2.898 56.395 ;
     RECT  21.06 56.129 21.654 56.525 ;
     RECT  21.06 56.525 21.618 56.539 ;
     RECT  20.844 56.539 21.618 56.759 ;
     RECT  12.816 35.041 13.497 57.019 ;
     RECT  22.464 56.189 194.922 57.037 ;
     RECT  2.304 56.395 2.898 57.065 ;
     RECT  22.464 57.037 194.958 57.211 ;
     RECT  12.816 57.019 13.626 57.307 ;
     RECT  14.58 57.115 14.598 57.355 ;
     RECT  2.415 57.065 2.898 57.451 ;
     RECT  3.636 56.371 11.178 57.451 ;
     RECT  18.615 2.413 18.897 57.499 ;
     RECT  196.164 55.795 197.097 57.499 ;
     RECT  12.384 57.307 13.626 57.595 ;
     RECT  12.312 57.595 13.626 57.691 ;
     RECT  22.356 57.211 194.958 57.811 ;
     RECT  195.984 57.499 197.097 57.811 ;
     RECT  14.58 57.355 14.778 57.883 ;
     RECT  22.356 57.811 197.097 57.917 ;
     RECT  194.724 57.917 197.097 58.013 ;
     RECT  194.724 58.013 194.958 58.109 ;
     RECT  2.415 57.451 11.178 58.145 ;
     RECT  3.996 58.145 11.178 58.171 ;
     RECT  12.132 57.691 13.626 58.171 ;
     RECT  194.76 58.109 194.958 58.205 ;
     RECT  3.996 58.171 13.626 58.363 ;
     RECT  14.58 57.883 15.102 58.363 ;
     RECT  3.996 58.363 15.102 58.411 ;
     RECT  22.356 57.917 193.752 58.445 ;
     RECT  3.996 58.411 15.174 58.651 ;
     RECT  16.812 15.151 16.83 59.035 ;
     RECT  194.796 58.205 194.958 59.035 ;
     RECT  196.02 58.013 197.097 59.035 ;
     RECT  3.996 58.651 15.282 59.071 ;
     RECT  194.796 59.035 197.097 59.165 ;
     RECT  3.636 59.071 15.282 59.189 ;
     RECT  22.464 58.445 193.752 59.233 ;
     RECT  194.796 59.165 194.922 59.233 ;
     RECT  18.615 57.499 19.134 59.369 ;
     RECT  18.615 59.369 19.098 59.495 ;
     RECT  18.615 59.495 19.062 59.567 ;
     RECT  22.464 59.233 194.922 59.611 ;
     RECT  18.615 59.567 19.026 59.639 ;
     RECT  18.615 59.639 18.99 59.765 ;
     RECT  22.356 59.611 194.922 60.029 ;
     RECT  0.108 57.343 0.126 60.035 ;
     RECT  196.092 59.165 197.097 60.115 ;
     RECT  3.996 59.189 15.282 60.283 ;
     RECT  16.236 59.035 16.83 60.283 ;
     RECT  3.996 60.283 16.83 60.331 ;
     RECT  17.676 59.809 17.694 60.331 ;
     RECT  22.356 60.029 194.418 60.365 ;
     RECT  195.48 60.115 197.097 60.377 ;
     RECT  22.464 60.365 194.418 60.605 ;
     RECT  19.908 60.379 19.926 60.781 ;
     RECT  195.48 60.377 195.498 60.817 ;
     RECT  0.108 60.853 0.126 60.893 ;
     RECT  19.836 60.781 19.926 60.955 ;
     RECT  20.844 56.759 21.546 60.955 ;
     RECT  3.996 60.331 17.694 60.961 ;
     RECT  3.96 60.961 17.694 61.037 ;
     RECT  18.615 59.765 18.954 61.051 ;
     RECT  19.836 60.955 21.546 61.051 ;
     RECT  22.464 60.605 193.752 61.243 ;
     RECT  194.94 60.817 195.498 61.277 ;
     RECT  2.415 58.145 2.898 61.339 ;
     RECT  196.272 60.377 197.097 61.531 ;
     RECT  2.34 61.339 2.898 61.655 ;
     RECT  18.615 61.051 21.546 62.107 ;
     RECT  22.356 61.243 193.752 62.107 ;
     RECT  196.02 61.531 197.097 62.159 ;
     RECT  3.996 61.037 17.694 62.443 ;
     RECT  18.615 62.107 193.752 62.443 ;
     RECT  194.94 61.277 194.958 62.581 ;
     RECT  3.996 62.443 193.752 62.683 ;
     RECT  194.868 62.581 194.958 62.683 ;
     RECT  3.996 62.683 194.958 62.957 ;
     RECT  0.108 61.819 0.126 63.005 ;
     RECT  194.832 62.957 194.958 63.067 ;
     RECT  3.996 62.957 193.752 63.121 ;
     RECT  194.832 63.067 195.174 63.149 ;
     RECT  2.415 61.655 2.898 63.247 ;
     RECT  1.728 63.247 2.898 63.341 ;
     RECT  194.832 63.149 194.958 63.389 ;
     RECT  2.415 63.341 2.898 63.391 ;
     RECT  3.96 63.121 193.752 63.391 ;
     RECT  196.164 62.159 197.097 63.517 ;
     RECT  2.415 63.391 193.752 63.779 ;
     RECT  3.672 63.779 193.752 63.869 ;
     RECT  196.092 63.517 197.097 64.085 ;
     RECT  3.852 63.869 193.752 64.291 ;
     RECT  194.832 63.389 194.922 64.291 ;
     RECT  3.852 64.291 194.922 64.445 ;
     RECT  3.852 64.445 193.752 64.625 ;
     RECT  194.868 64.445 194.922 64.741 ;
     RECT  194.868 64.741 194.958 64.939 ;
     RECT  3.96 64.625 193.752 65.021 ;
     RECT  194.868 64.939 194.994 65.021 ;
     RECT  194.904 65.021 194.994 65.117 ;
     RECT  194.904 65.117 194.958 65.213 ;
     RECT  2.415 63.779 2.898 65.371 ;
     RECT  2.415 65.371 3.15 65.597 ;
     RECT  196.2 64.085 197.097 65.677 ;
     RECT  194.904 65.213 194.922 66.217 ;
     RECT  194.904 66.217 194.958 66.451 ;
     RECT  196.092 65.677 197.097 66.451 ;
     RECT  3.996 65.021 193.752 66.631 ;
     RECT  194.904 66.451 197.097 66.653 ;
     RECT  3.924 66.631 193.752 66.785 ;
     RECT  0.108 63.835 0.126 67.325 ;
     RECT  2.415 65.597 2.898 67.441 ;
     RECT  196.2 66.653 197.097 67.669 ;
     RECT  2.415 67.441 3.114 67.711 ;
     RECT  3.996 66.785 193.752 67.711 ;
     RECT  194.904 66.653 194.958 68.071 ;
     RECT  196.164 67.669 197.097 68.071 ;
     RECT  2.415 67.711 193.752 68.341 ;
     RECT  194.904 68.071 197.097 68.341 ;
     RECT  2.415 68.341 197.097 68.639 ;
     RECT  3.996 68.639 197.097 68.675 ;
     RECT  196.272 68.675 197.097 68.957 ;
     RECT  3.996 68.675 195.498 69.493 ;
     RECT  3.744 69.493 195.498 70.025 ;
     RECT  3.996 70.025 195.498 70.301 ;
     RECT  194.868 70.301 195.498 70.375 ;
     RECT  196.308 68.957 197.097 70.375 ;
     RECT  3.996 70.301 193.752 70.951 ;
     RECT  3.888 70.951 193.752 71.149 ;
     RECT  194.868 70.375 197.097 71.149 ;
     RECT  0.108 68.299 0.126 71.375 ;
     RECT  3.888 71.149 197.097 71.491 ;
     RECT  3.672 71.491 197.097 71.645 ;
     RECT  2.415 68.639 2.898 71.755 ;
     RECT  3.672 71.645 194.958 72.029 ;
     RECT  2.304 71.755 2.898 72.031 ;
     RECT  3.672 72.029 193.752 72.031 ;
     RECT  196.092 71.645 197.097 72.125 ;
     RECT  194.832 72.029 194.958 72.475 ;
     RECT  194.832 72.475 195.21 72.563 ;
     RECT  196.128 72.125 197.097 72.797 ;
     RECT  196.164 72.797 197.097 72.893 ;
     RECT  2.304 72.031 193.752 72.931 ;
     RECT  194.832 72.563 194.922 72.931 ;
     RECT  2.304 72.931 194.922 72.995 ;
     RECT  0.54 73.237 0.558 73.277 ;
     RECT  2.415 72.995 194.922 73.421 ;
     RECT  3.996 73.421 194.922 73.661 ;
     RECT  196.2 72.893 197.097 74.389 ;
     RECT  196.092 74.389 197.097 74.429 ;
     RECT  194.832 73.661 194.922 74.857 ;
     RECT  2.415 73.421 2.898 75.001 ;
     RECT  3.996 73.661 193.752 75.001 ;
     RECT  194.832 74.857 194.958 75.001 ;
     RECT  2.415 75.001 194.958 75.155 ;
     RECT  3.996 75.155 194.958 75.293 ;
     RECT  196.416 74.429 197.097 75.397 ;
     RECT  0.108 73.771 0.126 75.425 ;
     RECT  194.868 75.293 194.958 75.631 ;
     RECT  2.415 75.155 2.898 75.739 ;
     RECT  2.304 75.739 2.898 75.965 ;
     RECT  194.868 75.631 194.994 76.027 ;
     RECT  2.415 75.965 2.898 76.081 ;
     RECT  3.996 75.293 193.752 76.081 ;
     RECT  196.2 75.397 197.097 76.081 ;
     RECT  194.868 76.027 195.174 76.109 ;
     RECT  196.092 76.081 197.097 76.157 ;
     RECT  2.415 76.081 193.752 76.199 ;
     RECT  194.868 76.109 194.994 76.829 ;
     RECT  194.868 76.829 194.958 76.925 ;
     RECT  196.236 76.157 197.097 77.125 ;
     RECT  3.996 76.199 193.752 77.161 ;
     RECT  194.868 76.925 194.922 77.161 ;
     RECT  196.092 77.125 197.097 77.309 ;
     RECT  196.164 77.309 197.097 77.501 ;
     RECT  3.996 77.161 194.922 77.693 ;
     RECT  194.904 77.693 194.922 77.701 ;
     RECT  196.2 77.501 197.097 78.331 ;
     RECT  194.904 77.701 194.958 78.511 ;
     RECT  196.128 78.331 197.097 78.511 ;
     RECT  196.092 78.511 197.097 78.637 ;
     RECT  3.996 77.693 193.752 79.177 ;
     RECT  194.868 78.511 194.958 79.177 ;
     RECT  3.996 79.177 194.958 79.555 ;
     RECT  196.02 78.637 197.097 79.555 ;
     RECT  3.996 79.555 197.097 80.477 ;
     RECT  195.48 80.477 197.097 81.245 ;
     RECT  196.092 81.245 197.097 81.365 ;
     RECT  3.996 80.477 194.418 81.481 ;
     RECT  3.996 81.481 194.958 82.109 ;
     RECT  194.904 82.109 194.958 82.171 ;
     RECT  196.272 81.365 197.097 82.255 ;
     RECT  194.904 82.171 195.21 82.283 ;
     RECT  196.2 82.255 197.097 82.417 ;
     RECT  196.092 82.417 197.097 82.877 ;
     RECT  194.904 82.283 194.958 83.029 ;
     RECT  194.868 83.029 194.958 83.515 ;
     RECT  196.164 82.877 197.097 83.525 ;
     RECT  3.996 82.109 193.752 83.767 ;
     RECT  194.868 83.515 195.21 83.767 ;
     RECT  3.996 83.767 195.21 84.173 ;
     RECT  2.415 76.199 2.898 84.307 ;
     RECT  196.2 83.525 197.097 84.893 ;
     RECT  2.415 84.307 3.078 85.189 ;
     RECT  3.996 84.173 194.922 85.225 ;
     RECT  2.415 85.189 3.222 85.459 ;
     RECT  3.996 85.225 195.498 85.459 ;
     RECT  2.415 85.459 195.498 85.495 ;
     RECT  2.304 85.495 195.498 85.649 ;
     RECT  3.996 85.649 195.498 85.853 ;
     RECT  196.272 84.893 197.097 85.915 ;
     RECT  0.108 84.181 0.126 86.027 ;
     RECT  3.996 85.853 194.958 86.141 ;
     RECT  2.376 85.649 3.186 86.575 ;
     RECT  0.54 86.539 0.558 86.639 ;
     RECT  2.304 86.575 3.186 86.729 ;
     RECT  194.904 86.141 194.958 86.845 ;
     RECT  196.164 85.915 197.097 86.845 ;
     RECT  2.415 86.729 3.186 86.881 ;
     RECT  3.996 86.141 193.752 86.881 ;
     RECT  194.904 86.845 197.097 87.005 ;
     RECT  2.415 86.881 193.752 87.269 ;
     RECT  2.415 87.269 2.934 87.655 ;
     RECT  3.996 87.269 193.752 87.691 ;
     RECT  194.904 87.005 194.958 87.691 ;
     RECT  0.108 87.115 0.126 87.728 ;
     RECT  3.996 87.691 194.958 87.869 ;
     RECT  194.796 87.869 194.958 87.925 ;
     RECT  196.092 87.005 197.097 87.925 ;
     RECT  194.796 87.925 197.097 88.253 ;
     RECT  0.54 88.231 0.558 88.301 ;
     RECT  2.304 87.655 2.934 88.321 ;
     RECT  3.996 87.869 193.752 88.321 ;
     RECT  196.092 88.253 197.097 88.349 ;
     RECT  194.796 88.253 194.958 88.445 ;
     RECT  2.304 88.321 193.752 88.619 ;
     RECT  2.304 88.619 3.186 88.655 ;
     RECT  196.2 88.349 197.097 88.772 ;
     RECT  196.236 88.772 197.097 88.889 ;
     RECT  3.996 88.619 193.752 89.311 ;
     RECT  194.832 88.445 194.958 89.311 ;
     RECT  2.415 88.655 3.186 89.401 ;
     RECT  3.996 89.311 194.958 89.401 ;
     RECT  0.108 88.771 0.126 89.429 ;
     RECT  2.415 89.401 194.958 89.501 ;
     RECT  3.996 89.501 194.958 89.597 ;
     RECT  196.416 88.889 197.097 89.815 ;
     RECT  2.415 89.501 3.186 89.947 ;
     RECT  194.832 89.597 194.958 90.173 ;
     RECT  196.2 89.815 197.097 90.391 ;
     RECT  0.108 90.481 0.126 90.557 ;
     RECT  2.304 89.947 3.186 90.907 ;
     RECT  3.996 89.597 193.752 90.907 ;
     RECT  2.304 90.907 193.752 90.931 ;
     RECT  194.868 90.173 194.958 90.931 ;
     RECT  196.092 90.391 197.097 91.037 ;
     RECT  2.304 90.931 194.958 91.049 ;
     RECT  0.144 91.099 0.162 91.157 ;
     RECT  3.888 91.049 194.958 91.229 ;
     RECT  2.304 91.049 2.898 91.319 ;
     RECT  3.888 91.229 193.752 91.319 ;
     RECT  4.392 91.319 193.752 91.391 ;
     RECT  2.415 91.319 2.898 91.831 ;
     RECT  2.415 91.831 3.618 91.931 ;
     RECT  194.868 91.229 194.958 91.963 ;
     RECT  194.868 91.963 194.994 92.039 ;
     RECT  2.415 91.931 2.898 92.251 ;
     RECT  2.376 92.251 2.898 92.399 ;
     RECT  196.2 91.037 197.097 92.407 ;
     RECT  2.415 92.399 2.898 92.821 ;
     RECT  0.54 92.821 0.558 92.861 ;
     RECT  2.415 92.821 2.934 92.911 ;
     RECT  3.708 92.281 3.726 92.911 ;
     RECT  2.415 92.911 3.834 92.923 ;
     RECT  4.608 91.391 193.752 92.923 ;
     RECT  194.868 92.039 194.958 92.957 ;
     RECT  194.904 92.957 194.958 93.181 ;
     RECT  196.164 92.407 197.097 93.181 ;
     RECT  2.415 92.923 193.752 93.209 ;
     RECT  2.415 93.209 3.186 93.479 ;
     RECT  3.996 93.209 193.752 93.749 ;
     RECT  194.904 93.181 197.097 93.821 ;
     RECT  194.904 93.821 195.498 93.829 ;
     RECT  2.415 93.479 3.114 94.019 ;
     RECT  2.415 94.019 2.97 94.199 ;
     RECT  194.832 93.829 195.498 94.208 ;
     RECT  194.868 94.208 195.498 94.603 ;
     RECT  196.272 93.821 197.097 94.603 ;
     RECT  4.608 93.749 193.752 94.699 ;
     RECT  4.572 94.699 193.752 94.901 ;
     RECT  2.415 94.199 2.898 94.945 ;
     RECT  2.415 94.945 3.474 95.099 ;
     RECT  21.348 94.901 193.752 95.107 ;
     RECT  194.868 94.603 197.097 95.107 ;
     RECT  21.348 95.107 197.097 95.165 ;
     RECT  21.348 95.165 195.21 95.513 ;
     RECT  4.572 94.901 20.358 95.909 ;
     RECT  21.348 95.513 194.958 95.933 ;
     RECT  2.415 95.099 3.33 96.151 ;
     RECT  196.164 95.165 197.097 96.224 ;
     RECT  0.108 93.352 0.126 96.287 ;
     RECT  2.376 96.151 3.33 96.331 ;
     RECT  2.376 96.331 3.366 96.449 ;
     RECT  195.192 96.475 195.21 96.593 ;
     RECT  21.348 95.933 194.382 96.605 ;
     RECT  2.376 96.449 3.186 96.629 ;
     RECT  4.608 95.909 20.358 96.629 ;
     RECT  2.376 96.629 2.898 96.691 ;
     RECT  2.304 96.691 2.898 96.863 ;
     RECT  0.54 96.811 0.558 96.899 ;
     RECT  194.868 96.691 194.958 96.989 ;
     RECT  4.608 96.629 20.214 97.375 ;
     RECT  2.415 96.863 2.898 97.411 ;
     RECT  2.415 97.411 2.934 97.501 ;
     RECT  194.904 96.989 194.958 97.681 ;
     RECT  4.572 97.375 20.214 97.835 ;
     RECT  2.415 97.501 3.186 97.915 ;
     RECT  4.572 97.835 20.178 97.951 ;
     RECT  4.428 97.951 20.178 97.997 ;
     RECT  194.904 97.681 194.994 98.141 ;
     RECT  196.2 96.224 197.097 98.299 ;
     RECT  2.415 97.915 3.438 98.455 ;
     RECT  194.94 98.141 194.994 98.455 ;
     RECT  196.092 98.299 197.097 98.455 ;
     RECT  2.376 98.455 3.438 98.491 ;
     RECT  2.376 98.491 3.69 98.609 ;
     RECT  2.376 98.609 3.618 98.681 ;
     RECT  2.376 98.681 3.222 98.789 ;
     RECT  194.94 98.455 197.097 98.959 ;
     RECT  194.868 98.959 197.097 99.101 ;
     RECT  21.348 96.605 193.752 99.157 ;
     RECT  194.868 99.101 194.922 99.157 ;
     RECT  196.128 99.101 197.097 99.419 ;
     RECT  4.608 97.997 20.178 99.491 ;
     RECT  2.415 98.789 3.222 99.535 ;
     RECT  4.608 99.491 19.098 99.571 ;
     RECT  4.5 99.571 19.098 99.599 ;
     RECT  2.304 99.535 3.222 99.661 ;
     RECT  4.5 99.599 18.897 99.689 ;
     RECT  2.304 99.661 3.438 99.805 ;
     RECT  21.348 99.157 194.922 99.931 ;
     RECT  2.304 99.805 4.086 99.959 ;
     RECT  21.348 99.931 194.958 99.968 ;
     RECT  0.108 97.387 0.126 100.253 ;
     RECT  196.164 99.419 197.097 100.253 ;
     RECT  2.415 99.959 4.086 100.499 ;
     RECT  4.896 99.689 18.897 100.651 ;
     RECT  2.415 100.499 3.942 100.769 ;
     RECT  3.924 100.769 3.942 100.829 ;
     RECT  4.86 100.651 18.897 100.841 ;
     RECT  2.415 100.769 3.186 101.047 ;
     RECT  21.348 99.968 194.922 101.155 ;
     RECT  196.2 100.253 197.097 101.155 ;
     RECT  21.348 101.155 197.097 101.405 ;
     RECT  21.348 101.405 194.958 101.597 ;
     RECT  2.412 101.047 3.186 101.651 ;
     RECT  2.412 101.651 2.898 101.821 ;
     RECT  4.896 100.841 18.897 101.821 ;
     RECT  4.572 101.821 18.897 101.965 ;
     RECT  4.248 101.965 18.897 102.119 ;
     RECT  5.184 102.119 18.897 102.191 ;
     RECT  194.904 101.597 194.958 102.229 ;
     RECT  196.2 101.405 197.097 102.229 ;
     RECT  20.124 99.491 20.178 102.271 ;
     RECT  21.348 101.597 193.752 102.299 ;
     RECT  5.256 102.191 18.897 102.361 ;
     RECT  20.124 102.271 20.43 102.425 ;
     RECT  0.54 101.899 0.558 102.569 ;
     RECT  2.304 101.821 2.898 102.631 ;
     RECT  4.248 102.119 4.266 102.631 ;
     RECT  194.904 102.229 197.097 102.653 ;
     RECT  2.304 102.631 4.266 102.659 ;
     RECT  2.415 102.659 4.266 102.929 ;
     RECT  21.384 102.299 193.752 103.081 ;
     RECT  2.415 102.929 3.546 103.199 ;
     RECT  20.124 102.425 20.358 103.279 ;
     RECT  21.384 103.081 194.382 103.279 ;
     RECT  195.48 102.653 197.097 103.421 ;
     RECT  20.124 103.279 194.382 103.477 ;
     RECT  2.415 103.199 3.186 103.577 ;
     RECT  20.124 103.477 194.994 103.613 ;
     RECT  0.108 103.051 0.126 103.661 ;
     RECT  2.415 103.577 2.934 103.739 ;
     RECT  20.124 103.613 194.958 103.805 ;
     RECT  5.256 102.361 18.99 103.891 ;
     RECT  4.716 103.891 18.99 104.009 ;
     RECT  20.124 103.805 194.922 104.089 ;
     RECT  0.54 104.161 0.558 104.237 ;
     RECT  4.356 104.161 4.374 104.315 ;
     RECT  5.112 104.009 18.99 104.323 ;
     RECT  19.728 104.089 194.922 104.323 ;
     RECT  2.415 103.739 2.898 104.665 ;
     RECT  5.112 104.323 194.922 104.701 ;
     RECT  2.34 104.665 2.898 104.791 ;
     RECT  5.112 104.701 194.958 104.791 ;
     RECT  2.34 104.791 3.186 104.819 ;
     RECT  4.572 104.791 194.958 104.957 ;
     RECT  4.572 104.957 193.752 105.089 ;
     RECT  196.092 103.421 197.097 105.245 ;
     RECT  2.415 104.819 3.186 105.331 ;
     RECT  2.415 105.331 3.33 105.431 ;
     RECT  196.2 105.245 197.097 105.917 ;
     RECT  5.256 105.089 193.752 106.051 ;
     RECT  4.392 105.241 4.41 106.213 ;
     RECT  5.148 106.051 193.752 106.213 ;
     RECT  194.868 104.957 194.958 106.411 ;
     RECT  0.108 104.701 0.126 106.493 ;
     RECT  2.415 105.431 3.186 106.681 ;
     RECT  194.832 106.411 194.958 106.685 ;
     RECT  2.415 106.681 3.258 106.789 ;
     RECT  196.236 105.917 197.097 106.861 ;
     RECT  2.415 106.789 3.582 106.979 ;
     RECT  196.2 106.861 197.097 107.035 ;
     RECT  194.904 106.685 194.958 107.095 ;
     RECT  196.164 107.035 197.097 107.095 ;
     RECT  0.54 107.035 0.558 107.699 ;
     RECT  2.415 106.979 3.366 108.175 ;
     RECT  4.392 106.213 193.752 108.211 ;
     RECT  194.904 107.095 197.097 108.221 ;
     RECT  2.415 108.175 3.438 108.329 ;
     RECT  4.176 108.211 193.752 108.481 ;
     RECT  194.904 108.221 194.958 108.481 ;
     RECT  4.176 108.481 194.958 108.509 ;
     RECT  4.176 108.509 194.922 108.751 ;
     RECT  0.108 108.751 0.126 108.797 ;
     RECT  195.984 108.221 197.097 108.905 ;
     RECT  2.415 108.329 2.934 109.291 ;
     RECT  3.924 108.751 194.922 109.291 ;
     RECT  0.54 109.291 0.558 109.373 ;
     RECT  196.02 108.905 197.097 109.589 ;
     RECT  2.415 109.291 194.922 110.371 ;
     RECT  2.304 110.371 194.922 110.525 ;
     RECT  2.415 110.525 194.922 110.875 ;
     RECT  196.2 109.589 197.097 110.875 ;
     RECT  2.415 110.875 197.097 111.005 ;
     RECT  0.108 109.831 0.126 111.053 ;
     RECT  2.415 111.005 194.958 111.209 ;
     RECT  2.415 111.209 12.258 111.299 ;
     RECT  12.132 111.299 12.258 111.335 ;
     RECT  12.996 111.209 194.958 111.443 ;
     RECT  2.415 111.299 11.214 111.479 ;
     RECT  2.415 111.479 2.97 111.541 ;
     RECT  2.412 111.541 2.97 111.685 ;
     RECT  2.304 111.685 2.97 111.839 ;
     RECT  13.14 111.443 194.958 111.869 ;
     RECT  3.78 111.479 11.214 112.019 ;
     RECT  3.78 112.019 10.818 112.109 ;
     RECT  12.24 111.335 12.258 112.145 ;
     RECT  0.54 111.595 0.558 112.289 ;
     RECT  13.14 111.869 194.922 112.349 ;
     RECT  196.164 111.005 197.097 112.459 ;
     RECT  194.868 112.349 194.922 112.792 ;
     RECT  2.415 111.839 2.97 112.891 ;
     RECT  3.78 112.109 10.278 112.891 ;
     RECT  13.14 112.349 193.752 113.027 ;
     RECT  194.868 112.792 194.958 113.035 ;
     RECT  196.092 112.459 197.097 113.035 ;
     RECT  2.415 112.891 10.278 113.099 ;
     RECT  3.708 113.099 10.278 113.161 ;
     RECT  13.14 113.027 13.497 113.189 ;
     RECT  14.256 113.027 193.752 113.197 ;
     RECT  194.868 113.035 197.097 113.197 ;
     RECT  3.708 113.161 10.782 113.261 ;
     RECT  13.212 113.189 13.497 113.297 ;
     RECT  3.708 113.261 10.746 113.357 ;
     RECT  0.108 112.747 0.126 113.369 ;
     RECT  3.78 113.357 10.746 113.369 ;
     RECT  14.256 113.197 197.097 113.801 ;
     RECT  0.144 113.851 0.162 113.909 ;
     RECT  14.58 113.801 197.097 113.981 ;
     RECT  3.78 113.369 10.278 114.143 ;
     RECT  14.58 113.981 194.958 114.179 ;
     RECT  15.12 114.179 194.958 114.377 ;
     RECT  2.415 113.099 2.934 114.385 ;
     RECT  15.156 114.377 194.958 114.413 ;
     RECT  2.304 114.385 2.934 114.421 ;
     RECT  3.78 114.143 10.206 114.421 ;
     RECT  2.304 114.421 10.206 114.539 ;
     RECT  15.552 114.413 194.958 114.557 ;
     RECT  2.304 114.539 3.006 114.575 ;
     RECT  195.984 113.981 197.097 114.683 ;
     RECT  15.552 114.557 193.752 114.719 ;
     RECT  2.415 114.575 3.006 115.151 ;
     RECT  16.092 114.719 193.752 115.229 ;
     RECT  194.796 114.557 194.958 115.229 ;
     RECT  17.424 115.229 193.752 115.529 ;
     RECT  194.796 115.229 194.922 115.709 ;
     RECT  194.832 115.709 194.922 115.805 ;
     RECT  16.092 115.229 16.578 115.997 ;
     RECT  16.308 115.997 16.578 116.033 ;
     RECT  194.868 115.805 194.922 116.041 ;
     RECT  2.415 115.151 2.97 116.069 ;
     RECT  17.496 115.529 193.752 116.159 ;
     RECT  0.108 114.421 0.126 116.189 ;
     RECT  16.56 116.033 16.578 116.195 ;
     RECT  194.868 116.041 194.958 116.381 ;
     RECT  194.904 116.381 194.958 116.477 ;
     RECT  194.904 116.477 194.922 116.573 ;
     RECT  17.964 116.159 193.752 116.861 ;
     RECT  17.964 116.861 20.178 117.053 ;
     RECT  16.74 116.203 16.758 117.355 ;
     RECT  2.415 116.069 2.898 117.391 ;
     RECT  3.78 114.539 10.206 117.391 ;
     RECT  20.988 116.861 193.752 117.437 ;
     RECT  194.904 117.355 194.922 117.437 ;
     RECT  17.964 117.053 19.386 117.533 ;
     RECT  21.132 117.437 193.752 117.725 ;
     RECT  0.108 117.307 0.126 117.959 ;
     RECT  2.415 117.391 10.206 118.049 ;
     RECT  18.036 117.533 19.386 118.205 ;
     RECT  2.415 118.049 2.898 118.291 ;
     RECT  196.092 114.683 197.097 118.459 ;
     RECT  2.304 118.291 2.898 118.463 ;
     RECT  0.54 118.411 0.558 118.499 ;
     RECT  18.396 118.205 19.386 118.589 ;
     RECT  16.74 117.355 17.01 118.939 ;
     RECT  21.168 117.725 193.752 118.987 ;
     RECT  21.024 118.987 193.752 119.039 ;
     RECT  21.096 119.039 193.752 119.069 ;
     RECT  2.415 118.463 2.898 119.101 ;
     RECT  3.636 118.049 10.206 119.101 ;
     RECT  16.272 118.939 17.01 119.131 ;
     RECT  195.984 118.459 197.097 119.165 ;
     RECT  18.504 118.589 19.17 119.261 ;
     RECT  21.384 119.069 193.752 119.357 ;
     RECT  194.94 118.747 194.958 119.399 ;
     RECT  16.272 119.131 17.046 119.443 ;
     RECT  21.384 119.357 21.402 119.453 ;
     RECT  13.215 113.297 13.497 119.467 ;
     RECT  22.32 119.357 193.752 119.515 ;
     RECT  16.272 119.443 17.298 119.669 ;
     RECT  16.272 119.669 17.19 119.707 ;
     RECT  18.504 119.261 18.897 119.707 ;
     RECT  196.128 119.165 197.097 119.899 ;
     RECT  16.164 119.707 17.19 119.939 ;
     RECT  196.092 119.899 197.097 119.995 ;
     RECT  20.124 117.053 20.178 120.019 ;
     RECT  2.415 119.101 10.206 120.055 ;
     RECT  20.124 120.019 20.214 120.119 ;
     RECT  21.096 120.085 21.114 120.125 ;
     RECT  22.32 119.515 194.382 120.281 ;
     RECT  20.124 120.119 20.178 120.353 ;
     RECT  16.164 119.939 17.118 120.479 ;
     RECT  196.02 119.995 197.097 120.479 ;
     RECT  20.124 120.353 20.142 120.587 ;
     RECT  196.092 120.479 197.097 120.785 ;
     RECT  2.34 120.055 10.206 120.865 ;
     RECT  22.464 120.281 194.382 120.984 ;
     RECT  194.364 120.984 194.382 121.019 ;
     RECT  0.108 118.987 0.126 121.325 ;
     RECT  2.304 120.865 10.206 121.559 ;
     RECT  0.144 121.867 0.162 121.937 ;
     RECT  2.415 121.559 10.206 122.485 ;
     RECT  0.54 122.395 0.558 122.549 ;
     RECT  2.304 122.485 10.206 122.639 ;
     RECT  0.108 122.971 0.126 123.017 ;
     RECT  22.5 123.151 22.518 123.197 ;
     RECT  24.015 123.103 24.105 123.373 ;
     RECT  29.415 123.103 29.505 123.373 ;
     RECT  34.815 123.103 34.905 123.373 ;
     RECT  40.215 123.103 40.305 123.373 ;
     RECT  45.615 123.103 45.705 123.373 ;
     RECT  51.015 123.103 51.105 123.373 ;
     RECT  56.415 123.103 56.505 123.373 ;
     RECT  61.815 123.103 61.905 123.373 ;
     RECT  67.215 123.103 67.305 123.373 ;
     RECT  72.615 123.103 72.705 123.373 ;
     RECT  78.015 123.103 78.105 123.373 ;
     RECT  83.415 123.103 83.505 123.373 ;
     RECT  88.815 123.103 88.905 123.373 ;
     RECT  94.215 123.103 94.305 123.373 ;
     RECT  99.615 123.103 99.705 123.373 ;
     RECT  105.015 123.103 105.105 123.373 ;
     RECT  110.415 123.103 110.505 123.373 ;
     RECT  115.815 123.103 115.905 123.373 ;
     RECT  121.215 123.103 121.305 123.373 ;
     RECT  126.615 123.103 126.705 123.373 ;
     RECT  132.015 123.103 132.105 123.373 ;
     RECT  137.415 123.103 137.505 123.373 ;
     RECT  142.815 123.103 142.905 123.373 ;
     RECT  148.215 123.103 148.305 123.373 ;
     RECT  153.615 123.103 153.705 123.373 ;
     RECT  159.015 123.103 159.105 123.373 ;
     RECT  164.415 123.103 164.505 123.373 ;
     RECT  169.815 123.103 169.905 123.373 ;
     RECT  175.215 123.103 175.305 123.373 ;
     RECT  180.615 123.103 180.705 123.373 ;
     RECT  186.015 123.103 186.105 123.373 ;
     RECT  191.415 123.103 191.505 123.373 ;
     RECT  22.788 123.331 22.806 123.421 ;
     RECT  22.788 123.421 22.878 123.485 ;
     RECT  0.54 123.547 0.558 123.629 ;
     RECT  2.415 122.639 10.206 125.185 ;
     RECT  2.304 125.185 10.206 125.609 ;
     RECT  0.108 124.123 0.126 126.989 ;
     RECT  2.415 125.609 10.206 127.471 ;
     RECT  2.304 127.471 10.206 127.643 ;
     RECT  0.54 127.531 0.558 127.679 ;
     RECT  0.144 128.683 0.162 128.759 ;
     RECT  2.415 127.643 10.206 129.235 ;
     RECT  2.376 129.235 10.206 129.569 ;
     RECT  2.415 129.569 10.206 130.621 ;
     RECT  2.376 130.621 10.206 130.747 ;
     RECT  2.304 130.747 10.206 130.919 ;
     RECT  0.108 129.259 0.126 131.549 ;
     RECT  2.415 130.919 10.206 131.665 ;
     RECT  2.304 131.665 10.206 131.819 ;
     RECT  0.54 132.667 0.558 132.809 ;
     RECT  0.144 133.819 0.162 133.889 ;
     RECT  2.415 131.819 10.206 133.997 ;
     RECT  0.54 134.347 0.558 134.429 ;
     RECT  2.415 133.997 3.006 134.761 ;
     RECT  3.852 133.997 10.206 134.761 ;
     RECT  2.415 134.761 10.206 135.095 ;
     RECT  2.415 135.095 3.006 135.301 ;
     RECT  2.34 135.301 3.006 135.481 ;
     RECT  2.304 135.481 3.006 135.599 ;
     RECT  3.852 135.095 10.206 136.021 ;
     RECT  0.108 134.923 0.126 136.109 ;
     RECT  2.34 135.599 3.006 136.111 ;
     RECT  3.816 136.021 10.206 136.111 ;
     RECT  2.34 136.111 10.206 136.409 ;
     RECT  0.54 136.651 0.558 136.787 ;
     RECT  0.108 137.191 0.126 137.261 ;
     RECT  2.415 136.409 10.206 137.335 ;
     RECT  2.304 137.335 10.206 137.489 ;
     RECT  0.54 137.803 0.558 137.939 ;
     RECT  0.108 138.379 0.126 138.479 ;
     RECT  2.415 137.489 10.206 138.811 ;
     RECT  2.304 138.811 10.206 138.983 ;
     RECT  0.54 138.907 0.558 139.019 ;
     RECT  0.144 139.483 0.162 139.559 ;
     RECT  2.415 138.983 10.206 140.035 ;
     RECT  2.304 140.035 10.206 140.225 ;
     RECT  2.376 140.225 10.206 140.909 ;
     RECT  2.415 140.909 10.206 142.079 ;
     RECT  0.108 140.059 0.126 142.397 ;
     RECT  2.415 142.079 7.038 142.747 ;
     RECT  2.376 142.747 7.038 142.861 ;
     RECT  2.304 142.861 7.038 143.033 ;
     RECT  0.54 142.891 0.558 143.069 ;
     RECT  2.415 143.033 7.038 144.085 ;
     RECT  12.672 119.467 13.497 144.085 ;
     RECT  0.54 144.043 0.558 144.149 ;
     RECT  2.304 144.085 7.038 144.239 ;
     RECT  17.928 119.707 18.897 144.239 ;
     RECT  2.415 144.239 7.038 144.661 ;
     RECT  7.815 142.079 10.206 144.661 ;
     RECT  0.144 144.619 0.162 144.689 ;
     RECT  2.415 144.661 10.206 144.689 ;
     RECT  0.108 145.192 0.126 145.229 ;
     RECT  2.415 144.689 10.134 145.741 ;
     RECT  0.144 145.741 0.162 145.805 ;
     RECT  2.376 145.741 10.134 145.859 ;
     RECT  0.108 146.347 0.126 146.399 ;
     RECT  2.412 145.859 10.134 146.821 ;
     RECT  0.54 146.821 0.558 146.909 ;
     RECT  2.376 146.821 10.134 147.209 ;
     RECT  0.108 147.451 0.126 147.488 ;
     RECT  2.376 147.209 6.57 147.631 ;
     RECT  2.304 147.631 6.57 147.785 ;
     RECT  7.308 147.209 10.134 147.929 ;
     RECT  2.415 147.785 6.57 148.019 ;
     RECT  0.54 148.027 0.558 148.127 ;
     RECT  2.415 148.019 2.97 148.531 ;
     RECT  2.304 148.531 2.97 148.865 ;
     RECT  2.415 148.865 2.97 148.981 ;
     RECT  3.852 148.019 6.57 148.981 ;
     RECT  2.415 148.981 6.57 149.071 ;
     RECT  7.308 147.929 8.097 149.071 ;
     RECT  2.415 149.071 8.097 149.099 ;
     RECT  2.415 149.099 3.078 149.279 ;
     RECT  3.852 149.099 8.097 149.513 ;
     RECT  2.415 149.279 3.006 149.909 ;
     RECT  3.852 149.513 6.462 150.259 ;
     RECT  8.82 147.929 10.134 150.359 ;
     RECT  8.856 150.359 10.134 150.485 ;
     RECT  2.415 149.909 2.97 150.727 ;
     RECT  3.708 150.259 6.462 150.727 ;
     RECT  2.415 150.727 6.462 150.871 ;
     RECT  2.415 150.871 6.498 151.339 ;
     RECT  7.308 149.513 8.097 151.375 ;
     RECT  7.272 151.375 8.097 151.411 ;
     RECT  8.856 150.485 9.702 151.411 ;
     RECT  2.304 151.339 6.498 151.501 ;
     RECT  7.272 151.411 9.702 151.501 ;
     RECT  2.304 151.501 9.702 151.529 ;
     RECT  3.744 151.529 9.702 151.565 ;
     RECT  3.744 151.565 8.097 151.601 ;
     RECT  8.856 151.565 9.702 151.637 ;
     RECT  0.108 149.179 0.126 152.045 ;
     RECT  2.304 151.529 2.97 152.311 ;
     RECT  3.744 151.601 6.462 152.311 ;
     RECT  2.304 152.311 6.462 152.987 ;
     RECT  2.415 152.987 6.462 153.149 ;
     RECT  16.164 120.479 17.01 153.149 ;
     RECT  4.716 153.149 6.462 153.571 ;
     RECT  7.308 151.601 8.097 153.571 ;
     RECT  2.415 153.149 2.97 153.805 ;
     RECT  2.304 153.805 2.97 153.931 ;
     RECT  3.852 153.149 3.87 153.931 ;
     RECT  2.304 153.931 3.87 153.959 ;
     RECT  2.415 153.959 3.87 154.345 ;
     RECT  4.716 153.571 8.097 154.345 ;
     RECT  2.415 154.345 8.097 154.535 ;
     RECT  2.415 154.535 4.266 154.571 ;
     RECT  2.415 154.571 3.006 154.741 ;
     RECT  2.304 154.741 3.006 154.913 ;
     RECT  9.684 151.637 9.702 154.921 ;
     RECT  0.54 153.163 0.558 154.949 ;
     RECT  16.164 153.149 16.938 154.949 ;
     RECT  5.112 154.535 8.097 155.039 ;
     RECT  9.684 154.921 9.918 155.039 ;
     RECT  16.236 154.949 16.938 155.039 ;
     RECT  9.684 155.039 9.702 155.047 ;
     RECT  8.856 151.637 8.874 155.155 ;
     RECT  9.648 155.047 9.702 155.155 ;
     RECT  2.415 154.913 3.006 155.461 ;
     RECT  0.144 155.419 0.162 155.489 ;
     RECT  2.415 155.461 3.078 155.821 ;
     RECT  3.852 154.571 4.266 155.821 ;
     RECT  5.184 155.039 8.097 156.173 ;
     RECT  2.415 155.821 4.266 156.427 ;
     RECT  5.184 156.173 6.462 156.427 ;
     RECT  8.856 155.155 9.702 156.461 ;
     RECT  2.415 156.427 6.462 156.505 ;
     RECT  2.304 156.505 6.462 156.659 ;
     RECT  0.108 155.992 0.126 157.181 ;
     RECT  2.415 156.659 6.462 157.199 ;
     RECT  2.415 157.199 3.078 157.271 ;
     RECT  7.815 156.173 8.097 157.483 ;
     RECT  3.852 157.199 6.462 157.901 ;
     RECT  3.852 157.901 4.59 157.981 ;
     RECT  2.415 157.271 2.898 158.125 ;
     RECT  3.816 157.981 4.59 158.125 ;
     RECT  7.704 157.483 8.097 158.125 ;
     RECT  7.524 158.125 8.097 158.161 ;
     RECT  8.856 156.461 9.666 158.161 ;
     RECT  7.524 158.161 9.666 158.189 ;
     RECT  2.415 158.125 4.59 158.251 ;
     RECT  7.815 158.189 9.666 158.351 ;
     RECT  2.304 158.251 4.59 158.819 ;
     RECT  2.304 158.819 3.474 158.963 ;
     RECT  2.415 158.963 3.474 159.005 ;
     RECT  4.392 158.819 4.59 159.431 ;
     RECT  7.815 158.351 8.097 159.643 ;
     RECT  2.415 159.005 3.438 159.665 ;
     RECT  5.4 157.901 6.462 159.935 ;
     RECT  7.524 159.643 8.097 160.051 ;
     RECT  0.54 157.723 0.558 160.079 ;
     RECT  6.588 160.051 8.097 160.241 ;
     RECT  2.415 159.665 2.934 160.591 ;
     RECT  7.38 160.241 8.097 160.591 ;
     RECT  8.856 158.351 9.666 160.591 ;
     RECT  7.38 160.591 9.666 160.592 ;
     RECT  0.108 160.555 0.126 160.619 ;
     RECT  4.5 159.431 4.59 160.681 ;
     RECT  7.815 160.592 9.666 160.745 ;
     RECT  6.588 160.241 6.606 160.979 ;
     RECT  4.428 160.681 4.59 161.095 ;
     RECT  5.4 159.935 5.85 161.131 ;
     RECT  4.392 161.095 4.59 161.165 ;
     RECT  2.415 160.591 2.97 161.221 ;
     RECT  5.364 161.131 5.85 161.221 ;
     RECT  6.732 161.131 6.75 161.249 ;
     RECT  2.415 161.221 3.006 161.321 ;
     RECT  0.54 161.125 0.558 161.741 ;
     RECT  4.824 161.221 5.85 161.761 ;
     RECT  4.824 161.761 6.246 161.837 ;
     RECT  6.228 161.837 6.246 162.203 ;
     RECT  4.824 161.837 5.418 164.489 ;
     RECT  3.924 164.533 3.942 164.569 ;
     RECT  2.415 161.321 2.898 164.587 ;
     RECT  3.924 164.569 3.978 164.605 ;
     RECT  2.34 164.587 2.898 164.641 ;
     RECT  3.78 164.605 3.978 164.803 ;
     RECT  2.304 164.641 2.898 164.839 ;
     RECT  3.708 164.803 3.978 164.839 ;
     RECT  16.236 155.039 16.362 164.939 ;
     RECT  12.564 144.085 13.497 165.407 ;
     RECT  12.708 165.407 13.497 165.479 ;
     RECT  2.304 164.839 3.978 165.577 ;
     RECT  2.304 165.577 4.05 165.605 ;
     RECT  13.032 165.479 13.497 165.605 ;
     RECT  8.856 160.745 9.666 165.839 ;
     RECT  2.376 165.605 4.05 165.847 ;
     RECT  2.376 165.847 4.122 166.109 ;
     RECT  16.344 164.939 16.362 166.181 ;
     RECT  2.376 166.109 3.978 166.253 ;
     RECT  10.656 152.455 10.674 166.379 ;
     RECT  2.376 166.253 3.762 166.387 ;
     RECT  11.664 153.265 11.682 166.649 ;
     RECT  5.4 164.489 5.418 166.829 ;
     RECT  9.396 165.839 9.666 166.919 ;
     RECT  9.648 166.919 9.666 167.189 ;
     RECT  2.304 166.387 3.762 168.809 ;
     RECT  2.304 168.809 3.438 169.385 ;
     RECT  2.34 169.385 3.438 169.421 ;
     RECT  0.108 169.195 0.126 169.435 ;
     RECT  3.42 169.421 3.438 169.469 ;
     RECT  0.108 169.435 0.162 169.613 ;
     RECT  2.34 169.421 2.697 169.757 ;
     RECT  0.108 169.613 0.126 169.949 ;
     RECT  2.415 169.757 2.697 170.387 ;
     RECT  7.815 160.745 8.097 170.387 ;
     RECT  13.215 165.605 13.497 170.387 ;
     RECT  18.615 144.239 18.897 170.387 ;
     RECT  24.015 123.373 24.297 170.387 ;
     RECT  29.415 123.373 29.697 170.387 ;
     RECT  34.815 123.373 35.097 170.387 ;
     RECT  40.215 123.373 40.497 170.387 ;
     RECT  45.615 123.373 45.897 170.387 ;
     RECT  51.015 123.373 51.297 170.387 ;
     RECT  56.415 123.373 56.697 170.387 ;
     RECT  61.815 123.373 62.097 170.387 ;
     RECT  67.215 123.373 67.497 170.387 ;
     RECT  72.615 123.373 72.897 170.387 ;
     RECT  78.015 123.373 78.297 170.387 ;
     RECT  83.415 123.373 83.697 170.387 ;
     RECT  88.815 123.373 89.097 170.387 ;
     RECT  94.215 123.373 94.497 170.387 ;
     RECT  99.615 123.373 99.897 170.387 ;
     RECT  105.015 123.373 105.297 170.387 ;
     RECT  110.415 123.373 110.697 170.387 ;
     RECT  115.815 123.373 116.097 170.387 ;
     RECT  121.215 123.373 121.497 170.387 ;
     RECT  126.615 123.373 126.897 170.387 ;
     RECT  132.015 123.373 132.297 170.387 ;
     RECT  137.415 123.373 137.697 170.387 ;
     RECT  142.815 123.373 143.097 170.387 ;
     RECT  148.215 123.373 148.497 170.387 ;
     RECT  153.615 123.373 153.897 170.387 ;
     RECT  159.015 123.373 159.297 170.387 ;
     RECT  164.415 123.373 164.697 170.387 ;
     RECT  169.815 123.373 170.097 170.387 ;
     RECT  175.215 123.373 175.497 170.387 ;
     RECT  180.615 123.373 180.897 170.387 ;
     RECT  186.015 123.373 186.297 170.387 ;
     RECT  191.415 123.373 191.697 170.387 ;
     RECT  196.815 120.785 197.097 170.387 ;
     RECT  202.215 2.413 202.497 170.387 ;
     RECT  207.615 2.413 207.897 170.387 ;
     RECT  213.015 2.413 213.297 170.387 ;
     RECT  2.415 170.387 2.505 170.657 ;
     RECT  7.815 170.387 7.905 170.657 ;
     RECT  13.215 170.387 13.305 170.657 ;
     RECT  18.615 170.387 18.705 170.657 ;
     RECT  24.015 170.387 24.105 170.657 ;
     RECT  29.415 170.387 29.505 170.657 ;
     RECT  34.815 170.387 34.905 170.657 ;
     RECT  40.215 170.387 40.305 170.657 ;
     RECT  45.615 170.387 45.705 170.657 ;
     RECT  51.015 170.387 51.105 170.657 ;
     RECT  56.415 170.387 56.505 170.657 ;
     RECT  61.815 170.387 61.905 170.657 ;
     RECT  67.215 170.387 67.305 170.657 ;
     RECT  72.615 170.387 72.705 170.657 ;
     RECT  78.015 170.387 78.105 170.657 ;
     RECT  83.415 170.387 83.505 170.657 ;
     RECT  88.815 170.387 88.905 170.657 ;
     RECT  94.215 170.387 94.305 170.657 ;
     RECT  99.615 170.387 99.705 170.657 ;
     RECT  105.015 170.387 105.105 170.657 ;
     RECT  110.415 170.387 110.505 170.657 ;
     RECT  115.815 170.387 115.905 170.657 ;
     RECT  121.215 170.387 121.305 170.657 ;
     RECT  126.615 170.387 126.705 170.657 ;
     RECT  132.015 170.387 132.105 170.657 ;
     RECT  137.415 170.387 137.505 170.657 ;
     RECT  142.815 170.387 142.905 170.657 ;
     RECT  148.215 170.387 148.305 170.657 ;
     RECT  153.615 170.387 153.705 170.657 ;
     RECT  159.015 170.387 159.105 170.657 ;
     RECT  164.415 170.387 164.505 170.657 ;
     RECT  169.815 170.387 169.905 170.657 ;
     RECT  175.215 170.387 175.305 170.657 ;
     RECT  180.615 170.387 180.705 170.657 ;
     RECT  186.015 170.387 186.105 170.657 ;
     RECT  191.415 170.387 191.505 170.657 ;
     RECT  196.815 170.387 196.905 170.657 ;
     RECT  202.215 170.387 202.305 170.657 ;
     RECT  207.615 170.387 207.705 170.657 ;
     RECT  213.015 170.387 213.105 170.657 ;
    LAYER M4 ;
     RECT  0.084 166.08 0.133 166.104 ;
     RECT  0.06 166.104 0.133 166.224 ;
     RECT  0.084 166.224 0.133 166.248 ;
     RECT  0.06 166.248 0.133 166.416 ;
     RECT  0.084 166.416 0.133 166.44 ;
     RECT  0.06 166.44 0.133 166.56 ;
     RECT  0.084 166.56 0.133 166.584 ;
     RECT  0.06 166.584 0.133 166.752 ;
     RECT  0.084 166.752 0.133 166.776 ;
     RECT  0.06 166.776 0.133 166.896 ;
     RECT  0.084 166.896 0.133 166.92 ;
     RECT  0.084 8.256 0.137 8.28 ;
     RECT  0.06 8.28 0.137 8.736 ;
     RECT  0.084 8.736 0.137 8.76 ;
     RECT  0.06 8.76 0.137 9.216 ;
     RECT  0.084 9.216 0.137 9.24 ;
     RECT  0.06 9.24 0.137 9.744 ;
     RECT  0.084 9.744 0.137 9.768 ;
     RECT  0.06 9.768 0.137 10.224 ;
     RECT  0.084 10.224 0.137 10.248 ;
     RECT  0.06 10.248 0.137 10.704 ;
     RECT  0.084 10.704 0.137 10.728 ;
     RECT  0.06 10.728 0.137 11.232 ;
     RECT  0.084 11.232 0.137 11.256 ;
     RECT  0.06 11.256 0.137 11.712 ;
     RECT  0.084 11.712 0.137 11.736 ;
     RECT  0.06 11.736 0.137 12.192 ;
     RECT  0.084 12.192 0.137 12.216 ;
     RECT  0.06 12.216 0.137 12.72 ;
     RECT  0.084 12.72 0.137 12.744 ;
     RECT  0.06 12.744 0.137 13.2 ;
     RECT  0.084 13.2 0.137 13.224 ;
     RECT  0.06 13.224 0.137 13.68 ;
     RECT  0.084 13.68 0.137 13.704 ;
     RECT  0.06 13.704 0.137 14.208 ;
     RECT  0.084 14.208 0.137 14.232 ;
     RECT  0.06 14.232 0.137 14.688 ;
     RECT  0.084 14.688 0.137 14.712 ;
     RECT  0.06 14.712 0.137 15.168 ;
     RECT  0.084 15.168 0.137 15.192 ;
     RECT  0.06 15.192 0.137 15.696 ;
     RECT  0.084 15.696 0.137 15.72 ;
     RECT  0.06 15.72 0.137 16.176 ;
     RECT  0.084 16.176 0.137 16.2 ;
     RECT  0.06 16.2 0.137 16.656 ;
     RECT  0.084 16.656 0.137 16.68 ;
     RECT  0.06 16.68 0.137 17.184 ;
     RECT  0.084 17.184 0.137 17.208 ;
     RECT  0.06 17.208 0.137 17.664 ;
     RECT  0.084 17.664 0.137 17.688 ;
     RECT  0.06 17.688 0.137 18.144 ;
     RECT  0.084 18.144 0.137 18.168 ;
     RECT  0.06 18.168 0.137 18.672 ;
     RECT  0.084 18.672 0.137 18.696 ;
     RECT  0.06 18.696 0.137 19.152 ;
     RECT  0.084 19.152 0.137 19.176 ;
     RECT  0.06 19.176 0.137 19.632 ;
     RECT  0.084 19.632 0.137 19.656 ;
     RECT  0.06 19.656 0.137 20.16 ;
     RECT  0.084 20.16 0.137 20.184 ;
     RECT  0.06 20.184 0.137 20.64 ;
     RECT  0.084 20.64 0.137 20.664 ;
     RECT  0.06 20.664 0.137 21.12 ;
     RECT  0.084 21.12 0.137 21.144 ;
     RECT  0.06 21.144 0.137 21.648 ;
     RECT  0.084 21.648 0.137 21.672 ;
     RECT  0.06 21.672 0.137 22.128 ;
     RECT  0.084 22.128 0.137 22.152 ;
     RECT  0.06 22.152 0.137 22.608 ;
     RECT  0.084 22.608 0.137 22.632 ;
     RECT  0.06 22.632 0.137 23.136 ;
     RECT  0.084 23.136 0.137 23.16 ;
     RECT  0.06 23.16 0.137 23.616 ;
     RECT  0.084 23.616 0.137 23.64 ;
     RECT  0.06 23.64 0.137 24.096 ;
     RECT  0.084 24.096 0.137 24.12 ;
     RECT  0.06 24.12 0.137 24.624 ;
     RECT  0.084 24.624 0.137 24.648 ;
     RECT  0.06 24.648 0.137 25.104 ;
     RECT  0.084 25.104 0.137 25.128 ;
     RECT  0.06 25.128 0.137 25.632 ;
     RECT  0.084 25.632 0.137 25.656 ;
     RECT  0.06 25.656 0.137 26.112 ;
     RECT  0.084 26.112 0.137 26.136 ;
     RECT  0.06 26.136 0.137 26.592 ;
     RECT  0.084 26.592 0.137 26.616 ;
     RECT  0.06 26.616 0.137 27.12 ;
     RECT  0.084 27.12 0.137 27.144 ;
     RECT  0.06 27.144 0.137 27.6 ;
     RECT  0.084 27.6 0.137 27.624 ;
     RECT  0.06 27.624 0.137 28.08 ;
     RECT  0.084 28.08 0.137 28.104 ;
     RECT  0.06 28.104 0.137 28.608 ;
     RECT  0.084 28.608 0.137 28.632 ;
     RECT  0.06 28.632 0.137 29.088 ;
     RECT  0.084 29.088 0.137 29.112 ;
     RECT  0.06 29.112 0.137 29.568 ;
     RECT  0.084 29.568 0.137 29.592 ;
     RECT  0.06 29.592 0.137 30.096 ;
     RECT  0.084 30.096 0.137 30.12 ;
     RECT  0.06 30.12 0.137 30.576 ;
     RECT  0.084 30.576 0.137 30.6 ;
     RECT  0.06 30.6 0.137 31.056 ;
     RECT  0.084 31.056 0.137 31.08 ;
     RECT  0.06 31.08 0.137 31.584 ;
     RECT  0.084 31.584 0.137 31.608 ;
     RECT  0.06 31.608 0.137 32.064 ;
     RECT  0.084 32.064 0.137 32.088 ;
     RECT  0.06 32.088 0.137 32.544 ;
     RECT  0.084 32.544 0.137 32.568 ;
     RECT  0.06 32.568 0.137 33.072 ;
     RECT  0.084 33.072 0.137 33.096 ;
     RECT  0.06 33.096 0.137 33.552 ;
     RECT  0.084 33.552 0.137 33.576 ;
     RECT  0.06 33.576 0.137 34.032 ;
     RECT  0.084 34.032 0.137 34.056 ;
     RECT  0.06 34.056 0.137 34.56 ;
     RECT  0.084 34.56 0.137 34.584 ;
     RECT  0.06 34.584 0.137 35.04 ;
     RECT  0.084 35.04 0.137 35.064 ;
     RECT  0.06 35.064 0.137 35.52 ;
     RECT  0.084 35.52 0.137 35.544 ;
     RECT  0.06 35.544 0.137 36.048 ;
     RECT  0.084 36.048 0.137 36.072 ;
     RECT  0.06 36.072 0.137 36.528 ;
     RECT  0.084 36.528 0.137 36.552 ;
     RECT  0.06 36.552 0.137 37.008 ;
     RECT  0.084 37.008 0.137 37.032 ;
     RECT  0.06 37.032 0.137 37.536 ;
     RECT  0.084 37.536 0.137 37.56 ;
     RECT  0.06 37.56 0.137 38.016 ;
     RECT  0.084 38.016 0.137 38.04 ;
     RECT  0.06 38.04 0.137 38.496 ;
     RECT  0.084 38.496 0.137 38.52 ;
     RECT  0.06 38.52 0.137 39.024 ;
     RECT  0.084 39.024 0.137 39.048 ;
     RECT  0.06 39.048 0.137 39.504 ;
     RECT  0.084 39.504 0.137 39.528 ;
     RECT  0.06 39.528 0.137 39.984 ;
     RECT  0.084 39.984 0.137 40.008 ;
     RECT  0.06 40.008 0.137 40.512 ;
     RECT  0.084 40.512 0.137 40.536 ;
     RECT  0.06 40.536 0.137 40.992 ;
     RECT  0.084 40.992 0.137 41.016 ;
     RECT  0.06 41.016 0.137 41.472 ;
     RECT  0.084 41.472 0.137 41.496 ;
     RECT  0.06 41.496 0.137 42 ;
     RECT  0.084 42 0.137 42.024 ;
     RECT  0.06 42.024 0.137 42.48 ;
     RECT  0.084 42.48 0.137 42.504 ;
     RECT  0.06 42.504 0.137 42.96 ;
     RECT  0.084 42.96 0.137 42.984 ;
     RECT  0.06 42.984 0.137 43.488 ;
     RECT  0.084 43.488 0.137 43.512 ;
     RECT  0.06 43.512 0.137 43.968 ;
     RECT  0.084 43.968 0.137 43.992 ;
     RECT  0.06 43.992 0.137 44.448 ;
     RECT  0.084 44.448 0.137 44.472 ;
     RECT  0.06 44.472 0.137 44.976 ;
     RECT  0.084 44.976 0.137 45 ;
     RECT  0.06 45 0.137 45.456 ;
     RECT  0.084 45.456 0.137 45.48 ;
     RECT  0.06 45.48 0.137 45.936 ;
     RECT  0.084 45.936 0.137 45.96 ;
     RECT  0.06 45.96 0.137 46.464 ;
     RECT  0.084 46.464 0.137 46.488 ;
     RECT  0.06 46.488 0.137 46.944 ;
     RECT  0.084 46.944 0.137 46.968 ;
     RECT  0.06 46.968 0.137 47.472 ;
     RECT  0.084 47.472 0.137 47.496 ;
     RECT  0.06 47.496 0.137 47.952 ;
     RECT  0.084 47.952 0.137 47.976 ;
     RECT  0.06 47.976 0.137 48.432 ;
     RECT  0.084 48.432 0.137 48.456 ;
     RECT  0.06 48.456 0.137 48.96 ;
     RECT  0.084 48.96 0.137 48.984 ;
     RECT  0.06 48.984 0.137 49.44 ;
     RECT  0.084 49.44 0.137 49.464 ;
     RECT  0.06 49.464 0.137 49.92 ;
     RECT  0.084 49.92 0.137 49.944 ;
     RECT  0.06 49.944 0.137 50.448 ;
     RECT  0.084 50.448 0.137 50.472 ;
     RECT  0.06 50.472 0.137 50.928 ;
     RECT  0.084 50.928 0.137 50.952 ;
     RECT  0.06 50.952 0.137 51.408 ;
     RECT  0.084 51.408 0.137 51.432 ;
     RECT  0.06 51.432 0.137 51.936 ;
     RECT  0.084 51.936 0.137 51.96 ;
     RECT  0.06 51.96 0.137 52.416 ;
     RECT  0.084 52.416 0.137 52.44 ;
     RECT  0.06 52.44 0.137 52.896 ;
     RECT  0.084 52.896 0.137 52.92 ;
     RECT  0.06 52.92 0.137 53.424 ;
     RECT  0.084 53.424 0.137 53.448 ;
     RECT  0.06 53.448 0.137 53.904 ;
     RECT  0.084 53.904 0.137 53.928 ;
     RECT  0.06 53.928 0.137 54.384 ;
     RECT  0.084 54.384 0.137 54.408 ;
     RECT  0.06 54.408 0.137 54.912 ;
     RECT  0.084 54.912 0.137 54.936 ;
     RECT  0.06 54.936 0.137 55.392 ;
     RECT  0.084 55.392 0.137 55.416 ;
     RECT  0.06 55.416 0.137 55.872 ;
     RECT  0.084 55.872 0.137 55.896 ;
     RECT  0.06 55.896 0.137 56.4 ;
     RECT  0.084 56.4 0.137 56.424 ;
     RECT  0.06 56.424 0.137 56.88 ;
     RECT  0.084 56.88 0.137 56.904 ;
     RECT  0.06 56.904 0.137 57.36 ;
     RECT  0.084 57.36 0.137 57.384 ;
     RECT  0.06 57.384 0.137 57.888 ;
     RECT  0.084 57.888 0.137 57.912 ;
     RECT  0.06 57.912 0.137 58.368 ;
     RECT  0.084 58.368 0.137 58.392 ;
     RECT  0.06 58.392 0.137 58.848 ;
     RECT  0.084 58.848 0.137 58.872 ;
     RECT  0.06 58.872 0.137 59.376 ;
     RECT  0.084 59.376 0.137 59.4 ;
     RECT  0.06 59.4 0.137 59.856 ;
     RECT  0.084 59.856 0.137 59.88 ;
     RECT  0.06 59.88 0.137 60.336 ;
     RECT  0.084 60.336 0.137 60.36 ;
     RECT  0.06 60.36 0.137 60.864 ;
     RECT  0.084 60.864 0.137 60.888 ;
     RECT  0.06 60.888 0.137 61.344 ;
     RECT  0.084 61.344 0.137 61.368 ;
     RECT  0.06 61.368 0.137 61.824 ;
     RECT  0.084 61.824 0.137 61.848 ;
     RECT  0.06 61.848 0.137 62.352 ;
     RECT  0.084 62.352 0.137 62.376 ;
     RECT  0.06 62.376 0.137 62.832 ;
     RECT  0.084 62.832 0.137 62.856 ;
     RECT  0.06 62.856 0.137 63.312 ;
     RECT  0.084 63.312 0.137 63.336 ;
     RECT  0.06 63.336 0.137 63.84 ;
     RECT  0.084 63.84 0.137 63.864 ;
     RECT  0.06 63.864 0.137 64.32 ;
     RECT  0.084 64.32 0.137 64.344 ;
     RECT  0.06 64.344 0.137 64.8 ;
     RECT  0.084 64.8 0.137 64.824 ;
     RECT  0.06 64.824 0.137 65.328 ;
     RECT  0.084 65.328 0.137 65.352 ;
     RECT  0.06 65.352 0.137 65.808 ;
     RECT  0.084 65.808 0.137 65.832 ;
     RECT  0.06 65.832 0.137 66.288 ;
     RECT  0.084 66.288 0.137 66.312 ;
     RECT  0.06 66.312 0.137 66.816 ;
     RECT  0.084 66.816 0.137 66.84 ;
     RECT  0.06 66.84 0.137 67.296 ;
     RECT  0.084 67.296 0.137 67.32 ;
     RECT  0.06 67.32 0.137 67.776 ;
     RECT  0.084 67.776 0.137 67.8 ;
     RECT  0.06 67.8 0.137 68.304 ;
     RECT  0.084 68.304 0.137 68.328 ;
     RECT  0.06 68.328 0.137 68.784 ;
     RECT  0.084 68.784 0.137 68.808 ;
     RECT  0.06 68.808 0.137 69.264 ;
     RECT  0.084 69.264 0.137 69.288 ;
     RECT  0.06 69.288 0.137 69.792 ;
     RECT  0.084 69.792 0.137 69.816 ;
     RECT  0.06 69.816 0.137 70.272 ;
     RECT  0.084 70.272 0.137 70.296 ;
     RECT  0.06 70.296 0.137 70.8 ;
     RECT  0.084 70.8 0.137 70.824 ;
     RECT  0.06 70.824 0.137 71.28 ;
     RECT  0.084 71.28 0.137 71.304 ;
     RECT  0.06 71.304 0.137 71.76 ;
     RECT  0.084 71.76 0.137 71.784 ;
     RECT  0.06 71.784 0.137 72.288 ;
     RECT  0.084 72.288 0.137 72.312 ;
     RECT  0.06 72.312 0.137 72.768 ;
     RECT  0.084 72.768 0.137 72.792 ;
     RECT  0.06 72.792 0.137 73.248 ;
     RECT  0.084 73.248 0.137 73.272 ;
     RECT  0.06 73.272 0.137 73.776 ;
     RECT  0.084 73.776 0.137 73.8 ;
     RECT  0.06 73.8 0.137 74.256 ;
     RECT  0.084 74.256 0.137 74.28 ;
     RECT  0.06 74.28 0.137 74.736 ;
     RECT  0.084 74.736 0.137 74.76 ;
     RECT  0.06 74.76 0.137 75.264 ;
     RECT  0.084 75.264 0.137 75.288 ;
     RECT  0.06 75.288 0.137 75.744 ;
     RECT  0.084 75.744 0.137 75.768 ;
     RECT  0.084 84.288 0.137 84.312 ;
     RECT  0.06 84.312 0.137 84.864 ;
     RECT  0.084 84.864 0.137 84.888 ;
     RECT  0.06 84.888 0.137 85.392 ;
     RECT  0.084 85.392 0.137 85.416 ;
     RECT  0.06 85.416 0.137 85.968 ;
     RECT  0.084 85.968 0.137 85.992 ;
     RECT  0.06 85.992 0.137 86.544 ;
     RECT  0.084 86.544 0.137 86.568 ;
     RECT  0.06 86.568 0.137 87.12 ;
     RECT  0.084 87.12 0.137 87.144 ;
     RECT  0.06 87.144 0.137 87.696 ;
     RECT  0.084 87.696 0.137 87.72 ;
     RECT  0.06 87.72 0.137 88.272 ;
     RECT  0.084 88.272 0.137 88.296 ;
     RECT  0.06 88.296 0.137 88.848 ;
     RECT  0.084 88.848 0.137 88.872 ;
     RECT  0.06 88.872 0.137 89.376 ;
     RECT  0.084 89.376 0.137 89.4 ;
     RECT  0.06 89.4 0.137 89.952 ;
     RECT  0.084 89.952 0.137 89.976 ;
     RECT  0.06 89.976 0.137 90.528 ;
     RECT  0.084 90.528 0.137 90.552 ;
     RECT  0.06 90.552 0.137 91.104 ;
     RECT  0.084 91.104 0.137 91.128 ;
     RECT  0.06 91.128 0.137 91.68 ;
     RECT  0.084 91.68 0.137 91.704 ;
     RECT  0.06 91.704 0.137 92.256 ;
     RECT  0.084 92.256 0.137 92.28 ;
     RECT  0.06 92.28 0.137 92.832 ;
     RECT  0.084 92.832 0.137 92.856 ;
     RECT  0.06 92.856 0.137 93.36 ;
     RECT  0.084 93.36 0.137 93.384 ;
     RECT  0.06 93.384 0.137 93.936 ;
     RECT  0.084 93.936 0.137 93.96 ;
     RECT  0.06 93.96 0.137 94.512 ;
     RECT  0.084 94.512 0.137 94.536 ;
     RECT  0.06 94.536 0.137 95.088 ;
     RECT  0.084 95.088 0.137 95.112 ;
     RECT  0.06 95.112 0.137 95.664 ;
     RECT  0.084 95.664 0.137 95.688 ;
     RECT  0.06 95.688 0.137 96.24 ;
     RECT  0.084 96.24 0.137 96.264 ;
     RECT  0.06 96.264 0.137 96.816 ;
     RECT  0.084 96.816 0.137 96.84 ;
     RECT  0.06 96.84 0.137 97.392 ;
     RECT  0.084 97.392 0.137 97.416 ;
     RECT  0.06 97.416 0.137 97.92 ;
     RECT  0.084 97.92 0.137 97.944 ;
     RECT  0.06 97.944 0.137 98.496 ;
     RECT  0.084 98.496 0.137 98.52 ;
     RECT  0.06 98.52 0.137 99.072 ;
     RECT  0.084 99.072 0.137 99.096 ;
     RECT  0.06 99.096 0.137 99.648 ;
     RECT  0.084 99.648 0.137 99.672 ;
     RECT  0.06 99.672 0.137 100.224 ;
     RECT  0.084 100.224 0.137 100.248 ;
     RECT  0.06 100.248 0.137 100.8 ;
     RECT  0.084 100.8 0.137 100.824 ;
     RECT  0.06 100.824 0.137 101.376 ;
     RECT  0.084 101.376 0.137 101.4 ;
     RECT  0.06 101.4 0.137 101.904 ;
     RECT  0.084 101.904 0.137 101.928 ;
     RECT  0.06 101.928 0.137 102.48 ;
     RECT  0.084 102.48 0.137 102.504 ;
     RECT  0.06 102.504 0.137 103.056 ;
     RECT  0.084 103.056 0.137 103.08 ;
     RECT  0.06 103.08 0.137 103.632 ;
     RECT  0.084 103.632 0.137 103.656 ;
     RECT  0.06 103.656 0.137 104.208 ;
     RECT  0.084 104.208 0.137 104.232 ;
     RECT  0.06 104.232 0.137 104.784 ;
     RECT  0.084 104.784 0.137 104.808 ;
     RECT  0.06 104.808 0.137 105.36 ;
     RECT  0.084 105.36 0.137 105.384 ;
     RECT  0.06 105.384 0.137 105.888 ;
     RECT  0.084 105.888 0.137 105.912 ;
     RECT  0.06 105.912 0.137 106.464 ;
     RECT  0.084 106.464 0.137 106.488 ;
     RECT  0.06 106.488 0.137 107.04 ;
     RECT  0.084 107.04 0.137 107.064 ;
     RECT  0.06 107.064 0.137 107.616 ;
     RECT  0.084 107.616 0.137 107.64 ;
     RECT  0.06 107.64 0.137 108.192 ;
     RECT  0.084 108.192 0.137 108.216 ;
     RECT  0.06 108.216 0.137 108.768 ;
     RECT  0.084 108.768 0.137 108.792 ;
     RECT  0.06 108.792 0.137 109.344 ;
     RECT  0.084 109.344 0.137 109.368 ;
     RECT  0.06 109.368 0.137 109.872 ;
     RECT  0.084 109.872 0.137 109.896 ;
     RECT  0.06 109.896 0.137 110.448 ;
     RECT  0.084 110.448 0.137 110.472 ;
     RECT  0.06 110.472 0.137 111.024 ;
     RECT  0.084 111.024 0.137 111.048 ;
     RECT  0.06 111.048 0.137 111.6 ;
     RECT  0.084 111.6 0.137 111.624 ;
     RECT  0.06 111.624 0.137 112.176 ;
     RECT  0.084 112.176 0.137 112.2 ;
     RECT  0.06 112.2 0.137 112.752 ;
     RECT  0.084 112.752 0.137 112.776 ;
     RECT  0.06 112.776 0.137 113.328 ;
     RECT  0.084 113.328 0.137 113.352 ;
     RECT  0.06 113.352 0.137 113.856 ;
     RECT  0.084 113.856 0.137 113.88 ;
     RECT  0.06 113.88 0.137 114.432 ;
     RECT  0.084 114.432 0.137 114.456 ;
     RECT  0.06 114.456 0.137 115.008 ;
     RECT  0.084 115.008 0.137 115.032 ;
     RECT  0.06 115.032 0.137 115.584 ;
     RECT  0.084 115.584 0.137 115.608 ;
     RECT  0.06 115.608 0.137 116.16 ;
     RECT  0.084 116.16 0.137 116.184 ;
     RECT  0.06 116.184 0.137 116.736 ;
     RECT  0.084 116.736 0.137 116.76 ;
     RECT  0.06 116.76 0.137 117.312 ;
     RECT  0.084 117.312 0.137 117.336 ;
     RECT  0.06 117.336 0.137 117.888 ;
     RECT  0.084 117.888 0.137 117.912 ;
     RECT  0.06 117.912 0.137 118.416 ;
     RECT  0.084 118.416 0.137 118.44 ;
     RECT  0.06 118.44 0.137 118.992 ;
     RECT  0.084 118.992 0.137 119.016 ;
     RECT  0.06 119.016 0.137 119.568 ;
     RECT  0.084 119.568 0.137 119.592 ;
     RECT  0.06 119.592 0.137 120.144 ;
     RECT  0.084 120.144 0.137 120.168 ;
     RECT  0.06 120.168 0.137 120.72 ;
     RECT  0.084 120.72 0.137 120.744 ;
     RECT  0.06 120.744 0.137 121.296 ;
     RECT  0.084 121.296 0.137 121.32 ;
     RECT  0.06 121.32 0.137 121.872 ;
     RECT  0.084 121.872 0.137 121.896 ;
     RECT  0.06 121.896 0.137 122.4 ;
     RECT  0.084 122.4 0.137 122.424 ;
     RECT  0.06 122.424 0.137 122.976 ;
     RECT  0.084 122.976 0.137 123 ;
     RECT  0.06 123 0.137 123.552 ;
     RECT  0.084 123.552 0.137 123.576 ;
     RECT  0.06 123.576 0.137 124.128 ;
     RECT  0.084 124.128 0.137 124.152 ;
     RECT  0.06 124.152 0.137 124.704 ;
     RECT  0.084 124.704 0.137 124.728 ;
     RECT  0.06 124.728 0.137 125.28 ;
     RECT  0.084 125.28 0.137 125.304 ;
     RECT  0.06 125.304 0.137 125.856 ;
     RECT  0.084 125.856 0.137 125.88 ;
     RECT  0.06 125.88 0.137 126.384 ;
     RECT  0.084 126.384 0.137 126.408 ;
     RECT  0.06 126.408 0.137 126.96 ;
     RECT  0.084 126.96 0.137 126.984 ;
     RECT  0.06 126.984 0.137 127.536 ;
     RECT  0.084 127.536 0.137 127.56 ;
     RECT  0.06 127.56 0.137 128.112 ;
     RECT  0.084 128.112 0.137 128.136 ;
     RECT  0.06 128.136 0.137 128.688 ;
     RECT  0.084 128.688 0.137 128.712 ;
     RECT  0.06 128.712 0.137 129.264 ;
     RECT  0.084 129.264 0.137 129.288 ;
     RECT  0.06 129.288 0.137 129.84 ;
     RECT  0.084 129.84 0.137 129.864 ;
     RECT  0.06 129.864 0.137 130.368 ;
     RECT  0.084 130.368 0.137 130.392 ;
     RECT  0.06 130.392 0.137 130.944 ;
     RECT  0.084 130.944 0.137 130.968 ;
     RECT  0.06 130.968 0.137 131.52 ;
     RECT  0.084 131.52 0.137 131.544 ;
     RECT  0.06 131.544 0.137 132.096 ;
     RECT  0.084 132.096 0.137 132.12 ;
     RECT  0.06 132.12 0.137 132.672 ;
     RECT  0.084 132.672 0.137 132.696 ;
     RECT  0.06 132.696 0.137 133.248 ;
     RECT  0.084 133.248 0.137 133.272 ;
     RECT  0.06 133.272 0.137 133.824 ;
     RECT  0.084 133.824 0.137 133.848 ;
     RECT  0.06 133.848 0.137 134.352 ;
     RECT  0.084 134.352 0.137 134.376 ;
     RECT  0.06 134.376 0.137 134.928 ;
     RECT  0.084 134.928 0.137 134.952 ;
     RECT  0.06 134.952 0.137 135.504 ;
     RECT  0.084 135.504 0.137 135.528 ;
     RECT  0.06 135.528 0.137 136.08 ;
     RECT  0.084 136.08 0.137 136.104 ;
     RECT  0.06 136.104 0.137 136.656 ;
     RECT  0.084 136.656 0.137 136.68 ;
     RECT  0.06 136.68 0.137 137.232 ;
     RECT  0.084 137.232 0.137 137.256 ;
     RECT  0.06 137.256 0.137 137.808 ;
     RECT  0.084 137.808 0.137 137.832 ;
     RECT  0.06 137.832 0.137 138.384 ;
     RECT  0.084 138.384 0.137 138.408 ;
     RECT  0.06 138.408 0.137 138.912 ;
     RECT  0.084 138.912 0.137 138.936 ;
     RECT  0.06 138.936 0.137 139.488 ;
     RECT  0.084 139.488 0.137 139.512 ;
     RECT  0.06 139.512 0.137 140.064 ;
     RECT  0.084 140.064 0.137 140.088 ;
     RECT  0.06 140.088 0.137 140.64 ;
     RECT  0.084 140.64 0.137 140.664 ;
     RECT  0.06 140.664 0.137 141.216 ;
     RECT  0.084 141.216 0.137 141.24 ;
     RECT  0.06 141.24 0.137 141.792 ;
     RECT  0.084 141.792 0.137 141.816 ;
     RECT  0.06 141.816 0.137 142.368 ;
     RECT  0.084 142.368 0.137 142.392 ;
     RECT  0.06 142.392 0.137 142.896 ;
     RECT  0.084 142.896 0.137 142.92 ;
     RECT  0.06 142.92 0.137 143.472 ;
     RECT  0.084 143.472 0.137 143.496 ;
     RECT  0.06 143.496 0.137 144.048 ;
     RECT  0.084 144.048 0.137 144.072 ;
     RECT  0.06 144.072 0.137 144.624 ;
     RECT  0.084 144.624 0.137 144.648 ;
     RECT  0.06 144.648 0.137 145.2 ;
     RECT  0.084 145.2 0.137 145.224 ;
     RECT  0.06 145.224 0.137 145.776 ;
     RECT  0.084 145.776 0.137 145.8 ;
     RECT  0.06 145.8 0.137 146.352 ;
     RECT  0.084 146.352 0.137 146.376 ;
     RECT  0.06 146.376 0.137 146.88 ;
     RECT  0.084 146.88 0.137 146.904 ;
     RECT  0.06 146.904 0.137 147.456 ;
     RECT  0.084 147.456 0.137 147.48 ;
     RECT  0.06 147.48 0.137 148.032 ;
     RECT  0.084 148.032 0.137 148.056 ;
     RECT  0.06 148.056 0.137 148.608 ;
     RECT  0.084 148.608 0.137 148.632 ;
     RECT  0.06 148.632 0.137 149.184 ;
     RECT  0.084 149.184 0.137 149.208 ;
     RECT  0.06 149.208 0.137 149.76 ;
     RECT  0.084 149.76 0.137 149.784 ;
     RECT  0.06 149.784 0.137 150.336 ;
     RECT  0.084 150.336 0.137 150.36 ;
     RECT  0.06 150.36 0.137 150.864 ;
     RECT  0.084 150.864 0.137 150.888 ;
     RECT  0.06 150.888 0.137 151.44 ;
     RECT  0.084 151.44 0.137 151.464 ;
     RECT  0.06 151.464 0.137 152.016 ;
     RECT  0.084 152.016 0.137 152.04 ;
     RECT  0.06 152.04 0.137 152.592 ;
     RECT  0.084 152.592 0.137 152.616 ;
     RECT  0.06 152.616 0.137 153.168 ;
     RECT  0.084 153.168 0.137 153.192 ;
     RECT  0.06 153.192 0.137 153.744 ;
     RECT  0.084 153.744 0.137 153.768 ;
     RECT  0.06 153.768 0.137 154.32 ;
     RECT  0.084 154.32 0.137 154.344 ;
     RECT  0.06 154.344 0.137 154.848 ;
     RECT  0.084 154.848 0.137 154.872 ;
     RECT  0.06 154.872 0.137 155.424 ;
     RECT  0.084 155.424 0.137 155.448 ;
     RECT  0.06 155.448 0.137 156 ;
     RECT  0.084 156 0.137 156.024 ;
     RECT  0.06 156.024 0.137 156.576 ;
     RECT  0.084 156.576 0.137 156.6 ;
     RECT  0.06 156.6 0.137 157.152 ;
     RECT  0.084 157.152 0.137 157.176 ;
     RECT  0.06 157.176 0.137 157.728 ;
     RECT  0.084 157.728 0.137 157.752 ;
     RECT  0.06 157.752 0.137 158.304 ;
     RECT  0.084 158.304 0.137 158.328 ;
     RECT  0.06 158.328 0.137 158.88 ;
     RECT  0.084 158.88 0.137 158.904 ;
     RECT  0.06 158.904 0.137 159.408 ;
     RECT  0.084 159.408 0.137 159.432 ;
     RECT  0.06 159.432 0.137 159.984 ;
     RECT  0.084 159.984 0.137 160.008 ;
     RECT  0.06 160.008 0.137 160.56 ;
     RECT  0.084 160.56 0.137 160.584 ;
     RECT  0.06 160.584 0.137 161.136 ;
     RECT  0.084 161.136 0.137 161.16 ;
     RECT  0.06 161.16 0.137 161.712 ;
     RECT  0.084 161.712 0.137 161.736 ;
     RECT  0.084 169.056 0.137 169.08 ;
     RECT  0.06 169.08 0.137 169.248 ;
     RECT  0.084 169.248 0.137 169.272 ;
     RECT  0.06 169.272 0.137 169.392 ;
     RECT  0.084 169.392 0.137 169.416 ;
     RECT  0.06 169.416 0.137 169.584 ;
     RECT  0.084 169.584 0.137 169.608 ;
     RECT  0.06 169.608 0.137 169.728 ;
     RECT  0.084 169.728 0.137 169.752 ;
     RECT  0.06 169.752 0.137 169.92 ;
     RECT  0.084 169.92 0.137 169.944 ;
     RECT  0.137 91.104 0.173 92.856 ;
     RECT  0.137 113.856 0.173 113.88 ;
     RECT  0.137 121.872 0.173 122.424 ;
     RECT  0.137 127.536 0.173 128.712 ;
     RECT  0.137 132.096 0.173 134.376 ;
     RECT  0.137 138.912 0.173 139.512 ;
     RECT  0.137 142.896 0.173 144.648 ;
     RECT  0.137 145.776 0.173 145.8 ;
     RECT  0.137 152.592 0.173 155.448 ;
     RECT  0.133 166.08 0.179 167.064 ;
     RECT  0.179 166.416 0.181 167.064 ;
     RECT  0.181 166.416 0.229 167.16 ;
     RECT  0.229 166.416 0.277 167.496 ;
     RECT  0.137 169.056 0.277 169.752 ;
     RECT  0.137 39.504 0.569 39.528 ;
     RECT  0.137 71.76 0.569 73.272 ;
     RECT  0.137 86.544 0.569 86.568 ;
     RECT  0.137 88.272 0.569 88.296 ;
     RECT  0.173 91.68 0.569 92.856 ;
     RECT  0.137 96.816 0.569 96.84 ;
     RECT  0.137 100.8 0.569 102.504 ;
     RECT  0.137 104.208 0.569 104.232 ;
     RECT  0.137 107.04 0.569 108.216 ;
     RECT  0.137 109.344 0.569 109.368 ;
     RECT  0.137 111.6 0.569 112.2 ;
     RECT  0.137 118.416 0.569 118.44 ;
     RECT  0.173 122.4 0.569 122.424 ;
     RECT  0.137 123.552 0.569 123.576 ;
     RECT  0.173 127.536 0.569 128.136 ;
     RECT  0.173 132.096 0.569 133.272 ;
     RECT  0.173 134.352 0.569 134.376 ;
     RECT  0.137 136.656 0.569 136.68 ;
     RECT  0.137 137.808 0.569 137.832 ;
     RECT  0.173 138.912 0.569 138.936 ;
     RECT  0.173 142.896 0.569 144.072 ;
     RECT  0.137 146.88 0.569 146.904 ;
     RECT  0.137 148.032 0.569 148.632 ;
     RECT  0.173 152.592 0.569 154.872 ;
     RECT  0.137 157.728 0.569 160.008 ;
     RECT  0.137 161.136 0.569 161.736 ;
     RECT  0.569 143.472 2.365 143.496 ;
     RECT  0.137 10.224 2.408 11.256 ;
     RECT  0.137 14.208 2.408 15.192 ;
     RECT  0.137 17.664 2.408 18.168 ;
     RECT  0.137 22.128 2.408 22.152 ;
     RECT  0.137 23.136 2.408 23.16 ;
     RECT  0.137 25.632 2.408 26.136 ;
     RECT  0.137 29.568 2.408 29.592 ;
     RECT  0.137 31.056 2.408 31.08 ;
     RECT  0.137 33.072 2.408 34.056 ;
     RECT  0.137 35.52 2.408 35.544 ;
     RECT  0.137 37.008 2.408 37.032 ;
     RECT  0.137 40.992 2.408 42.024 ;
     RECT  0.137 44.976 2.408 45.96 ;
     RECT  0.137 46.944 2.408 46.968 ;
     RECT  0.137 47.952 2.408 47.976 ;
     RECT  0.137 48.96 2.408 48.984 ;
     RECT  0.137 52.416 2.408 52.44 ;
     RECT  0.137 56.4 2.408 56.904 ;
     RECT  0.137 60.336 2.408 60.36 ;
     RECT  0.137 61.344 2.408 61.368 ;
     RECT  0.137 63.312 2.408 63.336 ;
     RECT  0.137 67.776 2.408 67.8 ;
     RECT  0.569 71.76 2.408 72.792 ;
     RECT  0.137 75.744 2.408 75.768 ;
     RECT  0.137 89.952 2.408 89.976 ;
     RECT  0.569 91.68 2.408 92.28 ;
     RECT  0.569 100.8 2.408 101.4 ;
     RECT  0.569 108.192 2.408 108.216 ;
     RECT  0.137 116.736 2.408 116.76 ;
     RECT  0.569 128.112 2.408 128.136 ;
     RECT  0.569 132.096 2.408 132.12 ;
     RECT  0.569 133.248 2.408 133.272 ;
     RECT  2.365 142.752 2.408 143.496 ;
     RECT  0.569 148.608 2.408 148.632 ;
     RECT  0.569 152.592 2.408 152.616 ;
     RECT  0.133 164.592 2.408 164.616 ;
     RECT  0.277 166.416 2.408 169.752 ;
     RECT  2.408 2.148 2.512 170.652 ;
     RECT  2.512 2.418 2.704 170.382 ;
     RECT  2.704 48.96 2.765 48.984 ;
     RECT  2.704 167.04 2.765 167.592 ;
     RECT  2.704 165.408 2.819 165.96 ;
     RECT  2.765 167.568 2.819 167.592 ;
     RECT  2.704 169.392 2.839 169.464 ;
     RECT  2.704 108.192 3.449 108.216 ;
     RECT  2.839 169.44 3.449 169.464 ;
     RECT  2.704 3.744 3.491 3.768 ;
     RECT  2.704 131.232 3.491 131.256 ;
     RECT  2.704 133.68 3.593 133.992 ;
     RECT  2.704 10.32 3.635 10.344 ;
     RECT  2.704 142.752 3.683 142.776 ;
     RECT  2.704 147.408 3.683 147.72 ;
     RECT  2.819 165.84 3.737 165.96 ;
     RECT  2.704 145.056 3.773 145.608 ;
     RECT  2.704 57.6 3.877 57.624 ;
     RECT  2.704 65.568 3.949 65.592 ;
     RECT  3.769 51.888 4.021 51.912 ;
     RECT  2.704 54.048 4.021 54.072 ;
     RECT  3.877 57.6 4.021 57.816 ;
     RECT  2.704 8.4 4.025 8.424 ;
     RECT  4.021 54.048 4.067 54.648 ;
     RECT  3.98 56.208 4.067 56.232 ;
     RECT  2.704 136.176 4.117 136.2 ;
     RECT  4.076 138.72 4.163 138.744 ;
     RECT  3.593 133.968 4.165 133.992 ;
     RECT  4.165 133.968 4.205 134.52 ;
     RECT  3.949 61.008 4.213 61.032 ;
     RECT  2.704 63.84 4.213 63.864 ;
     RECT  3.949 64.992 4.213 65.592 ;
     RECT  2.704 67.824 4.237 67.848 ;
     RECT  3.733 69.552 4.237 69.576 ;
     RECT  2.704 156.144 4.237 156.168 ;
     RECT  4.205 134.496 4.259 134.52 ;
     RECT  4.117 136.176 4.259 137.016 ;
     RECT  3.737 165.84 4.259 165.864 ;
     RECT  4.021 57.6 4.269 58.392 ;
     RECT  4.201 42.72 4.307 42.744 ;
     RECT  4.213 63.744 4.313 65.592 ;
     RECT  4.261 120.192 4.345 120.216 ;
     RECT  4.261 122.064 4.345 122.088 ;
     RECT  4.237 48.24 4.355 48.264 ;
     RECT  4.268 50.448 4.355 50.472 ;
     RECT  4.201 88.32 4.357 88.344 ;
     RECT  4.213 60.24 4.385 61.896 ;
     RECT  4.313 63.744 4.385 63.864 ;
     RECT  4.345 120.192 4.385 120.312 ;
     RECT  4.345 122.064 4.385 122.568 ;
     RECT  4.117 140.208 4.385 140.232 ;
     RECT  4.357 88.32 4.403 88.872 ;
     RECT  4.405 110.784 4.412 110.808 ;
     RECT  4.213 161.136 4.421 161.832 ;
     RECT  3.985 108.816 4.451 108.84 ;
     RECT  4.412 28.128 4.453 28.152 ;
     RECT  4.237 155.04 4.453 156.168 ;
     RECT  4.453 30.576 4.489 30.6 ;
     RECT  3.985 124.848 4.489 124.872 ;
     RECT  4.309 46.896 4.493 46.92 ;
     RECT  4.412 110.784 4.493 110.904 ;
     RECT  4.412 26.496 4.499 26.52 ;
     RECT  4.453 28.128 4.499 29.064 ;
     RECT  4.493 110.88 4.499 110.904 ;
     RECT  4.345 153.024 4.499 153.048 ;
     RECT  4.481 92.928 4.501 92.952 ;
     RECT  4.345 151.632 4.501 151.656 ;
     RECT  2.704 20.976 4.508 21 ;
     RECT  4.501 92.016 4.525 92.952 ;
     RECT  4.499 29.04 4.537 29.064 ;
     RECT  2.704 90.912 4.547 90.936 ;
     RECT  4.501 150.864 4.547 151.656 ;
     RECT  4.508 20.736 4.549 21 ;
     RECT  4.453 32.448 4.549 32.472 ;
     RECT  4.237 38.4 4.549 38.424 ;
     RECT  4.453 39.984 4.549 40.008 ;
     RECT  4.201 41.616 4.549 41.64 ;
     RECT  4.417 97.968 4.549 97.992 ;
     RECT  4.508 149.568 4.549 149.592 ;
     RECT  4.547 150.864 4.549 150.888 ;
     RECT  4.508 34.32 4.561 34.344 ;
     RECT  4.313 64.992 4.561 65.592 ;
     RECT  4.549 94.992 4.561 95.016 ;
     RECT  4.453 154.416 4.561 156.168 ;
     RECT  4.525 92.016 4.565 93.48 ;
     RECT  4.561 34.32 4.595 34.584 ;
     RECT  4.549 38.4 4.595 41.64 ;
     RECT  4.549 149.568 4.595 150.888 ;
     RECT  3.697 113.328 4.597 113.352 ;
     RECT  4.517 37.008 4.601 37.032 ;
     RECT  4.261 44.448 4.601 44.472 ;
     RECT  3.773 145.056 4.601 145.08 ;
     RECT  4.549 19.152 4.633 19.176 ;
     RECT  2.704 73.392 4.633 73.416 ;
     RECT  4.525 74.64 4.633 74.664 ;
     RECT  4.561 94.704 4.636 95.016 ;
     RECT  4.549 97.392 4.636 98.76 ;
     RECT  4.565 93.456 4.643 93.48 ;
     RECT  4.597 113.328 4.643 113.88 ;
     RECT  4.22 118.176 4.643 118.2 ;
     RECT  4.636 94.704 4.645 94.728 ;
     RECT  4.633 18.816 4.673 19.176 ;
     RECT  4.385 60.24 4.673 61.032 ;
     RECT  4.589 115.152 4.673 115.176 ;
     RECT  4.597 116.592 4.684 116.616 ;
     RECT  4.237 67.824 4.741 68.088 ;
     RECT  4.237 69.552 4.741 70.008 ;
     RECT  2.704 129.792 4.745 129.816 ;
     RECT  3.683 147.696 4.781 147.72 ;
     RECT  4.561 64.992 4.787 66.504 ;
     RECT  4.595 40.8 4.817 41.64 ;
     RECT  4.269 57.6 4.817 57.624 ;
     RECT  4.643 113.856 4.817 113.88 ;
     RECT  2.704 132.624 4.817 132.648 ;
     RECT  4.021 16.128 4.849 16.152 ;
     RECT  4.549 96.096 4.885 96.12 ;
     RECT  4.885 96.096 4.889 96.216 ;
     RECT  4.549 32.448 4.925 33.048 ;
     RECT  4.595 39.312 4.925 39.336 ;
     RECT  4.259 136.992 4.925 137.016 ;
     RECT  2.704 141.312 4.925 141.336 ;
     RECT  2.704 72.144 4.94 72.168 ;
     RECT  4.633 73.392 4.94 74.664 ;
     RECT  4.741 67.824 5.027 70.536 ;
     RECT  4.94 72.144 5.027 74.664 ;
     RECT  4.489 30.576 5.029 30.744 ;
     RECT  4.385 120.288 5.033 120.312 ;
     RECT  4.849 16.128 5.077 17.112 ;
     RECT  5.077 16.128 5.123 17.64 ;
     RECT  4.673 18.816 5.123 18.84 ;
     RECT  4.549 20.448 5.125 21.576 ;
     RECT  4.633 22.656 5.125 22.68 ;
     RECT  4.381 24.48 5.125 24.504 ;
     RECT  4.957 25.584 5.125 26.136 ;
     RECT  5.029 30.576 5.125 30.84 ;
     RECT  5.125 20.448 5.132 22.68 ;
     RECT  4.561 154.416 5.132 156.456 ;
     RECT  4.993 157.872 5.132 157.896 ;
     RECT  4.067 54.624 5.141 54.648 ;
     RECT  5.125 30.192 5.171 30.84 ;
     RECT  4.489 124.848 5.171 125.112 ;
     RECT  4.633 127.344 5.177 127.368 ;
     RECT  5.125 23.712 5.212 26.136 ;
     RECT  5.132 20.208 5.219 22.68 ;
     RECT  5.132 154.416 5.219 157.896 ;
     RECT  4.237 14.784 5.249 14.808 ;
     RECT  4.385 63.84 5.249 63.864 ;
     RECT  4.787 64.992 5.249 65.64 ;
     RECT  5.027 67.824 5.249 69.576 ;
     RECT  5.027 74.64 5.269 74.664 ;
     RECT  4.237 102 5.269 102.024 ;
     RECT  5.219 20.736 5.285 22.68 ;
     RECT  4.021 51.888 5.317 52.2 ;
     RECT  4.595 150.144 5.321 150.888 ;
     RECT  5.269 102 5.356 102.84 ;
     RECT  4.817 40.992 5.357 41.64 ;
     RECT  5.249 69.552 5.357 69.576 ;
     RECT  4.957 50.688 5.363 50.712 ;
     RECT  5.356 102 5.363 102.648 ;
     RECT  5.363 102.624 5.365 102.648 ;
     RECT  5.317 51.888 5.401 52.488 ;
     RECT  5.212 23.712 5.459 24.504 ;
     RECT  5.027 73.344 5.465 73.416 ;
     RECT  4.385 122.544 5.465 122.568 ;
     RECT  5.125 123.648 5.465 123.672 ;
     RECT  5.212 25.632 5.497 26.136 ;
     RECT  5.413 107.952 5.5 107.976 ;
     RECT  5.285 20.736 5.501 20.76 ;
     RECT  5.459 23.712 5.573 23.736 ;
     RECT  4.636 97.776 5.573 98.76 ;
     RECT  5.321 150.864 5.573 150.888 ;
     RECT  2.704 158.976 5.605 159 ;
     RECT  5.285 21.936 5.609 22.68 ;
     RECT  4.673 61.008 5.641 61.032 ;
     RECT  5.413 109.104 5.641 109.128 ;
     RECT  4.093 86.592 5.645 86.616 ;
     RECT  4.403 88.848 5.645 88.872 ;
     RECT  5.219 157.872 5.651 157.896 ;
     RECT  5.605 158.976 5.651 159.24 ;
     RECT  4.421 161.808 5.673 161.832 ;
     RECT  5.641 60.96 5.677 61.032 ;
     RECT  3.913 100.8 5.681 100.824 ;
     RECT  5.641 109.104 5.681 109.416 ;
     RECT  5.101 44.784 5.699 44.808 ;
     RECT  5.317 48.384 5.699 48.408 ;
     RECT  4.777 9.072 5.701 9.096 ;
     RECT  5.605 84.24 5.701 84.264 ;
     RECT  5.533 138.816 5.713 138.84 ;
     RECT  4.129 76.32 5.747 76.344 ;
     RECT  5.701 84.24 5.747 84.792 ;
     RECT  5.357 41.616 5.789 41.64 ;
     RECT  5.249 65.52 5.789 65.64 ;
     RECT  5.651 159.216 5.789 159.24 ;
     RECT  5.708 120.96 5.795 120.984 ;
     RECT  5.465 73.344 5.861 73.368 ;
     RECT  5.269 74.64 5.861 75.288 ;
     RECT  5.747 84.768 5.861 84.792 ;
     RECT  4.565 92.016 5.861 92.04 ;
     RECT  5.123 16.128 5.891 16.152 ;
     RECT  5.701 9.072 5.897 9.672 ;
     RECT  4.345 12.528 5.897 12.552 ;
     RECT  5.101 104.304 5.897 104.328 ;
     RECT  5.219 154.416 5.897 155.112 ;
     RECT  5.171 30.192 5.9 30.216 ;
     RECT  5.845 13.584 5.932 13.608 ;
     RECT  4.957 11.328 5.933 11.352 ;
     RECT  5.605 131.808 5.941 131.832 ;
     RECT  5.9 134.832 5.941 134.856 ;
     RECT  5.9 29.424 5.969 30.216 ;
     RECT  5.969 29.424 5.987 29.448 ;
     RECT  5.821 47.28 5.987 47.304 ;
     RECT  5.281 136.656 5.987 136.68 ;
     RECT  5.713 138.816 5.987 138.888 ;
     RECT  5.785 111.264 6.001 111.288 ;
     RECT  5.609 21.936 6.005 22.488 ;
     RECT  5.497 25.632 6.028 26.712 ;
     RECT  6.029 55.296 6.044 55.32 ;
     RECT  5.641 36.432 6.073 36.456 ;
     RECT  5.941 51.552 6.083 51.576 ;
     RECT  5.605 53.424 6.083 53.448 ;
     RECT  5.641 56.976 6.085 57 ;
     RECT  5.941 130.464 6.131 131.832 ;
     RECT  6.085 59.28 6.14 59.304 ;
     RECT  6.028 25.632 6.179 25.656 ;
     RECT  6.085 56.976 6.185 57.48 ;
     RECT  6.14 59.28 6.227 59.64 ;
     RECT  6.145 15.648 6.275 15.672 ;
     RECT  6.131 130.992 6.275 131.832 ;
     RECT  5.941 134.832 6.275 135.144 ;
     RECT  6.044 55.296 6.325 55.56 ;
     RECT  5.677 60.864 6.325 61.032 ;
     RECT  6.284 159.888 6.325 159.912 ;
     RECT  5.681 109.392 6.329 109.416 ;
     RECT  6.085 129.36 6.329 129.384 ;
     RECT  5.789 65.52 6.361 65.544 ;
     RECT  6.325 159.888 6.371 160.584 ;
     RECT  4.889 96.192 6.397 96.216 ;
     RECT  6.289 149.232 6.467 149.256 ;
     RECT  6.133 94.704 6.469 94.728 ;
     RECT  5.861 74.928 6.517 75.288 ;
     RECT  6.001 110.496 6.517 111.288 ;
     RECT  6.073 114.624 6.517 114.648 ;
     RECT  6.361 65.088 6.563 65.544 ;
     RECT  6.517 110.496 6.563 112.104 ;
     RECT  6.325 60.864 6.613 61.32 ;
     RECT  4.777 62.736 6.613 62.76 ;
     RECT  5.573 97.776 6.613 98.376 ;
     RECT  5.857 144.624 6.62 144.648 ;
     RECT  6.613 71.616 6.649 71.64 ;
     RECT  6.517 114.528 6.653 114.648 ;
     RECT  6.572 101.28 6.659 101.304 ;
     RECT  6.572 117.216 6.659 117.24 ;
     RECT  5.605 118.272 6.659 118.296 ;
     RECT  6.563 112.08 6.661 112.104 ;
     RECT  6.181 27.072 6.677 27.096 ;
     RECT  6.613 105.168 6.685 105.192 ;
     RECT  4.633 106.848 6.685 106.872 ;
     RECT  6.677 27.072 6.716 27.384 ;
     RECT  6.505 28.752 6.716 28.776 ;
     RECT  6.361 32.928 6.716 32.952 ;
     RECT  4.595 34.56 6.716 34.584 ;
     RECT  6.613 60.864 6.716 62.76 ;
     RECT  5.641 63.744 6.716 63.768 ;
     RECT  6.653 114.624 6.717 114.648 ;
     RECT  6.716 27.072 6.755 28.776 ;
     RECT  6.716 18.816 6.757 18.84 ;
     RECT  6.716 32.928 6.757 34.584 ;
     RECT  6.073 36.096 6.757 36.456 ;
     RECT  6.613 102.912 6.757 102.936 ;
     RECT  6.563 110.496 6.757 110.712 ;
     RECT  6.661 112.08 6.761 112.968 ;
     RECT  6.721 146.448 6.764 146.472 ;
     RECT  6.757 18.816 6.803 19.368 ;
     RECT  6.755 27.216 6.803 28.776 ;
     RECT  6.757 32.928 6.803 36.456 ;
     RECT  6.716 60.864 6.803 63.768 ;
     RECT  6.757 102.912 6.829 104.04 ;
     RECT  6.649 70.56 6.833 71.64 ;
     RECT  6.803 34.176 6.853 36.456 ;
     RECT  5.941 49.344 6.853 49.368 ;
     RECT  5.219 156.432 6.853 156.456 ;
     RECT  6.853 49.008 6.86 49.368 ;
     RECT  6.325 55.296 6.901 55.848 ;
     RECT  5.897 155.04 6.901 155.064 ;
     RECT  6.853 156.144 6.901 156.456 ;
     RECT  6.685 105.168 6.973 106.872 ;
     RECT  5.171 125.088 7.004 125.112 ;
     RECT  6.289 141.888 7.009 141.912 ;
     RECT  6.793 119.04 7.045 119.064 ;
     RECT  6.901 155.04 7.045 156.456 ;
     RECT  5.987 138.816 7.093 138.84 ;
     RECT  6.853 34.176 7.141 37.08 ;
     RECT  6.893 66.72 7.153 66.744 ;
     RECT  5.641 67.728 7.153 67.752 ;
     RECT  6.397 95.952 7.285 96.216 ;
     RECT  7.045 154.512 7.285 156.456 ;
     RECT  7.153 66.72 7.369 67.752 ;
     RECT  6.973 105.168 7.405 107.784 ;
     RECT  6.371 160.56 7.513 160.584 ;
     RECT  7.525 87.936 7.585 87.96 ;
     RECT  6.829 102.624 7.585 104.04 ;
     RECT  7.405 105.12 7.585 107.784 ;
     RECT  7.585 102.624 7.613 107.784 ;
     RECT  7.237 108.864 7.613 108.888 ;
     RECT  6.937 89.472 7.621 89.496 ;
     RECT  7.549 101.424 7.621 101.448 ;
     RECT  7.613 102.624 7.621 108.888 ;
     RECT  6.325 158.16 7.693 158.184 ;
     RECT  6.793 14.208 7.765 14.232 ;
     RECT  6.289 10.224 7.808 10.248 ;
     RECT  6.945 11.856 7.808 11.88 ;
     RECT  7.765 14.208 7.808 14.424 ;
     RECT  5.123 17.616 7.808 17.64 ;
     RECT  6.803 19.344 7.808 19.368 ;
     RECT  6.005 22.464 7.808 22.488 ;
     RECT  6.469 23.904 7.808 23.928 ;
     RECT  6.803 27.216 7.808 27.24 ;
     RECT  6.803 28.752 7.808 28.776 ;
     RECT  6.757 31.872 7.808 31.896 ;
     RECT  7.141 34.176 7.808 37.608 ;
     RECT  7.081 39.888 7.808 39.912 ;
     RECT  6.853 43.296 7.808 43.848 ;
     RECT  6.469 45.264 7.808 45.288 ;
     RECT  6.505 47.856 7.808 47.88 ;
     RECT  6.86 49.008 7.808 49.56 ;
     RECT  6.901 53.52 7.808 53.544 ;
     RECT  6.901 55.248 7.808 55.848 ;
     RECT  7.153 58.704 7.808 58.728 ;
     RECT  6.803 60.864 7.808 60.888 ;
     RECT  6.803 62.16 7.808 63.768 ;
     RECT  6.563 65.088 7.808 65.112 ;
     RECT  7.369 66.096 7.808 67.752 ;
     RECT  6.937 69.792 7.808 69.816 ;
     RECT  6.833 70.944 7.808 71.64 ;
     RECT  7.093 73.392 7.808 73.416 ;
     RECT  6.517 74.928 7.808 75.672 ;
     RECT  7.141 80.832 7.808 80.856 ;
     RECT  6.229 83.472 7.808 83.496 ;
     RECT  7.585 87.936 7.808 88.056 ;
     RECT  7.621 89.472 7.808 90.072 ;
     RECT  6.469 93.744 7.808 94.728 ;
     RECT  7.285 95.952 7.808 96.6 ;
     RECT  6.613 97.776 7.808 98.952 ;
     RECT  7.436 99.936 7.808 99.96 ;
     RECT  7.621 101.04 7.808 108.888 ;
     RECT  6.757 110.256 7.808 110.712 ;
     RECT  6.761 112.944 7.808 112.968 ;
     RECT  7.045 119.04 7.808 119.16 ;
     RECT  7.004 124.224 7.808 125.112 ;
     RECT  6.829 126.384 7.808 126.408 ;
     RECT  6.275 130.992 7.808 131.016 ;
     RECT  6.229 133.2 7.808 133.224 ;
     RECT  6.275 135.12 7.808 135.144 ;
     RECT  7.093 138.336 7.808 138.84 ;
     RECT  7.093 139.92 7.808 139.944 ;
     RECT  7.009 141.888 7.808 142.44 ;
     RECT  6.62 144.432 7.808 144.648 ;
     RECT  6.764 146.448 7.808 147.096 ;
     RECT  6.421 151.392 7.808 151.416 ;
     RECT  7.285 153.552 7.808 156.456 ;
     RECT  7.693 157.488 7.808 158.184 ;
     RECT  7.513 159.648 7.808 160.584 ;
     RECT  7.808 2.148 7.912 170.652 ;
     RECT  7.912 2.418 8.104 170.382 ;
     RECT  8.104 89.472 8.243 92.328 ;
     RECT  8.104 93.504 8.243 94.392 ;
     RECT  8.104 112.896 8.243 112.968 ;
     RECT  8.104 102.624 8.273 110.28 ;
     RECT  8.104 119.136 8.309 119.16 ;
     RECT  8.104 138.336 8.309 138.36 ;
     RECT  8.104 133.2 8.381 133.224 ;
     RECT  8.104 121.296 8.531 121.32 ;
     RECT  8.104 62.544 8.561 63.24 ;
     RECT  8.243 93.504 8.771 94.104 ;
     RECT  8.104 17.616 8.819 17.64 ;
     RECT  8.104 95.76 8.819 101.64 ;
     RECT  8.104 39.888 8.867 39.912 ;
     RECT  8.104 64.416 8.915 64.44 ;
     RECT  8.104 156.432 8.963 156.456 ;
     RECT  8.561 62.64 9.029 63.24 ;
     RECT  8.819 95.76 9.065 97.464 ;
     RECT  8.104 74.928 9.145 77.016 ;
     RECT  8.819 98.544 9.157 101.64 ;
     RECT  8.273 102.624 9.157 109.704 ;
     RECT  8.243 90.048 9.217 92.328 ;
     RECT  9.205 60.816 9.241 60.84 ;
     RECT  8.771 93.744 9.241 94.104 ;
     RECT  9.065 95.76 9.241 96.936 ;
     RECT  9.157 98.544 9.241 109.704 ;
     RECT  8.243 112.944 9.277 112.968 ;
     RECT  9.241 93.744 9.325 96.936 ;
     RECT  9.325 93.744 9.347 94.632 ;
     RECT  9.241 98.544 9.349 109.944 ;
     RECT  9.277 112.944 9.389 113.016 ;
     RECT  9.241 86.64 9.395 86.664 ;
     RECT  8.104 154.512 9.395 154.536 ;
     RECT  8.104 28.752 9.443 28.776 ;
     RECT  8.104 14.4 9.491 14.424 ;
     RECT  8.104 157.488 9.491 157.512 ;
     RECT  9.145 74.928 9.493 76.392 ;
     RECT  8.104 11.952 9.539 11.976 ;
     RECT  9.529 86.016 9.613 86.04 ;
     RECT  9.029 62.64 9.635 62.664 ;
     RECT  9.493 74.688 9.641 76.392 ;
     RECT  9.347 93.744 9.733 94.056 ;
     RECT  9.733 92.352 9.779 94.056 ;
     RECT  9.217 90.048 9.785 91.224 ;
     RECT  9.709 85.008 9.853 85.032 ;
     RECT  9.773 78.048 9.857 78.072 ;
     RECT  9.779 92.352 9.875 92.952 ;
     RECT  9.325 95.76 9.875 96.936 ;
     RECT  9.133 111.936 9.889 111.96 ;
     RECT  9.853 85.008 9.893 85.8 ;
     RECT  8.104 87.792 9.925 87.96 ;
     RECT  9.349 98.544 9.929 109.992 ;
     RECT  9.893 85.632 9.937 85.8 ;
     RECT  9.685 64.368 9.953 64.392 ;
     RECT  9.929 98.544 9.971 109.944 ;
     RECT  9.953 64.224 10.021 64.392 ;
     RECT  9.389 112.992 10.037 113.016 ;
     RECT  9.74 121.248 10.067 121.272 ;
     RECT  8.104 125.088 10.067 125.112 ;
     RECT  9.925 87.792 10.109 88.152 ;
     RECT  9.641 74.688 10.145 75.672 ;
     RECT  8.104 159.648 10.163 159.672 ;
     RECT  10.109 87.792 10.189 88.056 ;
     RECT  9.971 98.544 10.204 103.08 ;
     RECT  10.021 63.792 10.253 64.392 ;
     RECT  9.889 111.024 10.253 111.96 ;
     RECT  9.997 89.52 10.259 89.544 ;
     RECT  10.253 111.024 10.289 111.624 ;
     RECT  10.289 111.6 10.325 111.624 ;
     RECT  9.875 96.192 10.405 96.936 ;
     RECT  10.189 87.792 10.451 87.96 ;
     RECT  10.204 98.544 10.501 98.616 ;
     RECT  10.204 99.84 10.505 103.08 ;
     RECT  8.104 22.464 10.547 22.488 ;
     RECT  10.405 96.192 10.643 96.456 ;
     RECT  10.145 75.12 10.748 75.672 ;
     RECT  9.779 94.032 10.789 94.056 ;
     RECT  9.785 90.96 10.829 90.984 ;
     RECT  9.971 104.304 10.829 109.944 ;
     RECT  10.748 75.12 10.835 76.392 ;
     RECT  10.789 94.032 10.873 94.104 ;
     RECT  10.501 92.112 10.885 92.136 ;
     RECT  10.861 95.184 10.945 95.208 ;
     RECT  10.501 97.776 11.009 98.616 ;
     RECT  10.451 87.792 11.081 87.816 ;
     RECT  11.009 98.592 11.081 98.616 ;
     RECT  10.829 104.304 11.081 108.888 ;
     RECT  9.997 46.752 11.123 46.776 ;
     RECT  9.241 60.816 11.221 61.176 ;
     RECT  10.253 64.368 11.221 64.392 ;
     RECT  11.113 66.672 11.297 66.696 ;
     RECT  11.113 59.76 11.365 59.784 ;
     RECT  11.221 60.816 11.365 61.416 ;
     RECT  10.829 109.92 11.441 109.944 ;
     RECT  11.473 71.76 11.612 71.784 ;
     RECT  9.157 73.488 11.612 73.512 ;
     RECT  9.937 85.776 11.621 85.8 ;
     RECT  11.612 71.76 11.699 73.512 ;
     RECT  11.401 58.176 11.761 58.2 ;
     RECT  11.365 59.232 11.761 61.416 ;
     RECT  11.081 104.592 11.801 108.888 ;
     RECT  10.835 75.12 11.869 76.056 ;
     RECT  10.505 100.56 11.977 103.08 ;
     RECT  11.869 75.12 12.017 76.968 ;
     RECT  11.761 58.176 12.121 61.416 ;
     RECT  11.801 104.592 12.157 108.792 ;
     RECT  11.977 100.08 12.193 103.08 ;
     RECT  12.157 104.448 12.193 108.792 ;
     RECT  12.121 57.696 12.301 61.416 ;
     RECT  12.301 57.6 12.373 61.416 ;
     RECT  8.104 83.616 12.409 83.64 ;
     RECT  12.193 100.08 12.409 108.792 ;
     RECT  12.373 57.312 12.481 61.416 ;
     RECT  10.873 94.032 12.509 94.056 ;
     RECT  12.017 76.944 12.565 76.968 ;
     RECT  12.193 70.368 12.769 70.392 ;
     RECT  12.517 66.288 12.841 66.312 ;
     RECT  10.885 91.584 12.913 92.136 ;
     RECT  12.509 93.456 12.913 94.056 ;
     RECT  12.661 119.472 12.913 119.496 ;
     RECT  12.481 57.312 12.949 61.992 ;
     RECT  12.877 111.12 12.949 111.144 ;
     RECT  12.841 66.288 12.997 66.648 ;
     RECT  12.949 56.88 13.052 61.992 ;
     RECT  11.221 64.368 13.057 65.016 ;
     RECT  12.997 66.288 13.057 66.696 ;
     RECT  12.409 99.408 13.057 108.792 ;
     RECT  9.877 40.608 13.208 40.632 ;
     RECT  13.052 56.88 13.208 62.76 ;
     RECT  13.057 64.368 13.208 66.696 ;
     RECT  12.997 67.92 13.208 67.944 ;
     RECT  12.769 69.696 13.208 70.392 ;
     RECT  11.699 73.344 13.208 73.512 ;
     RECT  12.017 75.648 13.208 75.672 ;
     RECT  12.565 76.944 13.208 77.832 ;
     RECT  12.527 79.728 13.208 79.752 ;
     RECT  8.104 80.832 13.208 81.624 ;
     RECT  12.409 83.616 13.208 83.784 ;
     RECT  12.949 84.864 13.208 84.888 ;
     RECT  12.301 88.704 13.208 88.728 ;
     RECT  12.913 91.584 13.208 94.056 ;
     RECT  10.643 96.192 13.208 96.216 ;
     RECT  13.057 99.408 13.208 109.272 ;
     RECT  12.949 110.304 13.208 111.144 ;
     RECT  12.913 119.472 13.208 119.976 ;
     RECT  13.208 2.148 13.312 170.652 ;
     RECT  13.312 2.418 13.504 170.382 ;
     RECT  13.504 84.864 13.565 84.888 ;
     RECT  13.504 98.688 13.709 112.056 ;
     RECT  13.709 110.592 13.789 111.768 ;
     RECT  13.504 91.584 13.853 92.376 ;
     RECT  13.789 110.592 13.961 110.952 ;
     RECT  13.504 72.384 14.003 75.24 ;
     RECT  13.504 80.832 14.099 81.24 ;
     RECT  13.961 110.688 14.321 110.952 ;
     RECT  14.003 73.488 14.393 75.24 ;
     RECT  13.504 88.608 14.485 88.632 ;
     RECT  13.709 98.688 14.492 103.08 ;
     RECT  13.504 77.424 14.497 78.648 ;
     RECT  13.853 92.352 14.531 92.376 ;
     RECT  13.504 97.536 14.579 97.56 ;
     RECT  14.492 98.64 14.681 103.08 ;
     RECT  14.485 88.32 14.713 88.632 ;
     RECT  14.393 73.488 14.723 74.328 ;
     RECT  13.504 94.032 14.749 94.44 ;
     RECT  13.709 104.304 14.749 109.464 ;
     RECT  14.749 94.032 14.821 95.4 ;
     RECT  14.497 77.424 14.825 79.32 ;
     RECT  13.504 56.88 14.857 62.232 ;
     RECT  14.681 98.64 14.917 103.032 ;
     RECT  14.821 90.672 14.929 90.84 ;
     RECT  14.929 90.624 14.933 90.84 ;
     RECT  14.321 110.688 14.957 110.808 ;
     RECT  14.825 78.336 14.969 79.32 ;
     RECT  14.885 84.912 14.969 84.936 ;
     RECT  14.497 86.88 14.972 86.904 ;
     RECT  14.713 87.984 14.972 88.632 ;
     RECT  14.917 97.776 15.004 103.032 ;
     RECT  14.933 90.624 15.005 90.792 ;
     RECT  14.972 86.352 15.029 86.904 ;
     RECT  14.972 87.888 15.029 88.632 ;
     RECT  15.029 86.352 15.059 88.632 ;
     RECT  15.004 97.872 15.059 103.032 ;
     RECT  14.965 82.608 15.068 82.632 ;
     RECT  15.005 90.624 15.073 90.648 ;
     RECT  15.068 82.032 15.107 82.632 ;
     RECT  15.073 89.808 15.113 90.648 ;
     RECT  15.073 92.928 15.203 92.952 ;
     RECT  14.821 94.032 15.203 96.168 ;
     RECT  13.504 64.368 15.257 70.392 ;
     RECT  15.203 94.032 15.329 95.4 ;
     RECT  15.329 94.032 15.347 95.208 ;
     RECT  14.749 104.304 15.361 109.512 ;
     RECT  14.957 110.592 15.361 110.808 ;
     RECT  14.857 56.88 15.401 62.664 ;
     RECT  14.969 78.624 15.437 79.32 ;
     RECT  14.099 80.832 15.437 80.856 ;
     RECT  15.059 98.64 15.545 103.032 ;
     RECT  15.361 104.304 15.577 110.808 ;
     RECT  15.145 111.888 15.577 111.912 ;
     RECT  15.107 82.032 15.589 82.056 ;
     RECT  15.545 98.64 15.653 99.192 ;
     RECT  14.723 73.488 15.683 73.512 ;
     RECT  15.644 74.496 15.731 74.52 ;
     RECT  15.437 78.624 15.949 78.648 ;
     RECT  15.877 85.488 16.049 85.512 ;
     RECT  15.347 94.032 16.076 94.104 ;
     RECT  15.653 98.88 16.085 99.192 ;
     RECT  15.059 86.64 16.117 88.632 ;
     RECT  15.545 100.32 16.117 103.032 ;
     RECT  15.577 104.304 16.117 111.912 ;
     RECT  16.117 100.32 16.157 111.912 ;
     RECT  16.045 92.352 16.163 92.376 ;
     RECT  16.076 93.456 16.163 94.104 ;
     RECT  16.117 86.016 16.201 88.632 ;
     RECT  15.347 95.184 16.201 95.208 ;
     RECT  13.504 119.472 16.261 119.832 ;
     RECT  16.157 100.896 16.441 111.912 ;
     RECT  16.163 94.08 16.501 94.104 ;
     RECT  16.501 94.08 16.517 94.488 ;
     RECT  16.453 92.304 16.54 92.328 ;
     RECT  16.477 95.76 16.561 95.784 ;
     RECT  16.549 115.728 16.597 115.752 ;
     RECT  16.517 94.464 16.625 94.488 ;
     RECT  16.201 86.736 16.643 88.632 ;
     RECT  16.441 100.896 16.769 112.44 ;
     RECT  16.769 100.896 16.787 103.032 ;
     RECT  16.597 115.344 16.789 115.752 ;
     RECT  16.643 86.736 16.835 87.24 ;
     RECT  16.769 104.304 17.053 112.44 ;
     RECT  16.835 86.736 17.093 86.904 ;
     RECT  17.053 104.304 17.093 113.016 ;
     RECT  16.787 100.944 17.129 103.032 ;
     RECT  17.129 100.944 17.165 102.984 ;
     RECT  16.085 98.88 17.233 98.904 ;
     RECT  17.165 102.72 17.237 102.984 ;
     RECT  17.093 86.88 17.363 86.904 ;
     RECT  17.093 104.352 17.377 113.016 ;
     RECT  16.789 114.576 17.377 115.752 ;
     RECT  15.401 56.88 17.413 62.232 ;
     RECT  16.837 63.264 17.413 63.288 ;
     RECT  17.233 98.64 17.489 98.904 ;
     RECT  17.413 56.88 17.917 63.288 ;
     RECT  15.257 64.368 17.953 65.016 ;
     RECT  17.165 100.944 17.953 101.16 ;
     RECT  16.981 117.36 17.953 117.384 ;
     RECT  17.917 56.88 18.025 63.384 ;
     RECT  17.953 64.368 18.025 65.16 ;
     RECT  17.953 117.36 18.025 117.528 ;
     RECT  16.261 118.944 18.025 119.832 ;
     RECT  18.025 56.88 18.061 65.16 ;
     RECT  15.257 66.192 18.061 70.392 ;
     RECT  18.025 117.36 18.061 119.832 ;
     RECT  13.504 40.608 18.421 40.632 ;
     RECT  17.237 102.96 18.421 102.984 ;
     RECT  18.421 40.608 18.608 40.92 ;
     RECT  18.061 56.88 18.608 70.392 ;
     RECT  16.405 74.688 18.608 74.712 ;
     RECT  18.421 82.656 18.608 83.304 ;
     RECT  16.643 88.608 18.608 88.632 ;
     RECT  15.113 89.808 18.608 90.408 ;
     RECT  17.489 98.88 18.608 98.904 ;
     RECT  17.953 100.896 18.608 101.16 ;
     RECT  18.421 102.192 18.608 102.984 ;
     RECT  17.377 104.352 18.608 115.752 ;
     RECT  18.061 117.072 18.608 119.832 ;
     RECT  18.608 2.148 18.712 170.652 ;
     RECT  18.712 2.418 18.904 170.382 ;
     RECT  18.904 83.28 19.037 83.304 ;
     RECT  18.904 74.688 19.073 74.712 ;
     RECT  18.904 89.808 19.475 89.832 ;
     RECT  18.904 72.912 19.907 72.936 ;
     RECT  18.904 52.512 19.969 52.536 ;
     RECT  19.969 52.416 20.041 52.536 ;
     RECT  20.077 45.024 20.149 45.048 ;
     RECT  20.149 44.352 20.185 45.048 ;
     RECT  18.904 56.88 20.243 70.392 ;
     RECT  20.041 49.056 20.257 49.08 ;
     RECT  18.904 50.304 20.257 50.328 ;
     RECT  20.257 48.192 20.293 50.328 ;
     RECT  20.285 102.624 20.369 102.648 ;
     RECT  20.293 47.616 20.509 50.328 ;
     RECT  20.041 51.648 20.509 53.112 ;
     RECT  20.243 56.88 20.833 70.296 ;
     RECT  20.509 47.616 21.013 54.072 ;
     RECT  18.904 106.464 21.013 119.832 ;
     RECT  21.013 47.328 21.049 54.072 ;
     RECT  20.833 56.544 21.049 70.296 ;
     RECT  20.185 44.352 21.085 45.432 ;
     RECT  21.049 46.944 21.085 54.072 ;
     RECT  21.049 55.488 21.085 70.296 ;
     RECT  21.013 106.368 21.085 119.832 ;
     RECT  18.904 88.608 21.395 88.632 ;
     RECT  21.085 44.352 21.661 70.296 ;
     RECT  21.661 44.256 22.165 70.296 ;
     RECT  21.085 106.368 22.165 120.12 ;
     RECT  20.293 123.168 22.165 123.192 ;
     RECT  22.165 44.16 22.464 70.296 ;
     RECT  18.904 98.88 22.464 98.904 ;
     RECT  18.904 101.136 22.464 101.16 ;
     RECT  22.165 106.368 22.464 120.216 ;
     RECT  22.165 123.168 22.529 123.48 ;
     RECT  22.464 44.16 22.536 120.216 ;
     RECT  22.529 123.456 22.889 123.48 ;
     RECT  18.904 40.608 24.008 40.92 ;
     RECT  24.008 2.148 24.112 41.052 ;
     RECT  24.008 123.108 24.112 170.652 ;
     RECT  24.112 2.418 24.304 40.92 ;
     RECT  24.112 123.378 24.304 170.382 ;
     RECT  24.304 40.608 29.408 40.92 ;
     RECT  29.408 2.148 29.512 41.052 ;
     RECT  29.408 123.108 29.512 170.652 ;
     RECT  29.512 2.418 29.704 40.92 ;
     RECT  29.512 123.378 29.704 170.382 ;
     RECT  29.704 40.608 34.808 40.92 ;
     RECT  34.808 2.148 34.912 41.052 ;
     RECT  34.808 123.108 34.912 170.652 ;
     RECT  34.912 2.418 35.104 40.92 ;
     RECT  34.912 123.378 35.104 170.382 ;
     RECT  35.104 40.608 40.208 40.92 ;
     RECT  40.208 2.148 40.312 41.052 ;
     RECT  40.208 123.108 40.312 170.652 ;
     RECT  40.312 2.418 40.504 40.92 ;
     RECT  40.312 123.378 40.504 170.382 ;
     RECT  40.504 40.608 45.608 40.92 ;
     RECT  45.608 2.148 45.712 41.052 ;
     RECT  45.608 123.108 45.712 170.652 ;
     RECT  45.712 2.418 45.904 40.92 ;
     RECT  45.712 123.378 45.904 170.382 ;
     RECT  45.904 40.608 51.008 40.92 ;
     RECT  51.008 2.148 51.112 41.052 ;
     RECT  51.008 123.108 51.112 170.652 ;
     RECT  51.112 2.418 51.304 40.92 ;
     RECT  51.112 123.378 51.304 170.382 ;
     RECT  51.304 40.608 52.265 40.92 ;
     RECT  52.265 40.608 56.408 40.632 ;
     RECT  56.408 2.148 56.512 41.052 ;
     RECT  56.408 123.108 56.512 170.652 ;
     RECT  56.512 2.418 56.704 40.782 ;
     RECT  56.512 123.378 56.704 170.382 ;
     RECT  56.704 40.608 58.705 40.632 ;
     RECT  58.705 40.608 58.745 40.824 ;
     RECT  58.745 40.8 61.693 40.824 ;
     RECT  61.693 40.656 61.808 40.824 ;
     RECT  61.808 2.148 61.912 41.052 ;
     RECT  61.808 123.108 61.912 170.652 ;
     RECT  61.912 2.418 61.949 40.824 ;
     RECT  61.949 2.418 62.104 40.782 ;
     RECT  61.912 123.378 62.104 170.382 ;
     RECT  62.104 40.656 67.208 40.68 ;
     RECT  67.208 2.148 67.312 41.052 ;
     RECT  67.208 123.108 67.312 170.652 ;
     RECT  67.312 2.418 67.504 40.782 ;
     RECT  67.312 123.378 67.504 170.382 ;
     RECT  67.504 40.656 72.608 40.68 ;
     RECT  72.608 2.148 72.712 41.052 ;
     RECT  72.608 123.108 72.712 170.652 ;
     RECT  72.712 2.418 72.904 40.782 ;
     RECT  72.712 123.378 72.904 170.382 ;
     RECT  72.904 40.656 78.008 40.68 ;
     RECT  78.008 2.148 78.112 41.052 ;
     RECT  78.008 123.108 78.112 170.652 ;
     RECT  78.112 2.418 78.304 40.782 ;
     RECT  78.112 123.378 78.304 170.382 ;
     RECT  78.304 40.656 83.408 40.68 ;
     RECT  83.408 2.148 83.512 41.052 ;
     RECT  83.408 123.108 83.512 170.652 ;
     RECT  83.512 2.418 83.704 40.782 ;
     RECT  83.512 123.378 83.704 170.382 ;
     RECT  83.704 40.656 88.808 40.68 ;
     RECT  88.808 2.148 88.912 41.052 ;
     RECT  88.808 123.108 88.912 170.652 ;
     RECT  88.912 2.418 89.104 40.782 ;
     RECT  88.912 123.378 89.104 170.382 ;
     RECT  89.104 40.656 94.208 40.68 ;
     RECT  94.208 2.148 94.312 41.052 ;
     RECT  94.208 123.108 94.312 170.652 ;
     RECT  94.312 2.418 94.504 40.782 ;
     RECT  94.312 123.378 94.504 170.382 ;
     RECT  94.504 40.656 99.608 40.68 ;
     RECT  99.608 2.148 99.712 41.052 ;
     RECT  99.608 123.108 99.712 170.652 ;
     RECT  99.712 2.418 99.904 40.782 ;
     RECT  99.712 123.378 99.904 170.382 ;
     RECT  99.904 40.656 105.008 40.68 ;
     RECT  104.869 0.096 105.011 0.12 ;
     RECT  105.008 2.148 105.112 41.052 ;
     RECT  105.008 123.108 105.112 170.652 ;
     RECT  105.112 2.418 105.304 40.782 ;
     RECT  105.112 123.378 105.304 170.382 ;
     RECT  110.408 2.148 110.512 41.052 ;
     RECT  110.408 123.108 110.512 170.652 ;
     RECT  110.512 2.418 110.704 40.782 ;
     RECT  110.512 123.378 110.704 170.382 ;
     RECT  115.808 2.148 115.912 41.052 ;
     RECT  115.808 123.108 115.912 170.652 ;
     RECT  115.912 2.418 116.104 40.782 ;
     RECT  115.912 123.378 116.104 170.382 ;
     RECT  121.208 2.148 121.312 41.052 ;
     RECT  121.208 123.108 121.312 170.652 ;
     RECT  121.312 2.418 121.504 40.782 ;
     RECT  121.312 123.378 121.504 170.382 ;
     RECT  126.608 2.148 126.712 41.052 ;
     RECT  126.608 123.108 126.712 170.652 ;
     RECT  126.712 2.418 126.904 40.782 ;
     RECT  126.712 123.378 126.904 170.382 ;
     RECT  132.008 2.148 132.112 41.052 ;
     RECT  132.008 123.108 132.112 170.652 ;
     RECT  132.112 2.418 132.304 40.782 ;
     RECT  132.112 123.378 132.304 170.382 ;
     RECT  137.408 2.148 137.512 41.052 ;
     RECT  137.408 123.108 137.512 170.652 ;
     RECT  137.512 2.418 137.704 40.782 ;
     RECT  137.512 123.378 137.704 170.382 ;
     RECT  142.808 2.148 142.912 41.052 ;
     RECT  142.808 123.108 142.912 170.652 ;
     RECT  142.912 2.418 143.104 40.782 ;
     RECT  142.912 123.378 143.104 170.382 ;
     RECT  148.208 2.148 148.312 41.052 ;
     RECT  148.208 123.108 148.312 170.652 ;
     RECT  148.312 2.418 148.504 40.782 ;
     RECT  148.312 123.378 148.504 170.382 ;
     RECT  153.608 2.148 153.712 41.052 ;
     RECT  153.608 123.108 153.712 170.652 ;
     RECT  153.712 2.418 153.904 40.782 ;
     RECT  153.712 123.378 153.904 170.382 ;
     RECT  159.008 2.148 159.112 41.052 ;
     RECT  159.008 123.108 159.112 170.652 ;
     RECT  159.112 2.418 159.304 40.782 ;
     RECT  159.112 123.378 159.304 170.382 ;
     RECT  164.408 2.148 164.512 41.052 ;
     RECT  164.408 123.108 164.512 170.652 ;
     RECT  164.512 2.418 164.704 40.782 ;
     RECT  164.512 123.378 164.704 170.382 ;
     RECT  169.808 2.148 169.912 41.052 ;
     RECT  169.808 123.108 169.912 170.652 ;
     RECT  169.912 2.418 170.104 40.782 ;
     RECT  169.912 123.378 170.104 170.382 ;
     RECT  175.208 2.148 175.312 41.052 ;
     RECT  175.208 123.108 175.312 170.652 ;
     RECT  175.312 2.418 175.504 40.782 ;
     RECT  175.312 123.378 175.504 170.382 ;
     RECT  180.608 2.148 180.712 41.052 ;
     RECT  180.608 123.108 180.712 170.652 ;
     RECT  180.712 2.418 180.904 40.782 ;
     RECT  180.712 123.378 180.904 170.382 ;
     RECT  186.008 2.148 186.112 41.052 ;
     RECT  186.008 123.108 186.112 170.652 ;
     RECT  186.112 2.418 186.304 40.782 ;
     RECT  186.112 123.378 186.304 170.382 ;
     RECT  191.408 2.148 191.512 41.052 ;
     RECT  191.408 123.108 191.512 170.652 ;
     RECT  191.512 2.418 191.704 40.782 ;
     RECT  191.512 123.378 191.704 170.382 ;
     RECT  22.536 43.2 193.68 120.984 ;
     RECT  193.68 44.256 194.393 120.216 ;
     RECT  194.393 44.352 194.933 120.216 ;
     RECT  194.933 44.544 196.808 120.216 ;
     RECT  196.808 2.148 196.912 170.652 ;
     RECT  196.912 2.418 197.104 170.382 ;
     RECT  202.208 2.148 202.312 170.652 ;
     RECT  202.312 2.418 202.504 170.382 ;
     RECT  207.608 2.148 207.712 170.652 ;
     RECT  207.712 2.418 207.904 170.382 ;
     RECT  213.008 2.148 213.112 170.652 ;
     RECT  213.112 2.418 213.304 170.382 ;
    LAYER M5 ;
     RECT  104.88 0.085 105 0.131 ;
     RECT  104.88 0.131 104.904 2.137 ;
     RECT  2.4 2.137 2.52 2.151 ;
     RECT  7.8 2.137 7.92 2.151 ;
     RECT  13.2 2.137 13.32 2.151 ;
     RECT  18.6 2.137 18.72 2.151 ;
     RECT  24 2.137 24.12 2.151 ;
     RECT  29.4 2.137 29.52 2.151 ;
     RECT  34.8 2.137 34.92 2.151 ;
     RECT  40.2 2.137 40.32 2.151 ;
     RECT  45.6 2.137 45.72 2.151 ;
     RECT  51 2.137 51.12 2.151 ;
     RECT  56.4 2.137 56.52 2.151 ;
     RECT  61.8 2.137 61.92 2.151 ;
     RECT  67.2 2.137 67.32 2.151 ;
     RECT  72.6 2.137 72.72 2.151 ;
     RECT  78 2.137 78.12 2.151 ;
     RECT  83.4 2.137 83.52 2.151 ;
     RECT  88.8 2.137 88.92 2.151 ;
     RECT  94.2 2.137 94.32 2.151 ;
     RECT  99.6 2.137 99.72 2.151 ;
     RECT  104.88 2.137 105.12 2.151 ;
     RECT  110.4 2.137 110.52 2.151 ;
     RECT  115.8 2.137 115.92 2.151 ;
     RECT  121.2 2.137 121.32 2.151 ;
     RECT  126.6 2.137 126.72 2.151 ;
     RECT  132 2.137 132.12 2.151 ;
     RECT  137.4 2.137 137.52 2.151 ;
     RECT  142.8 2.137 142.92 2.151 ;
     RECT  148.2 2.137 148.32 2.151 ;
     RECT  153.6 2.137 153.72 2.151 ;
     RECT  159 2.137 159.12 2.151 ;
     RECT  164.4 2.137 164.52 2.151 ;
     RECT  169.8 2.137 169.92 2.151 ;
     RECT  175.2 2.137 175.32 2.151 ;
     RECT  180.6 2.137 180.72 2.151 ;
     RECT  186 2.137 186.12 2.151 ;
     RECT  191.4 2.137 191.52 2.151 ;
     RECT  196.8 2.137 196.92 2.151 ;
     RECT  202.2 2.137 202.32 2.151 ;
     RECT  207.6 2.137 207.72 2.151 ;
     RECT  213 2.137 213.12 2.151 ;
     RECT  2.4 2.151 2.712 3.733 ;
     RECT  7.8 2.151 8.112 10.213 ;
     RECT  2.4 3.733 3.48 10.309 ;
     RECT  5.712 9.637 5.736 11.317 ;
     RECT  7.008 10.213 8.112 11.891 ;
     RECT  5.712 11.317 5.832 12.563 ;
     RECT  5.808 12.563 5.832 13.573 ;
     RECT  9.504 11.941 9.528 14.389 ;
     RECT  5.808 13.573 5.88 15.637 ;
     RECT  7.2 11.891 8.112 15.637 ;
     RECT  5.808 15.637 8.112 16.117 ;
     RECT  5.088 16.117 8.112 17.605 ;
     RECT  9.456 14.389 9.528 17.605 ;
     RECT  5.088 17.605 9.528 17.651 ;
     RECT  5.088 17.651 6.792 18.851 ;
     RECT  2.4 10.309 3.624 19.141 ;
     RECT  5.808 18.851 6.792 19.333 ;
     RECT  7.8 17.651 9.528 19.333 ;
     RECT  2.4 19.141 4.584 20.197 ;
     RECT  5.808 19.333 9.528 20.197 ;
     RECT  2.4 20.197 9.528 21.011 ;
     RECT  4.464 21.011 9.528 30.611 ;
     RECT  4.512 30.611 9.528 32.483 ;
     RECT  4.56 32.483 9.528 34.355 ;
     RECT  5.184 34.355 9.528 34.595 ;
     RECT  5.232 34.595 9.528 36.997 ;
     RECT  4.56 36.997 9.528 40.597 ;
     RECT  10.512 22.453 10.536 40.597 ;
     RECT  104.88 2.151 105.312 40.691 ;
     RECT  4.56 40.597 10.536 40.835 ;
     RECT  18.6 2.151 18.912 40.885 ;
     RECT  5.232 40.835 10.536 42.709 ;
     RECT  4.272 42.709 10.536 44.483 ;
     RECT  5.232 44.483 10.536 46.741 ;
     RECT  5.232 46.741 11.112 46.885 ;
     RECT  4.32 46.885 11.112 52.165 ;
     RECT  4.032 52.165 11.112 52.211 ;
     RECT  4.032 52.211 4.056 58.357 ;
     RECT  4.032 58.357 4.248 58.403 ;
     RECT  18.432 40.885 18.912 62.293 ;
     RECT  18.432 62.293 19.8 62.531 ;
     RECT  13.2 2.151 13.512 62.725 ;
     RECT  21.36 56.629 21.384 64.405 ;
     RECT  4.224 58.403 4.248 64.595 ;
     RECT  13.104 62.725 13.512 64.741 ;
     RECT  21.36 64.405 21.912 64.885 ;
     RECT  13.104 64.741 13.608 65.845 ;
     RECT  14.88 62.629 15.384 65.845 ;
     RECT  5.232 52.211 11.112 66.469 ;
     RECT  13.104 65.845 15.384 66.661 ;
     RECT  13.008 66.661 15.384 69.827 ;
     RECT  13.104 69.827 15.384 70.069 ;
     RECT  13.104 70.069 16.2 70.117 ;
     RECT  20.208 62.581 20.232 70.403 ;
     RECT  4.752 66.469 11.112 70.547 ;
     RECT  4.992 70.547 11.112 71.749 ;
     RECT  18.432 62.531 18.912 72.901 ;
     RECT  4.992 71.749 11.688 74.003 ;
     RECT  5.232 74.003 11.688 76.067 ;
     RECT  13.104 70.117 17.064 77.797 ;
     RECT  12.576 77.797 17.064 79.763 ;
     RECT  12.768 79.763 17.064 83.795 ;
     RECT  12.96 83.795 17.064 86.869 ;
     RECT  5.232 76.067 11.112 88.309 ;
     RECT  21.36 64.885 22.008 88.643 ;
     RECT  12.96 86.869 17.352 90.373 ;
     RECT  18.432 72.901 19.896 90.373 ;
     RECT  4.368 88.309 11.112 90.947 ;
     RECT  4.512 90.947 11.112 91.763 ;
     RECT  4.512 91.763 10.92 92.963 ;
     RECT  12.96 90.373 19.896 93.445 ;
     RECT  4.608 92.963 10.92 94.739 ;
     RECT  4.608 94.739 5.448 94.981 ;
     RECT  6.672 94.739 10.92 95.219 ;
     RECT  6.672 95.219 10.632 96.467 ;
     RECT  4.56 94.981 5.448 98.387 ;
     RECT  4.56 98.387 5.352 98.771 ;
     RECT  21.888 88.643 22.008 98.915 ;
     RECT  6.672 96.467 10.584 98.917 ;
     RECT  12.528 93.445 19.896 100.741 ;
     RECT  6.624 98.917 10.584 100.837 ;
     RECT  12.096 100.741 19.896 100.837 ;
     RECT  6.624 100.837 19.896 100.883 ;
     RECT  21.888 98.915 21.912 101.171 ;
     RECT  6.624 100.883 12.12 102.131 ;
     RECT  13.104 100.883 19.896 102.613 ;
     RECT  5.328 98.771 5.352 102.659 ;
     RECT  12.096 102.131 12.12 102.899 ;
     RECT  6.624 102.131 10.488 102.947 ;
     RECT  13.104 102.613 20.328 104.245 ;
     RECT  6.672 102.947 10.488 104.293 ;
     RECT  5.28 102.805 5.304 104.339 ;
     RECT  13.056 104.245 20.328 105.107 ;
     RECT  6.672 104.293 10.872 106.451 ;
     RECT  6.672 106.451 9.912 107.795 ;
     RECT  13.2 105.107 20.328 107.845 ;
     RECT  13.104 107.845 20.328 108.755 ;
     RECT  9.6 107.795 9.816 108.805 ;
     RECT  5.424 106.837 5.448 109.139 ;
     RECT  6.672 107.795 8.52 109.381 ;
     RECT  9.6 108.805 10.152 109.381 ;
     RECT  13.2 108.755 20.328 109.907 ;
     RECT  6.672 109.381 10.152 110.533 ;
     RECT  13.2 109.907 15 110.627 ;
     RECT  6.528 110.533 10.152 110.723 ;
     RECT  13.2 110.627 14.04 110.723 ;
     RECT  4.416 108.805 4.44 110.819 ;
     RECT  22.32 110.773 22.344 110.963 ;
     RECT  13.2 110.723 13.752 111.779 ;
     RECT  6.528 110.723 6.696 112.979 ;
     RECT  4.464 110.869 4.488 113.317 ;
     RECT  4.464 113.317 4.632 113.363 ;
     RECT  6.528 112.979 6.552 114.563 ;
     RECT  4.608 113.363 4.632 115.187 ;
     RECT  16.272 109.907 20.328 115.187 ;
     RECT  16.272 115.187 17.352 115.763 ;
     RECT  4.608 116.581 4.632 118.165 ;
     RECT  4.272 118.165 4.632 118.211 ;
     RECT  6.624 114.613 6.648 118.261 ;
     RECT  5.76 118.261 6.648 118.307 ;
     RECT  18.6 115.187 20.328 118.979 ;
     RECT  7.8 110.723 10.152 119.029 ;
     RECT  16.272 115.763 17.064 119.171 ;
     RECT  16.272 119.171 16.44 119.747 ;
     RECT  5.76 118.307 5.784 120.995 ;
     RECT  4.272 118.211 4.296 122.099 ;
     RECT  20.304 118.979 20.328 123.203 ;
     RECT  22.176 120.181 22.2 123.491 ;
     RECT  5.136 123.637 5.16 124.883 ;
     RECT  7.056 119.029 10.152 125.077 ;
     RECT  6.672 125.077 10.152 126.419 ;
     RECT  6.672 126.419 6.696 129.349 ;
     RECT  2.4 21.011 2.712 129.781 ;
     RECT  6.096 129.349 6.696 130.453 ;
     RECT  5.952 130.453 6.696 131.027 ;
     RECT  2.4 129.781 3.48 133.715 ;
     RECT  6.24 131.027 6.696 134.821 ;
     RECT  4.224 134.485 4.248 136.165 ;
     RECT  4.128 136.165 4.248 136.211 ;
     RECT  5.952 134.821 6.696 138.325 ;
     RECT  7.8 126.419 10.152 138.325 ;
     RECT  5.952 138.325 10.152 138.899 ;
     RECT  4.128 136.211 4.152 140.243 ;
     RECT  2.4 133.715 2.712 141.301 ;
     RECT  6.672 138.899 10.152 147.107 ;
     RECT  2.4 141.301 3.672 147.685 ;
     RECT  2.4 147.685 4.584 147.731 ;
     RECT  6.672 147.107 6.696 149.221 ;
     RECT  4.56 147.731 4.584 150.179 ;
     RECT  6.432 149.221 6.696 151.381 ;
     RECT  7.8 147.107 10.152 151.381 ;
     RECT  6.432 151.381 10.152 151.427 ;
     RECT  4.512 150.853 4.536 151.667 ;
     RECT  4.464 153.013 4.488 154.451 ;
     RECT  6.672 151.427 10.152 155.075 ;
     RECT  7.296 155.075 10.152 156.133 ;
     RECT  6.864 156.133 10.152 156.467 ;
     RECT  9.456 156.467 10.152 157.523 ;
     RECT  5.184 155.077 5.208 157.861 ;
     RECT  5.184 157.861 5.64 157.907 ;
     RECT  5.616 157.907 5.64 158.149 ;
     RECT  6.864 156.467 8.112 158.149 ;
     RECT  5.616 158.149 8.112 158.195 ;
     RECT  10.128 157.523 10.152 159.683 ;
     RECT  5.616 158.195 6.36 160.595 ;
     RECT  5.616 160.595 5.64 161.843 ;
     RECT  2.4 147.731 2.712 165.397 ;
     RECT  4.224 161.125 4.248 165.875 ;
     RECT  0.144 164.581 0.168 166.549 ;
     RECT  0.144 166.549 0.216 166.741 ;
     RECT  0.144 166.741 0.264 166.885 ;
     RECT  0.144 166.885 0.312 167.075 ;
     RECT  0.192 167.075 0.312 167.171 ;
     RECT  0.24 167.171 0.312 167.507 ;
     RECT  2.4 165.397 2.808 167.603 ;
     RECT  0.288 167.507 0.312 168.179 ;
     RECT  2.4 167.603 2.712 170.649 ;
     RECT  7.8 158.195 8.112 170.649 ;
     RECT  13.2 111.779 13.512 170.649 ;
     RECT  18.6 118.979 18.912 170.649 ;
     RECT  24 2.151 24.312 170.649 ;
     RECT  29.4 2.151 29.712 170.649 ;
     RECT  34.8 2.151 35.112 170.649 ;
     RECT  40.2 2.151 40.512 170.649 ;
     RECT  45.6 2.151 45.912 170.649 ;
     RECT  51 2.151 51.312 170.649 ;
     RECT  56.4 2.151 56.712 170.649 ;
     RECT  61.8 2.151 62.112 170.649 ;
     RECT  67.2 2.151 67.512 170.649 ;
     RECT  72.6 2.151 72.912 170.649 ;
     RECT  78 2.151 78.312 170.649 ;
     RECT  83.4 2.151 83.712 170.649 ;
     RECT  88.8 2.151 89.112 170.649 ;
     RECT  94.2 2.151 94.512 170.649 ;
     RECT  99.6 2.151 99.912 170.649 ;
     RECT  105 40.691 105.312 170.649 ;
     RECT  110.4 2.151 110.712 170.649 ;
     RECT  115.8 2.151 116.112 170.649 ;
     RECT  121.2 2.151 121.512 170.649 ;
     RECT  126.6 2.151 126.912 170.649 ;
     RECT  132 2.151 132.312 170.649 ;
     RECT  137.4 2.151 137.712 170.649 ;
     RECT  142.8 2.151 143.112 170.649 ;
     RECT  148.2 2.151 148.512 170.649 ;
     RECT  153.6 2.151 153.912 170.649 ;
     RECT  159 2.151 159.312 170.649 ;
     RECT  164.4 2.151 164.712 170.649 ;
     RECT  169.8 2.151 170.112 170.649 ;
     RECT  175.2 2.151 175.512 170.649 ;
     RECT  180.6 2.151 180.912 170.649 ;
     RECT  186 2.151 186.312 170.649 ;
     RECT  191.4 2.151 191.712 170.649 ;
     RECT  196.8 2.151 197.112 170.649 ;
     RECT  202.2 2.151 202.512 170.649 ;
     RECT  207.6 2.151 207.912 170.649 ;
     RECT  213 2.151 213.312 170.649 ;
     RECT  2.4 170.649 2.52 170.663 ;
     RECT  7.8 170.649 7.92 170.663 ;
     RECT  13.2 170.649 13.32 170.663 ;
     RECT  18.6 170.649 18.72 170.663 ;
     RECT  24 170.649 24.12 170.663 ;
     RECT  29.4 170.649 29.52 170.663 ;
     RECT  34.8 170.649 34.92 170.663 ;
     RECT  40.2 170.649 40.32 170.663 ;
     RECT  45.6 170.649 45.72 170.663 ;
     RECT  51 170.649 51.12 170.663 ;
     RECT  56.4 170.649 56.52 170.663 ;
     RECT  61.8 170.649 61.92 170.663 ;
     RECT  67.2 170.649 67.32 170.663 ;
     RECT  72.6 170.649 72.72 170.663 ;
     RECT  78 170.649 78.12 170.663 ;
     RECT  83.4 170.649 83.52 170.663 ;
     RECT  88.8 170.649 88.92 170.663 ;
     RECT  94.2 170.649 94.32 170.663 ;
     RECT  99.6 170.649 99.72 170.663 ;
     RECT  105 170.649 105.12 170.663 ;
     RECT  110.4 170.649 110.52 170.663 ;
     RECT  115.8 170.649 115.92 170.663 ;
     RECT  121.2 170.649 121.32 170.663 ;
     RECT  126.6 170.649 126.72 170.663 ;
     RECT  132 170.649 132.12 170.663 ;
     RECT  137.4 170.649 137.52 170.663 ;
     RECT  142.8 170.649 142.92 170.663 ;
     RECT  148.2 170.649 148.32 170.663 ;
     RECT  153.6 170.649 153.72 170.663 ;
     RECT  159 170.649 159.12 170.663 ;
     RECT  164.4 170.649 164.52 170.663 ;
     RECT  169.8 170.649 169.92 170.663 ;
     RECT  175.2 170.649 175.32 170.663 ;
     RECT  180.6 170.649 180.72 170.663 ;
     RECT  186 170.649 186.12 170.663 ;
     RECT  191.4 170.649 191.52 170.663 ;
     RECT  196.8 170.649 196.92 170.663 ;
     RECT  202.2 170.649 202.32 170.663 ;
     RECT  207.6 170.649 207.72 170.663 ;
     RECT  213 170.649 213.12 170.663 ;
     RECT  5.736 10.213 7.008 11.317 ;
     RECT  5.832 11.317 7.008 11.891 ;
     RECT  5.832 11.891 7.2 13.573 ;
     RECT  8.112 11.941 9.504 14.389 ;
     RECT  5.88 13.573 7.2 15.637 ;
     RECT  8.112 14.389 9.456 17.605 ;
     RECT  3.624 16.117 5.088 18.851 ;
     RECT  6.792 17.651 7.8 19.333 ;
     RECT  3.624 18.851 5.808 19.141 ;
     RECT  4.584 19.141 5.808 20.197 ;
     RECT  9.528 22.453 10.512 40.597 ;
     RECT  2.712 52.165 4.032 58.403 ;
     RECT  4.056 52.211 5.232 58.357 ;
     RECT  4.248 58.357 5.232 64.595 ;
     RECT  2.712 58.403 4.224 64.595 ;
     RECT  18.912 62.531 19.8 62.581 ;
     RECT  18.912 62.581 20.208 70.403 ;
     RECT  20.232 62.581 21.36 70.403 ;
     RECT  13.512 62.629 14.88 64.741 ;
     RECT  13.608 64.741 14.88 65.845 ;
     RECT  17.064 70.117 18.432 86.869 ;
     RECT  11.688 71.749 13.104 76.067 ;
     RECT  19.896 72.901 21.36 88.643 ;
     RECT  11.112 77.797 12.576 79.763 ;
     RECT  17.352 86.869 18.432 90.373 ;
     RECT  5.448 94.739 6.672 98.387 ;
     RECT  5.352 98.387 6.672 98.917 ;
     RECT  5.352 98.917 6.624 102.659 ;
     RECT  10.584 100.741 12.096 100.837 ;
     RECT  12.12 100.883 13.104 102.899 ;
     RECT  5.328 102.659 6.624 102.805 ;
     RECT  5.304 102.805 6.624 102.947 ;
     RECT  13.056 102.899 13.104 104.245 ;
     RECT  5.304 102.947 6.672 104.339 ;
     RECT  5.448 106.837 6.672 109.139 ;
     RECT  8.52 107.795 9.6 109.381 ;
     RECT  9.816 107.795 9.912 108.805 ;
     RECT  4.44 108.805 5.424 109.139 ;
     RECT  6.528 109.139 6.672 110.533 ;
     RECT  15 109.907 16.272 110.627 ;
     RECT  6.696 110.723 7.8 112.979 ;
     RECT  6.552 112.979 7.8 114.563 ;
     RECT  6.624 114.563 7.8 114.613 ;
     RECT  6.648 114.613 7.8 118.307 ;
     RECT  4.608 115.187 4.632 116.581 ;
     RECT  17.352 115.187 18.6 115.763 ;
     RECT  4.296 118.211 4.632 118.261 ;
     RECT  4.296 118.261 5.76 120.995 ;
     RECT  5.784 118.307 7.8 119.029 ;
     RECT  18.912 118.979 20.304 123.203 ;
     RECT  5.784 119.029 7.056 120.995 ;
     RECT  6.696 126.419 7.8 138.325 ;
     RECT  2.712 133.715 3.48 134.485 ;
     RECT  2.712 134.485 4.224 136.165 ;
     RECT  2.712 136.165 4.128 140.243 ;
     RECT  2.712 140.243 3.672 141.301 ;
     RECT  6.696 147.107 7.8 151.381 ;
     RECT  6.864 155.075 7.296 156.133 ;
     RECT  8.112 156.467 9.456 157.523 ;
     RECT  5.64 157.861 6.864 158.149 ;
     RECT  6.36 158.195 7.8 160.595 ;
     RECT  2.712 161.125 4.224 165.397 ;
     RECT  4.248 161.125 5.616 161.843 ;
     RECT  2.808 165.397 4.224 165.875 ;
  END
END ot_qkvd_llr_replay_sram_leaf
END LIBRARY
